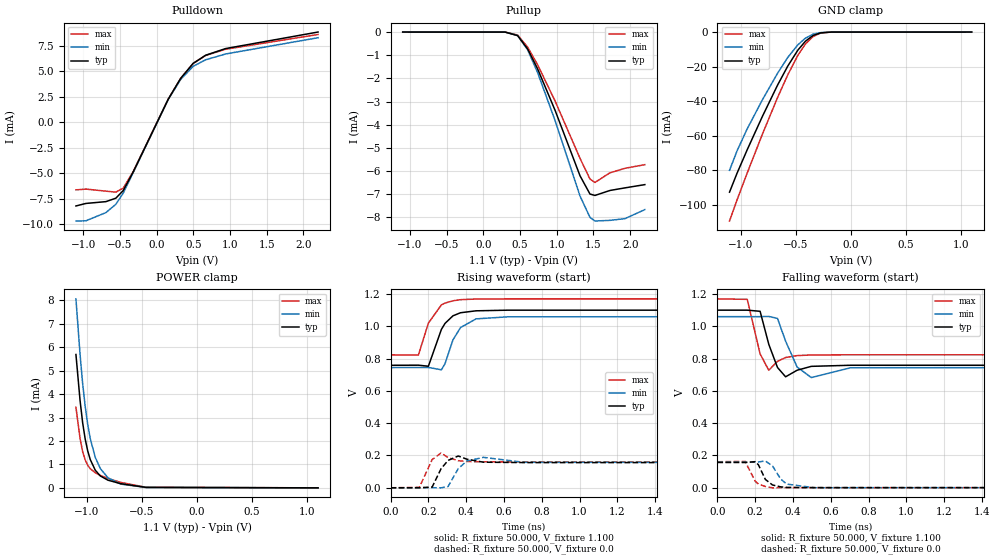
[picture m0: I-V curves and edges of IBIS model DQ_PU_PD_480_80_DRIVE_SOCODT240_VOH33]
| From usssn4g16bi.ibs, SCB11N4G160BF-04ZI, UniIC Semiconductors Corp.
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|   Model DQ_PU_PD_480_80_DRIVE_SOCODT240_VOH33
[Model] DQ_PU_PD_480_80_DRIVE_SOCODT240_VOH33
Model_type I/O
Polarity   Inverting
Vinl =  98.000mV
Vinh =  0.268V
Vmeas =  0.183V
Rref =  50.000
Vref =  0.183V
C_comp   1.020pF   1.010pF   1.030pF
[Model Spec]
Vinh   0.268V   0.262V   0.280V
Vinl   98.000mV   92.000mV   0.110V
Vmeas   0.183V   0.177V   0.195V
Vref   0.183V   0.177V   0.195V
Rref   50.000   NA   NA
[Temperature Range]   25.000   85.000   -40.000
[Voltage Range]   1.100V   1.060V   1.170V
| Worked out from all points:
|   slope of the pulldown table from 0 to 0.165 V, typ, clamps not added: 70.2 ohm
|   GND clamp passes 1 mA (typ) near -0.30 V on its own axis
|   POWER clamp passes 1 mA (typ) near -0.95 V on its own axis
|   rising waveform, R_fixture 50.000, V_fixture 1.100: 20-80 % time 72.7ps typ, 75.2ps min, 70.1ps max; typ from 0.759 V to 1.1 V
|   rising waveform, R_fixture 50.000, V_fixture 0.0: 20-80 % time 36.6ps typ, 44.7ps min, 30.1ps max; typ from 0 V to 0.156 V
|   falling waveform, R_fixture 50.000, V_fixture 1.100: 20-80 % time 44.4ps typ, 55.2ps min, 35.3ps max; typ from 1.1 V to 0.759 V
|   falling waveform, R_fixture 50.000, V_fixture 0.0: 20-80 % time 45.9ps typ, 57.5ps min, 42.8ps max; typ from 0.156 V to 0 V
[Pulldown]
|Voltage   I(typ)   I(min)   I(max)
-1.1V     -8.193mA   -9.666mA   -6.618mA
-964mV    -7.945mA   -9.646mA   -6.54mA
-692mV    -7.769mA   -8.844mA   -6.742mA
-556mV    -7.432mA   -8.032mA   -6.841mA
-454mV    -6.673mA   -6.916mA   -6.44mA
-318mV    -4.841mA   -4.906mA   -4.804mA
158mV     2.257mA    2.237mA    2.267mA
328mV     4.302mA    4.2mA      4.305mA
498mV     5.77mA     5.483mA    5.759mA
668mV     6.567mA    6.118mA    6.54mA
940mV     7.217mA    6.688mA    7.152mA
2.2V      8.836mA    8.278mA    8.595mA
[Pullup]
|Voltage   I(typ)   I(min)   I(max)
-1.1V     500pA      2.606nA    0A
296mV     -2.948uA   -3.529uA   -1.641uA
466mV     -154.8uA   -152.1uA   -129.1uA
602mV     -725.8uA   -765uA     -649.5uA
738mV     -1.585mA   -1.746mA   -1.41mA
976mV     -3.374mA   -3.816mA   -2.972mA
1.316V    -6.198mA   -7.072mA   -5.446mA
1.452V    -6.989mA   -7.995mA   -6.341mA
1.52V     -7.049mA   -8.152mA   -6.489mA
1.724V    -6.835mA   -8.124mA   -6.072mA
1.928V    -6.723mA   -8.051mA   -5.878mA
2.2V      -6.582mA   -7.66mA    -5.721mA
[GND_clamp]
|Voltage   I(typ)   I(min)   I(max)
-1.1V     -92.78mA   -80.14mA   -109.5mA
-1.031V   -81.73mA   -68.77mA   -97.17mA
-939mV    -68.18mA   -56.07mA   -81.64mA
-801mV    -48.85mA   -39.25mA   -59.15mA
-663mV    -30.71mA   -23.84mA   -37.89mA
-571mV    -19.76mA   -14.75mA   -24.85mA
-479mV    -10.5mA    -7.415mA   -13.5mA
-410mV    -5.313mA   -3.546mA   -6.916mA
-341mV    -2.007mA   -1.262mA   -2.59mA
-272mV    -506.9uA   -323.5uA   -609.8uA
-180mV    -45.65uA   -36.06uA   -43.55uA
1.1V      0A         0A         0A
[POWER_clamp]
|Voltage   I(typ)   I(min)   I(max)
-1.1V     5.691mA    8.066mA    3.44mA
-1.062V   3.709mA    5.665mA    2.092mA
-1.039V   2.781mA    4.457mA    1.546mA
-1.016V   2.086mA    3.48mA     1.193mA
-993mV    1.578mA    2.707mA    966.5uA
-970mV    1.21mA     2.107mA    818.5uA
-924mV    750.8uA    1.296mA    641.3uA
-878mV    507uA      821.4uA    530.2uA
-809mV    327.4uA    430uA      403.3uA
-694mV    178.4uA    161uA      233uA
-464mV    19.89uA    15.19uA    23.61uA
1.1V      0A         0A         0A
[Ramp]
| variable   typ   min   max
dV/dt_r   93.600m/36.664p   94.432m/44.767p   96.210m/30.186p
dV/dt_f   0.205/44.503p   0.189/55.256p   0.208/35.422p
R_load = 50.000
[Rising Waveform]
R_fixture= 50.000
V_fixture= 1.100
V_fixture_min= 1.060
V_fixture_max= 1.170
|time   V(typ)   V(min)   V(max)
0s        758.6mV    744.6mV    823.3mV
147ps     759.3mV    745mV      821.7mV
200ps     752.7mV    745.1mV    1.02V
269ps     981.3mV    730.8mV    1.133V
288ps     1.018V     768.7mV    1.144V
330ps     1.065V     915.7mV    1.158V
370ps     1.084V     992.1mV    1.165V
452ps     1.096V     1.046V     1.169V
622ps     1.1V       1.059V     1.17V
3ns       1.1V       1.06V      1.17V
[Rising Waveform]
R_fixture= 50.000
V_fixture= 0.0
V_fixture_min= 0.0
V_fixture_max= 0.0
|time   V(typ)   V(min)   V(max)
0s        3.732uV    7.145uV    882.6nV
152ps     103.7uV    10.76uV    2.587mV
220ps     4.697mV    269.6uV    174.6mV
267ps     117.8mV    -495.1uV   215.5mV
304ps     169.4mV    7.341mV    186.9mV
358ps     196.8mV    118.5mV    167.5mV
403ps     177.2mV    165.3mV    162.8mV
491ps     158.4mV    188.4mV    160.7mV
705ps     156mV      157.7mV    160.3mV
3ns       156mV      157.4mV    160.3mV
[Falling Waveform]
R_fixture= 50.000
V_fixture= 1.100
V_fixture_min= 1.060
V_fixture_max= 1.170
|time   V(typ)   V(min)   V(max)
0s        1.1V       1.06V      1.17V
158ps     1.1V       1.06V      1.167V
226ps     1.093V     1.06V      828.9mV
272ps     888.3mV    1.061V     727.4mV
318ps     744.8mV    1.049V     782.8mV
361ps     686.9mV    907.8mV    806.4mV
422ps     727.7mV    747.4mV    818.3mV
497ps     751.7mV    682.2mV    822.2mV
705ps     758.5mV    743.1mV    823.3mV
3ns       758.6mV    744.6mV    823.3mV
[Falling Waveform]
R_fixture= 50.000
V_fixture= 0.0
V_fixture_min= 0.0
V_fixture_max= 0.0
|time   V(typ)   V(min)   V(max)
0s        156mV      157.4mV    160.3mV
147ps     155.8mV    157.2mV    162.6mV
200ps     161mV      157.4mV    39.31mV
217ps     141.6mV    158.9mV    22.47mV
254ps     50.63mV    165.2mV    6.835mV
292ps     16.24mV    133.7mV    -1.368mV
335ps     4.808mV    53.33mV    -442uV
367ps     1.283mV    21.94mV    -155.6uV
513ps     -62.95uV   -622.8uV   -828.7nV
3ns       2.958uV    7.055uV    500.8nV
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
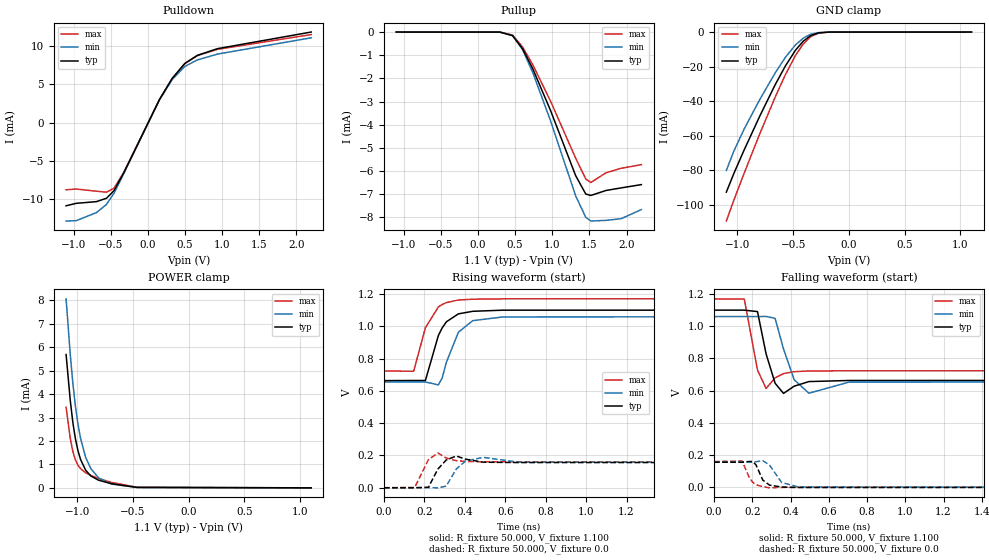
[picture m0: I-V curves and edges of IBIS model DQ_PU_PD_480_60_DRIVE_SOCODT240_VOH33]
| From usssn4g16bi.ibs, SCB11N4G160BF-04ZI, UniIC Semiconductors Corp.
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|   Model DQ_PU_PD_480_60_DRIVE_SOCODT240_VOH33
[Model] DQ_PU_PD_480_60_DRIVE_SOCODT240_VOH33
Model_type I/O
Polarity   Inverting
Vinl =  98.000mV
Vinh =  0.268V
Vmeas =  0.183V
Rref =  50.000
Vref =  0.183V
C_comp   1.020pF   1.010pF   1.030pF
[Model Spec]
Vinh   0.268V   0.262V   0.280V
Vinl   98.000mV   92.000mV   0.110V
Vmeas   0.183V   0.177V   0.195V
Vref   0.183V   0.177V   0.195V
Rref   50.000   NA   NA
[Temperature Range]   25.000   85.000   -40.000
[Voltage Range]   1.100V   1.060V   1.170V
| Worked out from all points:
|   slope of the pulldown table from 0 to 0.165 V, typ, clamps not added: 52.7 ohm
|   GND clamp passes 1 mA (typ) near -0.30 V on its own axis
|   POWER clamp passes 1 mA (typ) near -0.95 V on its own axis
|   rising waveform, R_fixture 50.000, V_fixture 1.100: 20-80 % time 74.3ps typ, 76.9ps min, 71.5ps max; typ from 0.663 V to 1.1 V
|   rising waveform, R_fixture 50.000, V_fixture 0.0: 20-80 % time 36.5ps typ, 44.4ps min, 30ps max; typ from 0 V to 0.156 V
|   falling waveform, R_fixture 50.000, V_fixture 1.100: 20-80 % time 43.7ps typ, 54.4ps min, 35ps max; typ from 1.1 V to 0.663 V
|   falling waveform, R_fixture 50.000, V_fixture 0.0: 20-80 % time 40.7ps typ, 54.3ps min, 37.6ps max; typ from 0.156 V to 0 V
[Pulldown]
|Voltage   I(typ)   I(min)   I(max)
-1.1V     -10.83mA   -12.81mA   -8.746mA
-964mV    -10.51mA   -12.77mA   -8.65mA
-692mV    -10.29mA   -11.72mA   -8.932mA
-556mV    -9.849mA   -10.65mA   -9.063mA
-454mV    -8.849mA   -9.178mA   -8.534mA
-318mV    -6.436mA   -6.525mA   -6.383mA
158mV     3.005mA    2.979mA    3.019mA
328mV     5.729mA    5.594mA    5.734mA
498mV     7.686mA    7.305mA    7.672mA
668mV     8.751mA    8.153mA    8.715mA
940mV     9.618mA    8.913mA    9.532mA
2.2V      11.78mA    11.03mA    11.45mA
[Pullup]
|Voltage   I(typ)   I(min)   I(max)
-1.1V     500pA      2.606nA    0A
296mV     -2.948uA   -3.529uA   -1.641uA
466mV     -154.8uA   -152.1uA   -129.1uA
602mV     -725.8uA   -765uA     -649.5uA
738mV     -1.585mA   -1.746mA   -1.41mA
976mV     -3.374mA   -3.816mA   -2.972mA
1.316V    -6.198mA   -7.072mA   -5.446mA
1.452V    -6.989mA   -7.995mA   -6.341mA
1.52V     -7.049mA   -8.152mA   -6.489mA
1.724V    -6.835mA   -8.124mA   -6.072mA
1.928V    -6.723mA   -8.051mA   -5.878mA
2.2V      -6.582mA   -7.66mA    -5.721mA
[GND_clamp]
|Voltage   I(typ)   I(min)   I(max)
-1.1V     -92.78mA   -80.14mA   -109.5mA
-1.031V   -81.73mA   -68.77mA   -97.17mA
-939mV    -68.18mA   -56.07mA   -81.64mA
-801mV    -48.85mA   -39.25mA   -59.15mA
-663mV    -30.71mA   -23.84mA   -37.89mA
-571mV    -19.76mA   -14.75mA   -24.85mA
-479mV    -10.5mA    -7.415mA   -13.5mA
-410mV    -5.313mA   -3.546mA   -6.916mA
-341mV    -2.007mA   -1.262mA   -2.59mA
-272mV    -506.9uA   -323.5uA   -609.8uA
-180mV    -45.65uA   -36.06uA   -43.55uA
1.1V      0A         0A         0A
[POWER_clamp]
|Voltage   I(typ)   I(min)   I(max)
-1.1V     5.691mA    8.066mA    3.44mA
-1.062V   3.709mA    5.665mA    2.092mA
-1.039V   2.781mA    4.457mA    1.546mA
-1.016V   2.086mA    3.48mA     1.193mA
-993mV    1.578mA    2.707mA    966.5uA
-970mV    1.21mA     2.107mA    818.5uA
-924mV    750.8uA    1.296mA    641.3uA
-878mV    507uA      821.4uA    530.2uA
-809mV    327.4uA    430uA      403.3uA
-694mV    178.4uA    161uA      233uA
-464mV    19.89uA    15.19uA    23.61uA
1.1V      0A         0A         0A
[Ramp]
| variable   typ   min   max
dV/dt_r   93.600m/36.486p   94.432m/44.493p   96.210m/30.147p
dV/dt_f   0.262/43.724p   0.243/54.501p   0.268/35.010p
R_load = 50.000
[Rising Waveform]
R_fixture= 50.000
V_fixture= 1.100
V_fixture_min= 1.060
V_fixture_max= 1.170
|time   V(typ)   V(min)   V(max)
0s        663.5mV    654.8mV    723.5mV
147ps     664.4mV    655.3mV    721.5mV
205ps     664.1mV    654.8mV    990.6mV
269ps     942.1mV    637.4mV    1.12V
288ps     990.3mV    679.8mV    1.135V
309ps     1.028V     777.8mV    1.147V
368ps     1.077V     963mV      1.163V
439ps     1.093V     1.035V     1.168V
589ps     1.1V       1.058V     1.17V
3ns       1.1V       1.06V      1.17V
[Rising Waveform]
R_fixture= 50.000
V_fixture= 0.0
V_fixture_min= 0.0
V_fixture_max= 0.0
|time   V(typ)   V(min)   V(max)
0s        3.262uV    6.246uV    771.1nV
152ps     171.2uV    9.155uV    1.764mV
220ps     3.07mV     378.1uV    173.9mV
267ps     116.1mV    -658.4uV   215.2mV
308ps     172mV      10.32mV    184.3mV
358ps     196.6mV    116.5mV    167.6mV
403ps     177.2mV    164.9mV    162.8mV
491ps     158.4mV    188.3mV    160.6mV
667ps     156mV      158mV      160.4mV
3ns       156mV      157.4mV    160.3mV
[Falling Waveform]
R_fixture= 50.000
V_fixture= 1.100
V_fixture_min= 1.060
V_fixture_max= 1.170
|time   V(typ)   V(min)   V(max)
0s        1.1V       1.06V      1.17V
158ps     1.1V       1.06V      1.169V
227ps     1.091V     1.06V      728.1mV
272ps     828.5mV    1.061V     614mV
319ps     646.5mV    1.049V     679.6mV
363ps     583.2mV    859.3mV    706.4mV
419ps     628.2mV    667.7mV    718.1mV
496ps     656.6mV    584.3mV    722.4mV
705ps     663.4mV    653.2mV    723.5mV
3ns       663.5mV    654.8mV    723.5mV
[Falling Waveform]
R_fixture= 50.000
V_fixture= 0.0
V_fixture_min= 0.0
V_fixture_max= 0.0
|time   V(typ)   V(min)   V(max)
0s        156mV      157.4mV    160.3mV
147ps     155.8mV    157.2mV    163.6mV
182ps     160.4mV    157mV      65.92mV
202ps     160.8mV    157.5mV    30.88mV
219ps     139.8mV    159.1mV    16.32mV
255ps     44.87mV    165.1mV    4.409mV
290ps     13.76mV    138.3mV    -3.026mV
353ps     1.95mV     30.16mV    -431.3uV
440ps     -858.6uV   2.579mV    -20.73uV
3ns       3.16uV     6.128uV    560.6nV
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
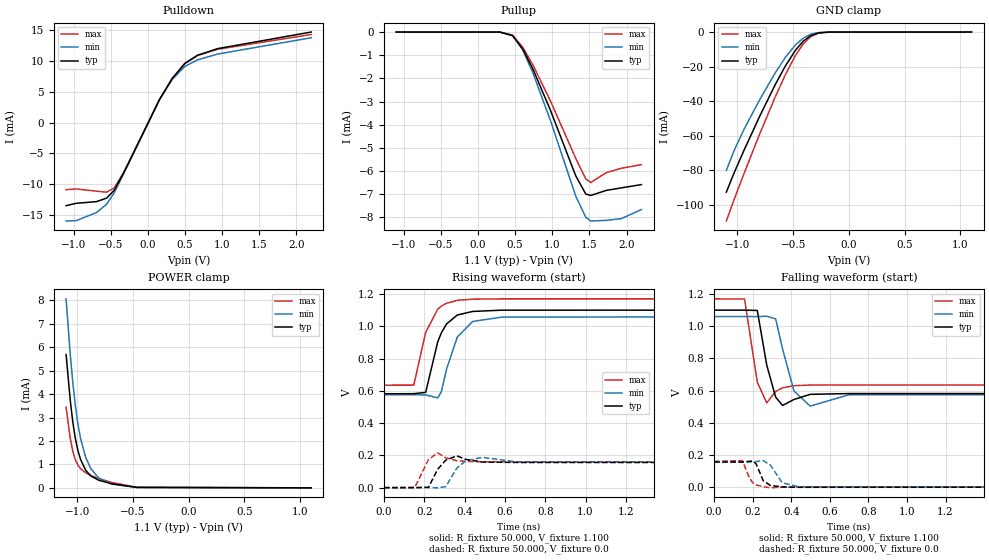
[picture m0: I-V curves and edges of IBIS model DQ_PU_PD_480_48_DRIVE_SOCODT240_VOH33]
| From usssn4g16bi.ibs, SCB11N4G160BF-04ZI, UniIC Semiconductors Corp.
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|   Model DQ_PU_PD_480_48_DRIVE_SOCODT240_VOH33
[Model] DQ_PU_PD_480_48_DRIVE_SOCODT240_VOH33
Model_type I/O
Polarity   Inverting
Vinl =  98.000mV
Vinh =  0.268V
Vmeas =  0.183V
Rref =  50.000
Vref =  0.183V
C_comp   1.020pF   1.010pF   1.030pF
[Model Spec]
Vinh   0.268V   0.262V   0.280V
Vinl   98.000mV   92.000mV   0.110V
Vmeas   0.183V   0.177V   0.195V
Vref   0.183V   0.177V   0.195V
Rref   50.000   NA   NA
[Temperature Range]   25.000   85.000   -40.000
[Voltage Range]   1.100V   1.060V   1.170V
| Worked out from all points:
|   slope of the pulldown table from 0 to 0.165 V, typ, clamps not added: 42.3 ohm
|   GND clamp passes 1 mA (typ) near -0.30 V on its own axis
|   POWER clamp passes 1 mA (typ) near -0.95 V on its own axis
|   rising waveform, R_fixture 50.000, V_fixture 1.100: 20-80 % time 75.5ps typ, 78.3ps min, 72.7ps max; typ from 0.582 V to 1.1 V
|   rising waveform, R_fixture 50.000, V_fixture 0.0: 20-80 % time 36.1ps typ, 44.1ps min, 29.8ps max; typ from 0 V to 0.156 V
|   falling waveform, R_fixture 50.000, V_fixture 1.100: 20-80 % time 42.4ps typ, 53.2ps min, 34.3ps max; typ from 1.1 V to 0.582 V
|   falling waveform, R_fixture 50.000, V_fixture 0.0: 20-80 % time 36.4ps typ, 50.3ps min, 33.4ps max; typ from 0.156 V to 0 V
[Pulldown]
|Voltage   I(typ)   I(min)   I(max)
-1.1V     -13.51mA   -16mA      -10.91mA
-964mV    -13.12mA   -15.94mA   -10.79mA
-692mV    -12.85mA   -14.63mA   -11.15mA
-556mV    -12.29mA   -13.29mA   -11.31mA
-454mV    -11.04mA   -11.45mA   -10.65mA
-318mV    -8.03mA    -8.142mA   -7.964mA
158mV     3.751mA    3.718mA    3.768mA
328mV     7.153mA    6.985mA    7.158mA
498mV     9.598mA    9.123mA    9.581mA
668mV     10.93mA    10.18mA    10.89mA
940mV     12.01mA    11.13mA    11.91mA
2.2V      14.71mA    13.78mA    14.31mA
[Pullup]
|Voltage   I(typ)   I(min)   I(max)
-1.1V     500pA      2.606nA    0A
296mV     -2.948uA   -3.529uA   -1.641uA
466mV     -154.8uA   -152.1uA   -129.1uA
602mV     -725.8uA   -765uA     -649.5uA
738mV     -1.585mA   -1.746mA   -1.41mA
976mV     -3.374mA   -3.816mA   -2.972mA
1.316V    -6.198mA   -7.072mA   -5.446mA
1.452V    -6.989mA   -7.995mA   -6.341mA
1.52V     -7.049mA   -8.152mA   -6.489mA
1.724V    -6.835mA   -8.124mA   -6.072mA
1.928V    -6.723mA   -8.051mA   -5.878mA
2.2V      -6.582mA   -7.66mA    -5.721mA
[GND_clamp]
|Voltage   I(typ)   I(min)   I(max)
-1.1V     -92.78mA   -80.14mA   -109.5mA
-1.031V   -81.73mA   -68.77mA   -97.17mA
-939mV    -68.18mA   -56.07mA   -81.64mA
-801mV    -48.85mA   -39.25mA   -59.15mA
-663mV    -30.71mA   -23.84mA   -37.89mA
-571mV    -19.76mA   -14.75mA   -24.85mA
-479mV    -10.5mA    -7.415mA   -13.5mA
-410mV    -5.313mA   -3.546mA   -6.916mA
-341mV    -2.007mA   -1.262mA   -2.59mA
-272mV    -506.9uA   -323.5uA   -609.8uA
-180mV    -45.65uA   -36.06uA   -43.55uA
1.1V      0A         0A         0A
[POWER_clamp]
|Voltage   I(typ)   I(min)   I(max)
-1.1V     5.691mA    8.066mA    3.44mA
-1.062V   3.709mA    5.665mA    2.092mA
-1.039V   2.781mA    4.457mA    1.546mA
-1.016V   2.086mA    3.48mA     1.193mA
-993mV    1.578mA    2.707mA    966.5uA
-970mV    1.21mA     2.107mA    818.5uA
-924mV    750.8uA    1.296mA    641.3uA
-878mV    507uA      821.4uA    530.2uA
-809mV    327.4uA    430uA      403.3uA
-694mV    178.4uA    161uA      233uA
-464mV    19.89uA    15.19uA    23.61uA
1.1V      0A         0A         0A
[Ramp]
| variable   typ   min   max
dV/dt_r   93.601m/36.320p   94.433m/44.127p   96.210m/30.018p
dV/dt_f   0.311/42.321p   0.291/53.189p   0.321/34.356p
R_load = 50.000
[Rising Waveform]
R_fixture= 50.000
V_fixture= 1.100
V_fixture_min= 1.060
V_fixture_max= 1.170
|time   V(typ)   V(min)   V(max)
0s        581.6mV    575.3mV    635mV
148ps     582.4mV    575.9mV    635.5mV
207ps     590.4mV    574.8mV    961.8mV
267ps     904.1mV    556.2mV    1.107V
285ps     959.8mV    596.1mV    1.125V
311ps     1.015V     736.1mV    1.143V
364ps     1.07V      933.4mV    1.161V
440ps     1.092V     1.03V      1.168V
585ps     1.1V       1.057V     1.17V
3ns       1.1V       1.06V      1.17V
[Rising Waveform]
R_fixture= 50.000
V_fixture= 0.0
V_fixture_min= 0.0
V_fixture_max= 0.0
|time   V(typ)   V(min)   V(max)
0s        2.898uV    5.55uV     685nV
153ps     271.6uV    5.056uV    1.55mV
221ps     2.351mV    510.8uV    174.7mV
267ps     114.7mV    -1.167mV   215.2mV
307ps     170.7mV    6.529mV    184.8mV
362ps     197.3mV    121.8mV    166.9mV
406ps     175.3mV    166.1mV    162.7mV
487ps     158.7mV    188mV      160.7mV
669ps     156mV      158mV      160.4mV
3ns       156mV      157.4mV    160.3mV
[Falling Waveform]
R_fixture= 50.000
V_fixture= 1.100
V_fixture_min= 1.060
V_fixture_max= 1.170
|time   V(typ)   V(min)   V(max)
0s        1.1V       1.06V      1.17V
158ps     1.1V       1.06V      1.169V
224ps     1.098V     1.06V      652.5mV
273ps     758.5mV    1.062V     523.5mV
319ps     559.9mV    1.046V     593.9mV
355ps     507.6mV    859.2mV    617.5mV
414ps     544.8mV    598.3mV    630.4mV
498ps     576.6mV    503.5mV    634.3mV
699ps     581.5mV    573.9mV    635mV
3ns       581.6mV    575.3mV    635mV
[Falling Waveform]
R_fixture= 50.000
V_fixture= 0.0
V_fixture_min= 0.0
V_fixture_max= 0.0
|time   V(typ)   V(min)   V(max)
0s        156mV      157.4mV    160.3mV
147ps     155.7mV    157.2mV    164.8mV
182ps     160.4mV    157mV      60.51mV
201ps     162.4mV    157.3mV    26.91mV
218ps     144.2mV    158.9mV    13.14mV
255ps     40.23mV    165mV      3.043mV
292ps     10.2mV     137mV      -4.399mV
353ps     1.401mV    27.36mV    -471.9uV
439ps     -1.026mV   2.044mV    -15.45uV
3ns       2.826uV    5.074uV    343.6nV
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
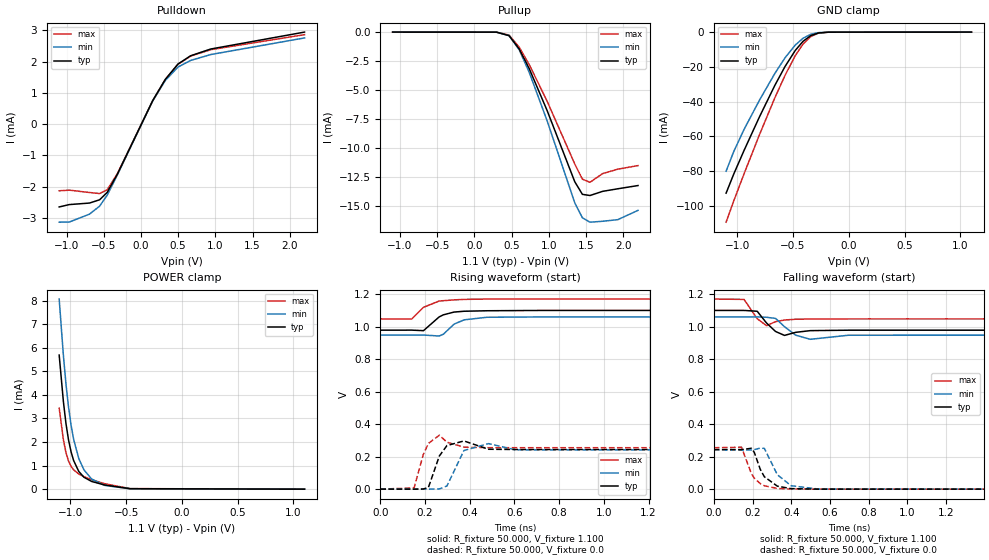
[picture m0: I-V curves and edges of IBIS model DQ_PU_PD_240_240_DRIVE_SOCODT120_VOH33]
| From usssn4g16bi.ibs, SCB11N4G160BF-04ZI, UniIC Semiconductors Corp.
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|   Model DQ_PU_PD_240_240_DRIVE_SOCODT120_VOH33
[Model] DQ_PU_PD_240_240_DRIVE_SOCODT120_VOH33
Model_type I/O
Polarity   Inverting
Vinl =  98.000mV
Vinh =  0.268V
Vmeas =  0.183V
Rref =  50.000
Vref =  0.183V
C_comp   1.020pF   1.010pF   1.030pF
[Model Spec]
Vinh   0.268V   0.262V   0.280V
Vinl   98.000mV   92.000mV   0.110V
Vmeas   0.183V   0.177V   0.195V
Vref   0.183V   0.177V   0.195V
Rref   50.000   NA   NA
[Temperature Range]   25.000   85.000   -40.000
[Voltage Range]   1.100V   1.060V   1.170V
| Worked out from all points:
|   slope of the pulldown table from 0 to 0.165 V, typ, clamps not added: 211 ohm
|   GND clamp passes 1 mA (typ) near -0.30 V on its own axis
|   POWER clamp passes 1 mA (typ) near -0.95 V on its own axis
|   rising waveform, R_fixture 50.000, V_fixture 1.100: 20-80 % time 68.4ps typ, 69.2ps min, 67.2ps max; typ from 0.978 V to 1.1 V
|   rising waveform, R_fixture 50.000, V_fixture 0.0: 20-80 % time 33.2ps typ, 41.1ps min, 27.1ps max; typ from 0 V to 0.244 V
|   falling waveform, R_fixture 50.000, V_fixture 1.100: 20-80 % time 46.2ps typ, 57.9ps min, 36ps max; typ from 1.1 V to 0.978 V
|   falling waveform, R_fixture 50.000, V_fixture 0.0: 20-80 % time 63.2ps typ, 70.2ps min, 60.2ps max; typ from 0.244 V to 0 V
[Pulldown]
|Voltage   I(typ)   I(min)   I(max)
-1.1V     -2.652mA   -3.14mA    -2.134mA
-964mV    -2.576mA   -3.135mA   -2.114mA
-692mV    -2.527mA   -2.882mA   -2.189mA
-556mV    -2.422mA   -2.626mA   -2.223mA
-454mV    -2.185mA   -2.274mA   -2.101mA
-318mV    -1.604mA   -1.629mA   -1.589mA
158mV     752.2uA    745.4uA    755.4uA
328mV     1.434mA    1.4mA      1.435mA
498mV     1.924mA    1.828mA    1.92mA
668mV     2.19mA     2.04mA     2.18mA
940mV     2.407mA    2.23mA     2.385mA
2.2V      2.948mA    2.761mA    2.866mA
[Pullup]
|Voltage   I(typ)   I(min)   I(max)
-1.1V     1nA        5.218nA    0A
296mV     -5.896uA   -7.058uA   -3.281uA
466mV     -309.5uA   -304uA     -258.1uA
602mV     -1.45mA    -1.529mA   -1.298mA
738mV     -3.167mA   -3.489mA   -2.817mA
976mV     -6.74mA    -7.622mA   -5.938mA
1.35V     -12.91mA   -14.73mA   -11.38mA
1.452V    -13.99mA   -16.01mA   -12.68mA
1.554V    -14.09mA   -16.39mA   -12.95mA
1.724V    -13.73mA   -16.31mA   -12.2mA
1.928V    -13.51mA   -16.17mA   -11.82mA
2.2V      -13.23mA   -15.37mA   -11.51mA
[GND_clamp]
|Voltage   I(typ)   I(min)   I(max)
-1.1V     -92.78mA   -80.14mA   -109.5mA
-1.031V   -81.73mA   -68.77mA   -97.17mA
-939mV    -68.18mA   -56.07mA   -81.64mA
-801mV    -48.85mA   -39.25mA   -59.15mA
-663mV    -30.71mA   -23.84mA   -37.89mA
-571mV    -19.76mA   -14.75mA   -24.85mA
-479mV    -10.5mA    -7.415mA   -13.5mA
-410mV    -5.313mA   -3.546mA   -6.916mA
-341mV    -2.007mA   -1.262mA   -2.59mA
-272mV    -506.9uA   -323.5uA   -609.8uA
-180mV    -45.65uA   -36.06uA   -43.55uA
1.1V      0A         0A         0A
[POWER_clamp]
|Voltage   I(typ)   I(min)   I(max)
-1.1V     5.691mA    8.066mA    3.44mA
-1.062V   3.709mA    5.665mA    2.092mA
-1.039V   2.781mA    4.457mA    1.546mA
-1.016V   2.086mA    3.48mA     1.193mA
-993mV    1.578mA    2.707mA    966.5uA
-970mV    1.21mA     2.107mA    818.5uA
-924mV    750.8uA    1.296mA    641.3uA
-878mV    507uA      821.4uA    530.2uA
-809mV    327.4uA    430uA      403.3uA
-694mV    178.4uA    161uA      233uA
-464mV    19.89uA    15.19uA    23.61uA
1.1V      0A         0A         0A
[Ramp]
| variable   typ   min   max
dV/dt_r   0.146/33.433p   0.145/41.080p   0.153/27.195p
dV/dt_f   72.903m/46.226p   67.052m/58.007p   73.268m/36.035p
R_load = 50.000
[Rising Waveform]
R_fixture= 50.000
V_fixture= 1.100
V_fixture_min= 1.060
V_fixture_max= 1.170
|time   V(typ)   V(min)   V(max)
0s        978.5mV    948.3mV    1.048V
140ps     978.8mV    948.4mV    1.047V
193ps     975.5mV    948.6mV    1.119V
263ps     1.06V      942.5mV    1.158V
282ps     1.073V     953.6mV    1.16V
330ps     1.09V      1.016V     1.165V
375ps     1.095V     1.042V     1.168V
476ps     1.098V     1.058V     1.17V
721ps     1.1V       1.06V      1.17V
3ns       1.1V       1.06V      1.17V
[Rising Waveform]
R_fixture= 50.000
V_fixture= 0.0
V_fixture_min= 0.0
V_fixture_max= 0.0
|time   V(typ)   V(min)   V(max)
0s        5.235uV    10.02uV    1.24uV
151ps     -127.8uV   45.32uV    7.711mV
192ps     848.9uV    -47.81uV   212.6mV
215ps     10.21mV    -154.5uV   281.6mV
264ps     204.2mV    1.17mV     331.9mV
298ps     268.3mV    19.55mV    288.9mV
374ps     296.6mV    237.9mV    258.3mV
484ps     245.5mV    280.3mV    255.2mV
604ps     244mV      242.1mV    255mV
3ns       243.9mV    241.2mV    255mV
[Falling Waveform]
R_fixture= 50.000
V_fixture= 1.100
V_fixture_min= 1.060
V_fixture_max= 1.170
|time   V(typ)   V(min)   V(max)
0s        1.1V       1.06V      1.17V
156ps     1.1V       1.06V      1.168V
224ps     1.095V     1.06V      1.049V
272ps     1.023V     1.058V     1.006V
319ps     970.3mV    1.051V     1.031V
365ps     946.4mV    1V         1.041V
423ps     965.3mV    947.7mV    1.046V
498ps     975.7mV    922.4mV    1.047V
697ps     978.4mV    947.6mV    1.048V
3ns       978.5mV    948.3mV    1.048V
[Falling Waveform]
R_fixture= 50.000
V_fixture= 0.0
V_fixture_min= 0.0
V_fixture_max= 0.0
|time   V(typ)   V(min)   V(max)
0s        243.9mV    241.2mV    255mV
143ps     243.7mV    240.9mV    258.3mV
194ps     251.5mV    241.1mV    95.54mV
209ps     226.3mV    243.4mV    68.11mV
240ps     121.8mV    252.8mV    33.86mV
261ps     76.35mV    250.7mV    20.93mV
328ps     18.5mV     88.91mV    4.304mV
399ps     3.312mV    21.3mV     941.3uV
539ps     201.8uV    770.9uV    47.05uV
3ns       5.289uV    10.03uV    1.062uV
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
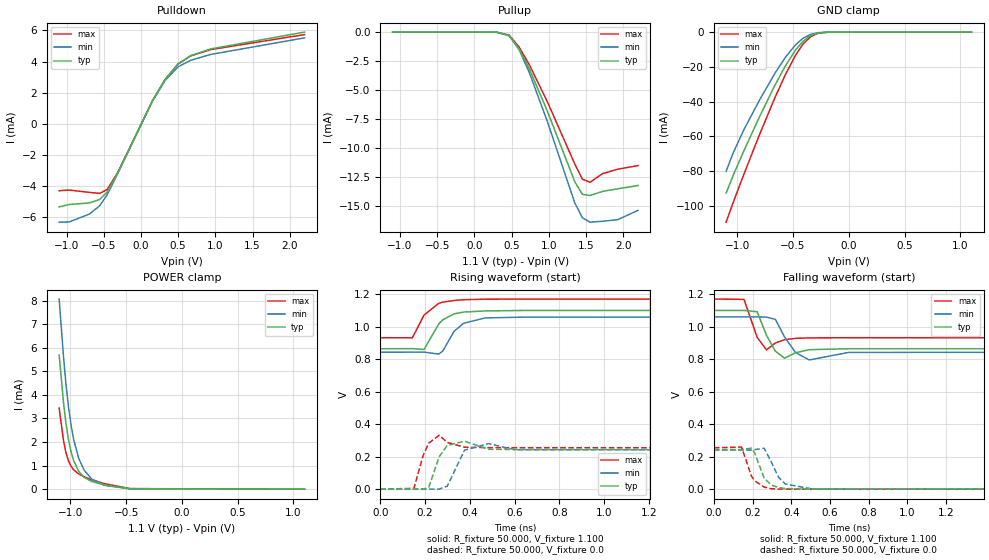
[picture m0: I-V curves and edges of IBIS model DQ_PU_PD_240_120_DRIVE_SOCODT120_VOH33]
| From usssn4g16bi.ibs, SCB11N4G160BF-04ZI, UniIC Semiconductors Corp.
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|   Model DQ_PU_PD_240_120_DRIVE_SOCODT120_VOH33
[Model] DQ_PU_PD_240_120_DRIVE_SOCODT120_VOH33
Model_type I/O
Polarity   Inverting
Vinl =  98.000mV
Vinh =  0.268V
Vmeas =  0.183V
Rref =  50.000
Vref =  0.183V
C_comp   1.020pF   1.010pF   1.030pF
[Model Spec]
Vinh   0.268V   0.262V   0.280V
Vinl   98.000mV   92.000mV   0.110V
Vmeas   0.183V   0.177V   0.195V
Vref   0.183V   0.177V   0.195V
Rref   50.000   NA   NA
[Temperature Range]   25.000   85.000   -40.000
[Voltage Range]   1.100V   1.060V   1.170V
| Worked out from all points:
|   slope of the pulldown table from 0 to 0.165 V, typ, clamps not added: 105 ohm
|   GND clamp passes 1 mA (typ) near -0.30 V on its own axis
|   POWER clamp passes 1 mA (typ) near -0.95 V on its own axis
|   rising waveform, R_fixture 50.000, V_fixture 1.100: 20-80 % time 70.2ps typ, 71.7ps min, 68.3ps max; typ from 0.864 V to 1.1 V
|   rising waveform, R_fixture 50.000, V_fixture 0.0: 20-80 % time 33ps typ, 40.6ps min, 27ps max; typ from 0 V to 0.244 V
|   falling waveform, R_fixture 50.000, V_fixture 1.100: 20-80 % time 45ps typ, 56ps min, 35.4ps max; typ from 1.1 V to 0.864 V
|   falling waveform, R_fixture 50.000, V_fixture 0.0: 20-80 % time 52.8ps typ, 63ps min, 49.4ps max; typ from 0.244 V to 0 V
[Pulldown]
|Voltage   I(typ)   I(min)   I(max)
-1.1V     -5.34mA    -6.324mA   -4.302mA
-964mV    -5.187mA   -6.308mA   -4.26mA
-692mV    -5.084mA   -5.795mA   -4.408mA
-556mV    -4.87mA    -5.274mA   -4.475mA
-454mV    -4.386mA   -4.558mA   -4.222mA
-318mV    -3.209mA   -3.256mA   -3.18mA
158mV     1.503mA    1.489mA    1.509mA
328mV     2.865mA    2.797mA    2.867mA
498mV     3.844mA    3.653mA    3.837mA
668mV     4.377mA    4.078mA    4.359mA
940mV     4.811mA    4.458mA    4.768mA
2.2V      5.891mA    5.519mA    5.73mA
[Pullup]
|Voltage   I(typ)   I(min)   I(max)
-1.1V     1nA        5.218nA    0A
296mV     -5.896uA   -7.058uA   -3.281uA
466mV     -309.5uA   -304uA     -258.1uA
602mV     -1.45mA    -1.529mA   -1.298mA
738mV     -3.167mA   -3.489mA   -2.817mA
976mV     -6.74mA    -7.622mA   -5.938mA
1.35V     -12.91mA   -14.73mA   -11.38mA
1.452V    -13.99mA   -16.01mA   -12.68mA
1.554V    -14.09mA   -16.39mA   -12.95mA
1.724V    -13.73mA   -16.31mA   -12.2mA
1.928V    -13.51mA   -16.17mA   -11.82mA
2.2V      -13.23mA   -15.37mA   -11.51mA
[GND_clamp]
|Voltage   I(typ)   I(min)   I(max)
-1.1V     -92.78mA   -80.14mA   -109.5mA
-1.031V   -81.73mA   -68.77mA   -97.17mA
-939mV    -68.18mA   -56.07mA   -81.64mA
-801mV    -48.85mA   -39.25mA   -59.15mA
-663mV    -30.71mA   -23.84mA   -37.89mA
-571mV    -19.76mA   -14.75mA   -24.85mA
-479mV    -10.5mA    -7.415mA   -13.5mA
-410mV    -5.313mA   -3.546mA   -6.916mA
-341mV    -2.007mA   -1.262mA   -2.59mA
-272mV    -506.9uA   -323.5uA   -609.8uA
-180mV    -45.65uA   -36.06uA   -43.55uA
1.1V      0A         0A         0A
[POWER_clamp]
|Voltage   I(typ)   I(min)   I(max)
-1.1V     5.691mA    8.066mA    3.44mA
-1.062V   3.709mA    5.665mA    2.092mA
-1.039V   2.781mA    4.457mA    1.546mA
-1.016V   2.086mA    3.48mA     1.193mA
-993mV    1.578mA    2.707mA    966.5uA
-970mV    1.21mA     2.107mA    818.5uA
-924mV    750.8uA    1.296mA    641.3uA
-878mV    507uA      821.4uA    530.2uA
-809mV    327.4uA    430uA      403.3uA
-694mV    178.4uA    161uA      233uA
-464mV    19.89uA    15.19uA    23.61uA
1.1V      0A         0A         0A
[Ramp]
| variable   typ   min   max
dV/dt_r   0.146/33.230p   0.145/40.538p   0.153/27.125p
dV/dt_f   0.141/45.073p   0.130/56.060p   0.143/35.492p
R_load = 50.000
[Rising Waveform]
R_fixture= 50.000
V_fixture= 1.100
V_fixture_min= 1.060
V_fixture_max= 1.170
|time   V(typ)   V(min)   V(max)
0s        864.4mV    842.9mV    932.1mV
143ps     864.9mV    843.2mV    931.7mV
195ps     859.6mV    843.4mV    1.071V
261ps     1.017V     831.3mV    1.144V
279ps     1.042V     850.2mV    1.151V
329ps     1.079V     971.2mV    1.161V
372ps     1.09V      1.021V     1.166V
468ps     1.097V     1.054V     1.169V
650ps     1.1V       1.059V     1.17V
3ns       1.1V       1.06V      1.17V
[Rising Waveform]
R_fixture= 50.000
V_fixture= 0.0
V_fixture_min= 0.0
V_fixture_max= 0.0
|time   V(typ)   V(min)   V(max)
0s        4.356uV    8.339uV    1.031uV
150ps     -32.14uV   35.1uV     5.218mV
191ps     430uV      11.06uV    206.9mV
216ps     9.823mV    5.395uV    282.9mV
263ps     200mV      543.8uV    331.7mV
299ps     269.1mV    18.84mV    287.7mV
376ps     295.1mV    240mV      258.1mV
483ps     245.5mV    280.2mV    255.2mV
603ps     244mV      242.2mV    255mV
3ns       243.9mV    241.2mV    255mV
[Falling Waveform]
R_fixture= 50.000
V_fixture= 1.100
V_fixture_min= 1.060
V_fixture_max= 1.170
|time   V(typ)   V(min)   V(max)
0s        1.1V       1.06V      1.17V
156ps     1.1V       1.06V      1.168V
224ps     1.092V     1.06V      933.6mV
272ps     946.8mV    1.059V     857.2mV
318ps     849.4mV    1.045V     900mV
365ps     806.1mV    937.5mV    919.8mV
422ps     839.8mV    840.6mV    928.2mV
493ps     858.5mV    795.4mV    931.2mV
697ps     864.3mV    841.7mV    932.1mV
3ns       864.4mV    842.9mV    932.1mV
[Falling Waveform]
R_fixture= 50.000
V_fixture= 0.0
V_fixture_min= 0.0
V_fixture_max= 0.0
|time   V(typ)   V(min)   V(max)
0s        243.9mV    241.2mV    255mV
143ps     243.6mV    240.9mV    259.1mV
194ps     252.3mV    241.1mV    81.09mV
210ps     225.5mV    243.5mV    51.95mV
260ps     66.6mV     251.9mV    12.77mV
298ps     24.96mV    164.4mV    2.487mV
334ps     10.2mV     73.75mV    1.009mV
369ps     3.657mV    31.46mV    421.1uV
514ps     29.09uV    299.2uV    11.12uV
3ns       2.675uV    8.194uV    -504.3nV
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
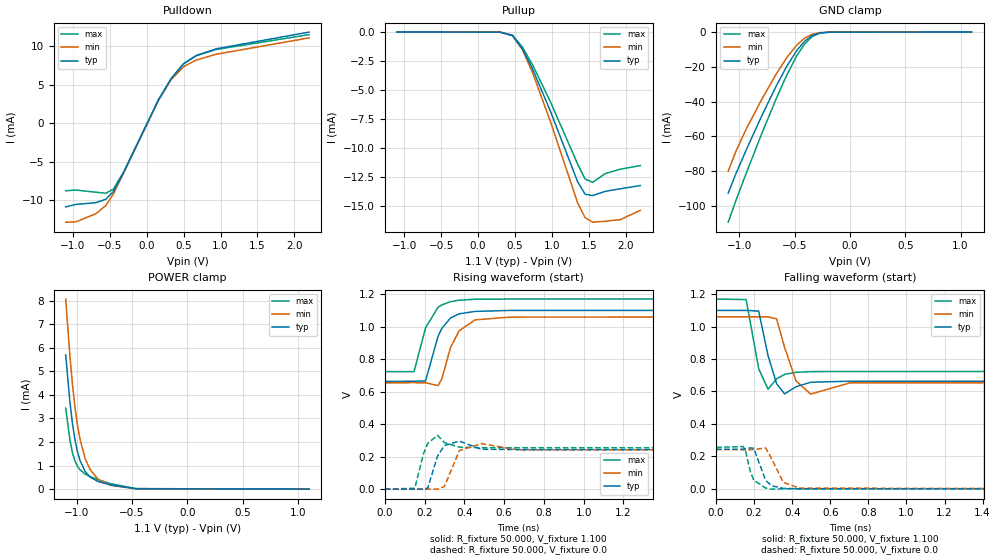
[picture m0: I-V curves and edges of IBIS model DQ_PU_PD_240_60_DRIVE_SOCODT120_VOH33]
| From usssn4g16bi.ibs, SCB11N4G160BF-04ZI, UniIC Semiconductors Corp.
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|   Model DQ_PU_PD_240_60_DRIVE_SOCODT120_VOH33
[Model] DQ_PU_PD_240_60_DRIVE_SOCODT120_VOH33
Model_type I/O
Polarity   Inverting
Vinl =  98.000mV
Vinh =  0.268V
Vmeas =  0.183V
Rref =  50.000
Vref =  0.183V
C_comp   1.020pF   1.010pF   1.030pF
[Model Spec]
Vinh   0.268V   0.262V   0.280V
Vinl   98.000mV   92.000mV   0.110V
Vmeas   0.183V   0.177V   0.195V
Vref   0.183V   0.177V   0.195V
Rref   50.000   NA   NA
[Temperature Range]   25.000   85.000   -40.000
[Voltage Range]   1.100V   1.060V   1.170V
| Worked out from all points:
|   slope of the pulldown table from 0 to 0.165 V, typ, clamps not added: 52.7 ohm
|   GND clamp passes 1 mA (typ) near -0.30 V on its own axis
|   POWER clamp passes 1 mA (typ) near -0.95 V on its own axis
|   rising waveform, R_fixture 50.000, V_fixture 1.100: 20-80 % time 74.1ps typ, 76.4ps min, 71.3ps max; typ from 0.663 V to 1.1 V
|   rising waveform, R_fixture 50.000, V_fixture 0.0: 20-80 % time 33ps typ, 40.3ps min, 27.1ps max; typ from 0 V to 0.244 V
|   falling waveform, R_fixture 50.000, V_fixture 1.100: 20-80 % time 43.8ps typ, 54.6ps min, 35.1ps max; typ from 1.1 V to 0.663 V
|   falling waveform, R_fixture 50.000, V_fixture 0.0: 20-80 % time 41.9ps typ, 57.3ps min, 37.5ps max; typ from 0.244 V to 0 V
[Pulldown]
|Voltage   I(typ)   I(min)   I(max)
-1.1V     -10.83mA   -12.81mA   -8.746mA
-964mV    -10.51mA   -12.77mA   -8.65mA
-692mV    -10.29mA   -11.72mA   -8.932mA
-556mV    -9.849mA   -10.65mA   -9.063mA
-454mV    -8.849mA   -9.178mA   -8.534mA
-318mV    -6.436mA   -6.525mA   -6.383mA
158mV     3.005mA    2.979mA    3.019mA
328mV     5.729mA    5.594mA    5.734mA
498mV     7.686mA    7.305mA    7.672mA
668mV     8.751mA    8.153mA    8.715mA
940mV     9.618mA    8.913mA    9.532mA
2.2V      11.78mA    11.03mA    11.45mA
[Pullup]
|Voltage   I(typ)   I(min)   I(max)
-1.1V     1nA        5.218nA    0A
296mV     -5.896uA   -7.058uA   -3.281uA
466mV     -309.5uA   -304uA     -258.1uA
602mV     -1.45mA    -1.529mA   -1.298mA
738mV     -3.167mA   -3.489mA   -2.817mA
976mV     -6.74mA    -7.622mA   -5.938mA
1.35V     -12.91mA   -14.73mA   -11.38mA
1.452V    -13.99mA   -16.01mA   -12.68mA
1.554V    -14.09mA   -16.39mA   -12.95mA
1.724V    -13.73mA   -16.31mA   -12.2mA
1.928V    -13.51mA   -16.17mA   -11.82mA
2.2V      -13.23mA   -15.37mA   -11.51mA
[GND_clamp]
|Voltage   I(typ)   I(min)   I(max)
-1.1V     -92.78mA   -80.14mA   -109.5mA
-1.031V   -81.73mA   -68.77mA   -97.17mA
-939mV    -68.18mA   -56.07mA   -81.64mA
-801mV    -48.85mA   -39.25mA   -59.15mA
-663mV    -30.71mA   -23.84mA   -37.89mA
-571mV    -19.76mA   -14.75mA   -24.85mA
-479mV    -10.5mA    -7.415mA   -13.5mA
-410mV    -5.313mA   -3.546mA   -6.916mA
-341mV    -2.007mA   -1.262mA   -2.59mA
-272mV    -506.9uA   -323.5uA   -609.8uA
-180mV    -45.65uA   -36.06uA   -43.55uA
1.1V      0A         0A         0A
[POWER_clamp]
|Voltage   I(typ)   I(min)   I(max)
-1.1V     5.691mA    8.066mA    3.44mA
-1.062V   3.709mA    5.665mA    2.092mA
-1.039V   2.781mA    4.457mA    1.546mA
-1.016V   2.086mA    3.48mA     1.193mA
-993mV    1.578mA    2.707mA    966.5uA
-970mV    1.21mA     2.107mA    818.5uA
-924mV    750.8uA    1.296mA    641.3uA
-878mV    507uA      821.4uA    530.2uA
-809mV    327.4uA    430uA      403.3uA
-694mV    178.4uA    161uA      233uA
-464mV    19.89uA    15.19uA    23.61uA
1.1V      0A         0A         0A
[Ramp]
| variable   typ   min   max
dV/dt_r   0.146/33.122p   0.145/40.389p   0.153/27.213p
dV/dt_f   0.262/43.898p   0.243/54.813p   0.268/35.061p
R_load = 50.000
[Rising Waveform]
R_fixture= 50.000
V_fixture= 1.100
V_fixture_min= 1.060
V_fixture_max= 1.170
|time   V(typ)   V(min)   V(max)
0s        663.5mV    654.8mV    723.5mV
147ps     664.3mV    655.3mV    723.2mV
205ps     665.9mV    654.7mV    993mV
268ps     941.5mV    637.7mV    1.12V
287ps     989.9mV    678.8mV    1.134V
330ps     1.053V     869.9mV    1.154V
373ps     1.079V     973.7mV    1.163V
454ps     1.094V     1.042V     1.169V
630ps     1.1V       1.059V     1.17V
3ns       1.1V       1.06V      1.17V
[Rising Waveform]
R_fixture= 50.000
V_fixture= 0.0
V_fixture_min= 0.0
V_fixture_max= 0.0
|time   V(typ)   V(min)   V(max)
0s        3.262uV    6.246uV    771.1nV
151ps     63.3uV     18.38uV    5.378mV
194ps     616uV      47.83uV    216.2mV
216ps     7.193mV    221.9uV    281.4mV
265ps     203.2mV    499.1uV    331.7mV
300ps     269mV      16.73mV    286.4mV
375ps     295.6mV    237.4mV    258.2mV
485ps     245.4mV    280.3mV    255.2mV
673ps     243.9mV    241.4mV    255mV
3ns       243.9mV    241.2mV    255mV
[Falling Waveform]
R_fixture= 50.000
V_fixture= 1.100
V_fixture_min= 1.060
V_fixture_max= 1.170
|time   V(typ)   V(min)   V(max)
0s        1.1V       1.06V      1.17V
158ps     1.1V       1.06V      1.167V
224ps     1.096V     1.06V      740.6mV
273ps     821.6mV    1.06V      613.7mV
318ps     648.2mV    1.048V     678.5mV
360ps     585.3mV    872.4mV    705.2mV
420ps     629.1mV    665.1mV    718.3mV
497ps     656.8mV    584mV      722.5mV
703ps     663.4mV    653.1mV    723.5mV
3ns       663.5mV    654.8mV    723.5mV
[Falling Waveform]
R_fixture= 50.000
V_fixture= 0.0
V_fixture_min= 0.0
V_fixture_max= 0.0
|time   V(typ)   V(min)   V(max)
0s        243.9mV    241.2mV    255mV
143ps     243.5mV    240.9mV    260.4mV
155ps     245mV      240.7mV    234.6mV
179ps     251.8mV    240.5mV    110.3mV
198ps     250mV      241.4mV    52.96mV
260ps     52.71mV    251.8mV    5.02mV
291ps     18.47mV    188mV      -2.583mV
353ps     2.638mV    39.25mV    -366.1uV
440ps     -813uV     3.295mV    -16.13uV
3ns       2.909uV    6.156uV    495.6nV
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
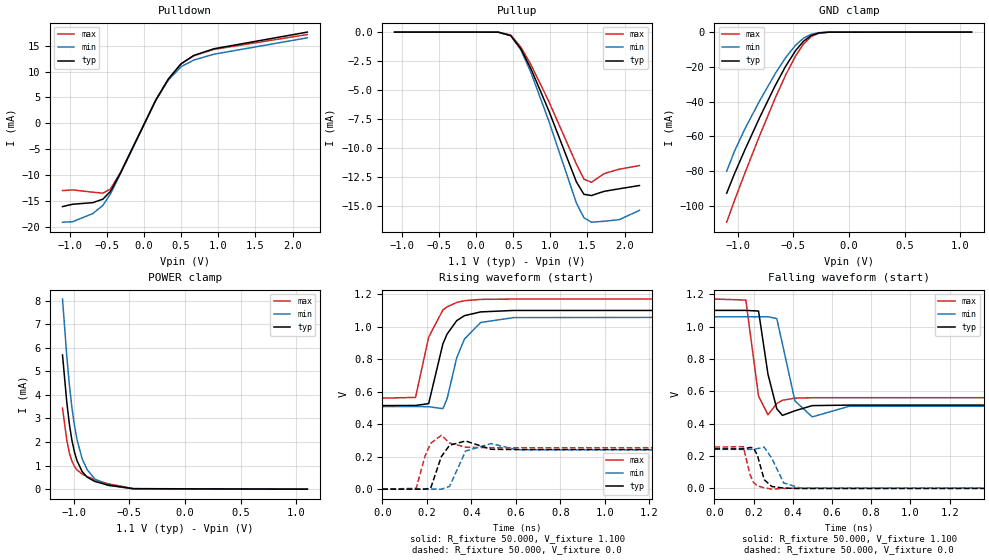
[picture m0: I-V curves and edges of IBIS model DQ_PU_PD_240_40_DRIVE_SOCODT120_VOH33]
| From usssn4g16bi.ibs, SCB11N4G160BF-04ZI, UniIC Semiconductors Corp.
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|   Model DQ_PU_PD_240_40_DRIVE_SOCODT120_VOH33
[Model] DQ_PU_PD_240_40_DRIVE_SOCODT120_VOH33
Model_type I/O
Polarity   Inverting
Vinl =  98.000mV
Vinh =  0.268V
Vmeas =  0.183V
Rref =  50.000
Vref =  0.183V
C_comp   1.020pF   1.010pF   1.030pF
[Model Spec]
Vinh   0.268V   0.262V   0.280V
Vinl   98.000mV   92.000mV   0.110V
Vmeas   0.183V   0.177V   0.195V
Vref   0.183V   0.177V   0.195V
Rref   50.000   NA   NA
[Temperature Range]   25.000   85.000   -40.000
[Voltage Range]   1.100V   1.060V   1.170V
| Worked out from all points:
|   slope of the pulldown table from 0 to 0.165 V, typ, clamps not added: 35.3 ohm
|   GND clamp passes 1 mA (typ) near -0.30 V on its own axis
|   POWER clamp passes 1 mA (typ) near -0.95 V on its own axis
|   rising waveform, R_fixture 50.000, V_fixture 1.100: 20-80 % time 76.3ps typ, 79.1ps min, 73.4ps max; typ from 0.514 V to 1.1 V
|   rising waveform, R_fixture 50.000, V_fixture 0.0: 20-80 % time 32.8ps typ, 40.1ps min, 27ps max; typ from 0 V to 0.244 V
|   falling waveform, R_fixture 50.000, V_fixture 1.100: 20-80 % time 40.6ps typ, 51.6ps min, 33.3ps max; typ from 1.1 V to 0.514 V
|   falling waveform, R_fixture 50.000, V_fixture 0.0: 20-80 % time 34.9ps typ, 53.4ps min, 30.4ps max; typ from 0.244 V to 0 V
[Pulldown]
|Voltage   I(typ)   I(min)   I(max)
-1.1V     -16.13mA   -19.15mA   -13.03mA
-964mV    -15.68mA   -19.06mA   -12.9mA
-692mV    -15.37mA   -17.49mA   -13.34mA
-556mV    -14.7mA    -15.89mA   -13.53mA
-454mV    -13.2mA    -13.69mA   -12.73mA
-318mV    -9.609mA   -9.745mA   -9.529mA
158mV     4.492mA    4.453mA    4.512mA
328mV     8.568mA    8.368mA    8.576mA
498mV     11.5mA     10.93mA    11.48mA
668mV     13.1mA     12.21mA    13.05mA
940mV     14.4mA     13.35mA    14.28mA
2.2V      17.63mA    16.52mA    17.16mA
[Pullup]
|Voltage   I(typ)   I(min)   I(max)
-1.1V     1nA        5.218nA    0A
296mV     -5.896uA   -7.058uA   -3.281uA
466mV     -309.5uA   -304uA     -258.1uA
602mV     -1.45mA    -1.529mA   -1.298mA
738mV     -3.167mA   -3.489mA   -2.817mA
976mV     -6.74mA    -7.622mA   -5.938mA
1.35V     -12.91mA   -14.73mA   -11.38mA
1.452V    -13.99mA   -16.01mA   -12.68mA
1.554V    -14.09mA   -16.39mA   -12.95mA
1.724V    -13.73mA   -16.31mA   -12.2mA
1.928V    -13.51mA   -16.17mA   -11.82mA
2.2V      -13.23mA   -15.37mA   -11.51mA
[GND_clamp]
|Voltage   I(typ)   I(min)   I(max)
-1.1V     -92.78mA   -80.14mA   -109.5mA
-1.031V   -81.73mA   -68.77mA   -97.17mA
-939mV    -68.18mA   -56.07mA   -81.64mA
-801mV    -48.85mA   -39.25mA   -59.15mA
-663mV    -30.71mA   -23.84mA   -37.89mA
-571mV    -19.76mA   -14.75mA   -24.85mA
-479mV    -10.5mA    -7.415mA   -13.5mA
-410mV    -5.313mA   -3.546mA   -6.916mA
-341mV    -2.007mA   -1.262mA   -2.59mA
-272mV    -506.9uA   -323.5uA   -609.8uA
-180mV    -45.65uA   -36.06uA   -43.55uA
1.1V      0A         0A         0A
[POWER_clamp]
|Voltage   I(typ)   I(min)   I(max)
-1.1V     5.691mA    8.066mA    3.44mA
-1.062V   3.709mA    5.665mA    2.092mA
-1.039V   2.781mA    4.457mA    1.546mA
-1.016V   2.086mA    3.48mA     1.193mA
-993mV    1.578mA    2.707mA    966.5uA
-970mV    1.21mA     2.107mA    818.5uA
-924mV    750.8uA    1.296mA    641.3uA
-878mV    507uA      821.4uA    530.2uA
-809mV    327.4uA    430uA      403.3uA
-694mV    178.4uA    161uA      233uA
-464mV    19.89uA    15.19uA    23.61uA
1.1V      0A         0A         0A
[Ramp]
| variable   typ   min   max
dV/dt_r   0.146/32.899p   0.145/40.177p   0.153/27.065p
dV/dt_f   0.351/40.740p   0.331/51.530p   0.366/33.372p
R_load = 50.000
[Rising Waveform]
R_fixture= 50.000
V_fixture= 1.100
V_fixture_min= 1.060
V_fixture_max= 1.170
|time   V(typ)   V(min)   V(max)
0s        514.4mV    508.1mV    560.3mV
149ps     515.1mV    508.7mV    564.6mV
208ps     526.6mV    507.6mV    935.4mV
272ps     894.5mV    495.5mV    1.103V
291ps     955.1mV    557.3mV    1.122V
334ps     1.037V     808.6mV    1.149V
369ps     1.068V     924.3mV    1.16V
442ps     1.091V     1.026V     1.168V
591ps     1.1V       1.056V     1.17V
3ns       1.1V       1.06V      1.17V
[Rising Waveform]
R_fixture= 50.000
V_fixture= 0.0
V_fixture_min= 0.0
V_fixture_max= 0.0
|time   V(typ)   V(min)   V(max)
0s        2.608uV    4.994uV    616.3nV
152ps     220.9uV    14.7uV     5.14mV
192ps     375.9uV    104uV      204.8mV
217ps     5.989mV    445.2uV    282.2mV
265ps     200.4mV    58.98uV    331.6mV
302ps     270.3mV    16.85mV    284.2mV
374ps     296.5mV    234.5mV    258.3mV
488ps     245.3mV    280.6mV    255.1mV
605ps     244mV      242.1mV    255mV
3ns       243.9mV    241.2mV    255mV
[Falling Waveform]
R_fixture= 50.000
V_fixture= 1.100
V_fixture_min= 1.060
V_fixture_max= 1.170
|time   V(typ)   V(min)   V(max)
0s        1.1V       1.06V      1.17V
160ps     1.1V       1.06V      1.164V
225ps     1.096V     1.06V      570.3mV
273ps     706mV      1.061V     454.4mV
318ps     491.8mV    1.049V     524.5mV
347ps     450.9mV    891.1mV    544.3mV
411ps     479.5mV    539.9mV    557.3mV
499ps     511.3mV    441.5mV    560mV
687ps     514.4mV    507mV      560.3mV
3ns       514.4mV    508.1mV    560.3mV
[Falling Waveform]
R_fixture= 50.000
V_fixture= 0.0
V_fixture_min= 0.0
V_fixture_max= 0.0
|time   V(typ)   V(min)   V(max)
0s        243.9mV    241.2mV    255mV
147ps     243.8mV    240.8mV    257.5mV
182ps     252.6mV    240.5mV    83.29mV
199ps     250.4mV    241.5mV    36.52mV
219ps     204.4mV    245.4mV    14.37mV
254ps     53.6mV     254.1mV    3.217mV
293ps     11.01mV    185.5mV    -5.224mV
353ps     1.419mV    33.27mV    -454.4uV
436ps     -1.279mV   2.293mV    -11.73uV
3ns       898.7nV    3.62uV     178.5nV
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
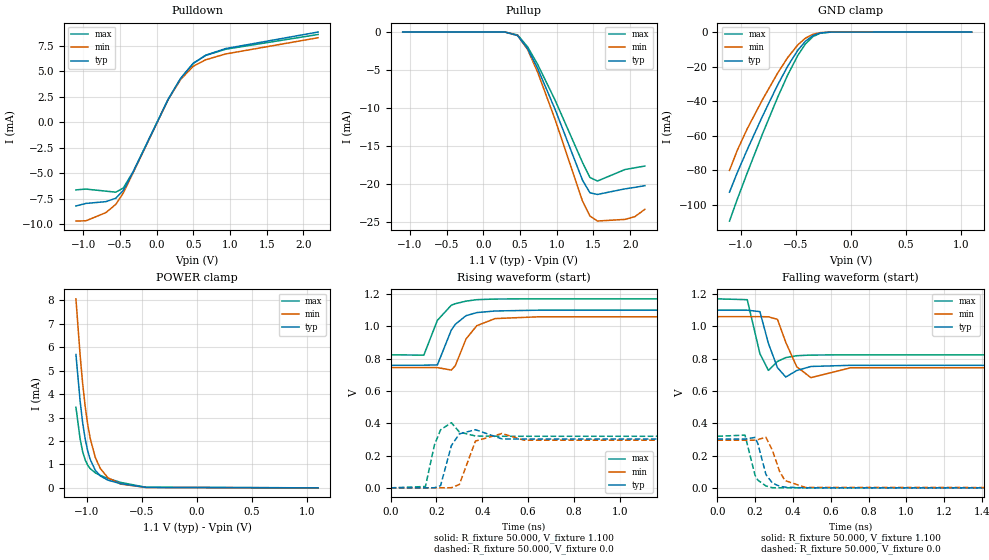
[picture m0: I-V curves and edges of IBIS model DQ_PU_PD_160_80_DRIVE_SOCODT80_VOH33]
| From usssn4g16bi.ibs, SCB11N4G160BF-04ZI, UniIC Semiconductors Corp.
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|   Model DQ_PU_PD_160_80_DRIVE_SOCODT80_VOH33
[Model] DQ_PU_PD_160_80_DRIVE_SOCODT80_VOH33
Model_type I/O
Polarity   Inverting
Vinl =  98.000mV
Vinh =  0.268V
Vmeas =  0.183V
Rref =  50.000
Vref =  0.183V
C_comp   1.020pF   1.010pF   1.030pF
[Model Spec]
Vinh   0.268V   0.262V   0.280V
Vinl   98.000mV   92.000mV   0.110V
Vmeas   0.183V   0.177V   0.195V
Vref   0.183V   0.177V   0.195V
Rref   50.000   NA   NA
[Temperature Range]   25.000   85.000   -40.000
[Voltage Range]   1.100V   1.060V   1.170V
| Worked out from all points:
|   slope of the pulldown table from 0 to 0.165 V, typ, clamps not added: 70.2 ohm
|   GND clamp passes 1 mA (typ) near -0.30 V on its own axis
|   POWER clamp passes 1 mA (typ) near -0.95 V on its own axis
|   rising waveform, R_fixture 50.000, V_fixture 1.100: 20-80 % time 71.7ps typ, 73ps min, 69.7ps max; typ from 0.759 V to 1.1 V
|   rising waveform, R_fixture 50.000, V_fixture 0.0: 20-80 % time 30.6ps typ, 37.4ps min, 25.1ps max; typ from 0 V to 0.302 V
|   falling waveform, R_fixture 50.000, V_fixture 1.100: 20-80 % time 44.9ps typ, 56.1ps min, 35.6ps max; typ from 1.1 V to 0.759 V
|   falling waveform, R_fixture 50.000, V_fixture 0.0: 20-80 % time 45.6ps typ, 58.2ps min, 42ps max; typ from 0.302 V to 0 V
[Pulldown]
|Voltage   I(typ)   I(min)   I(max)
-1.1V     -8.193mA   -9.666mA   -6.618mA
-964mV    -7.945mA   -9.646mA   -6.54mA
-692mV    -7.769mA   -8.844mA   -6.742mA
-556mV    -7.432mA   -8.032mA   -6.841mA
-454mV    -6.673mA   -6.916mA   -6.44mA
-318mV    -4.841mA   -4.906mA   -4.804mA
158mV     2.257mA    2.237mA    2.267mA
328mV     4.302mA    4.2mA      4.305mA
498mV     5.77mA     5.483mA    5.759mA
668mV     6.567mA    6.118mA    6.54mA
940mV     7.217mA    6.688mA    7.152mA
2.2V      8.836mA    8.278mA    8.595mA
[Pullup]
|Voltage   I(typ)   I(min)   I(max)
-1.1V     1.606nA    7.718nA    0A
296mV     -8.845uA   -10.59uA   -4.922uA
466mV     -464.7uA   -456.5uA   -387.5uA
602mV     -2.18mA    -2.299mA   -1.951mA
738mV     -4.764mA   -5.249mA   -4.236mA
976mV     -10.14mA   -11.47mA   -8.932mA
1.35V     -19.45mA   -22.19mA   -17.13mA
1.452V    -21.12mA   -24.17mA   -19.11mA
1.554V    -21.33mA   -24.82mA   -19.57mA
1.928V    -20.6mA    -24.61mA   -18.06mA
2.064V    -20.4mA    -24.25mA   -17.83mA
2.2V      -20.18mA   -23.28mA   -17.6mA
[GND_clamp]
|Voltage   I(typ)   I(min)   I(max)
-1.1V     -92.78mA   -80.14mA   -109.5mA
-1.031V   -81.73mA   -68.77mA   -97.17mA
-939mV    -68.18mA   -56.07mA   -81.64mA
-801mV    -48.85mA   -39.25mA   -59.15mA
-663mV    -30.71mA   -23.84mA   -37.89mA
-571mV    -19.76mA   -14.75mA   -24.85mA
-479mV    -10.5mA    -7.415mA   -13.5mA
-410mV    -5.313mA   -3.546mA   -6.916mA
-341mV    -2.007mA   -1.262mA   -2.59mA
-272mV    -506.9uA   -323.5uA   -609.8uA
-180mV    -45.65uA   -36.06uA   -43.55uA
1.1V      0A         0A         0A
[POWER_clamp]
|Voltage   I(typ)   I(min)   I(max)
-1.1V     5.691mA    8.066mA    3.44mA
-1.062V   3.709mA    5.665mA    2.092mA
-1.039V   2.781mA    4.457mA    1.546mA
-1.016V   2.086mA    3.48mA     1.193mA
-993mV    1.578mA    2.707mA    966.5uA
-970mV    1.21mA     2.107mA    818.5uA
-924mV    750.8uA    1.296mA    641.3uA
-878mV    507uA      821.4uA    530.2uA
-809mV    327.4uA    430uA      403.3uA
-694mV    178.4uA    161uA      233uA
-464mV    19.89uA    15.19uA    23.61uA
1.1V      0A         0A         0A
[Ramp]
| variable   typ   min   max
dV/dt_r   0.181/30.714p   0.177/37.537p   0.192/25.170p
dV/dt_f   0.205/44.979p   0.189/56.073p   0.208/35.640p
R_load = 50.000
[Rising Waveform]
R_fixture= 50.000
V_fixture= 1.100
V_fixture_min= 1.060
V_fixture_max= 1.170
|time   V(typ)   V(min)   V(max)
0s        758.6mV    744.6mV    823.3mV
145ps     759.3mV    745mV      821.8mV
204ps     760.8mV    744.4mV    1.037V
265ps     977.4mV    729.3mV    1.131V
282ps     1.012V     755.8mV    1.14V
329ps     1.066V     921.5mV    1.156V
376ps     1.085V     1.004V     1.165V
456ps     1.095V     1.048V     1.169V
646ps     1.1V       1.059V     1.17V
3ns       1.1V       1.06V      1.17V
[Rising Waveform]
R_fixture= 50.000
V_fixture= 0.0
V_fixture_min= 0.0
V_fixture_max= 0.0
|time   V(typ)   V(min)   V(max)
0s        3.732uV    7.145uV    882.6nV
152ps     -66.16uV   29.06uV    8.423mV
191ps     580.7uV    -180.5nV   264.6mV
218ps     13.56mV    17.95uV    359.6mV
265ps     261.3mV    722.7uV    403.3mV
300ps     334.1mV    20.92mV    345.6mV
370ps     360mV      289.4mV    321.1mV
486ps     302.7mV    336.5mV    319.2mV
581ps     302.1mV    295.3mV    319.2mV
3ns       302.1mV    295.1mV    319.2mV
[Falling Waveform]
R_fixture= 50.000
V_fixture= 1.100
V_fixture_min= 1.060
V_fixture_max= 1.170
|time   V(typ)   V(min)   V(max)
0s        1.1V       1.06V      1.17V
158ps     1.1V       1.06V      1.165V
225ps     1.091V     1.06V      830.6mV
270ps     894.2mV    1.059V     727.1mV
318ps     743.8mV    1.043V     782.5mV
362ps     685.9mV    900.5mV    806.6mV
420ps     726.3mV    749.5mV    818mV
495ps     751.4mV    682.3mV    822.1mV
705ps     758.5mV    743mV      823.3mV
3ns       758.6mV    744.6mV    823.3mV
[Falling Waveform]
R_fixture= 50.000
V_fixture= 0.0
V_fixture_min= 0.0
V_fixture_max= 0.0
|time   V(typ)   V(min)   V(max)
0s        302.1mV    295.1mV    319.2mV
146ps     301.6mV    294.7mV    326.2mV
199ps     312.1mV    295.3mV    78.48mV
214ps     274.2mV    298.8mV    47.69mV
257ps     82.42mV    313mV      11.63mV
291ps     29.41mV    232.4mV    592uV
330ps     9.557mV    99.49mV    80.23uV
358ps     4.155mV    44.67mV    54.21uV
465ps     -167.5uV   2.956mV    3.716uV
3ns       849.1nV    7.032uV    641.7nV
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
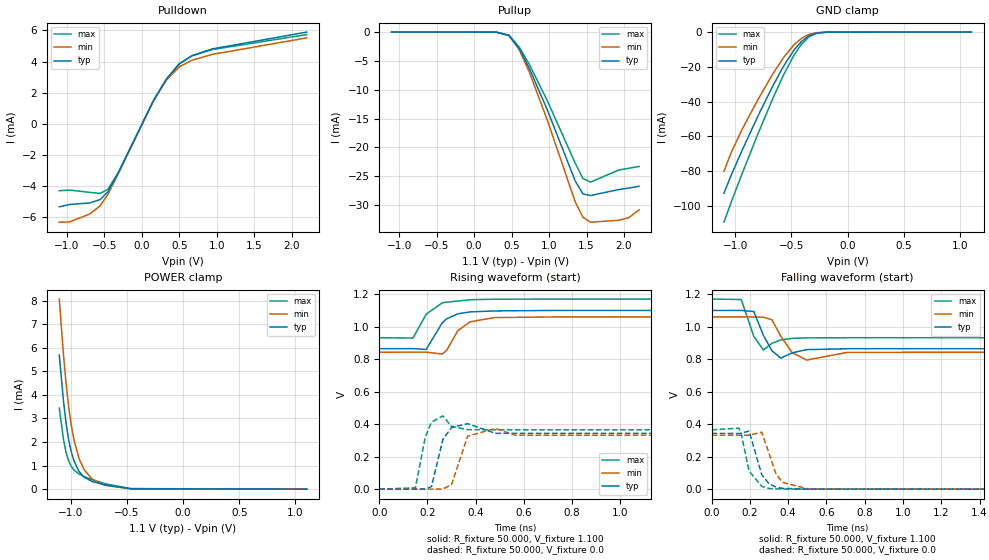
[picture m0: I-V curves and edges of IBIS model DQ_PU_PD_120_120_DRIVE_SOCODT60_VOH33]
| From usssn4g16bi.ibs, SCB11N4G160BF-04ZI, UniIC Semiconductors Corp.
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|   Model DQ_PU_PD_120_120_DRIVE_SOCODT60_VOH33
[Model] DQ_PU_PD_120_120_DRIVE_SOCODT60_VOH33
Model_type I/O
Polarity   Inverting
Vinl =  98.000mV
Vinh =  0.268V
Vmeas =  0.183V
Rref =  50.000
Vref =  0.183V
C_comp   1.020pF   1.010pF   1.030pF
[Model Spec]
Vinh   0.268V   0.262V   0.280V
Vinl   98.000mV   92.000mV   0.110V
Vmeas   0.183V   0.177V   0.195V
Vref   0.183V   0.177V   0.195V
Rref   50.000   NA   NA
[Temperature Range]   25.000   85.000   -40.000
[Voltage Range]   1.100V   1.060V   1.170V
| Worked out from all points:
|   slope of the pulldown table from 0 to 0.165 V, typ, clamps not added: 105 ohm
|   GND clamp passes 1 mA (typ) near -0.30 V on its own axis
|   POWER clamp passes 1 mA (typ) near -0.95 V on its own axis
|   rising waveform, R_fixture 50.000, V_fixture 1.100: 20-80 % time 67.2ps typ, 66.6ps min, 66.7ps max; typ from 0.864 V to 1.1 V
|   rising waveform, R_fixture 50.000, V_fixture 0.0: 20-80 % time 29ps typ, 35.8ps min, 23.6ps max; typ from 0 V to 0.343 V
|   falling waveform, R_fixture 50.000, V_fixture 1.100: 20-80 % time 45.5ps typ, 57.6ps min, 35.6ps max; typ from 1.1 V to 0.864 V
|   falling waveform, R_fixture 50.000, V_fixture 0.0: 20-80 % time 51.8ps typ, 60.7ps min, 48.8ps max; typ from 0.343 V to 0 V
[Pulldown]
|Voltage   I(typ)   I(min)   I(max)
-1.1V     -5.34mA    -6.324mA   -4.302mA
-964mV    -5.187mA   -6.308mA   -4.26mA
-692mV    -5.084mA   -5.795mA   -4.408mA
-556mV    -4.87mA    -5.274mA   -4.475mA
-454mV    -4.386mA   -4.558mA   -4.222mA
-318mV    -3.209mA   -3.256mA   -3.18mA
158mV     1.503mA    1.489mA    1.509mA
328mV     2.865mA    2.797mA    2.867mA
498mV     3.844mA    3.653mA    3.837mA
668mV     4.377mA    4.078mA    4.359mA
940mV     4.811mA    4.458mA    4.768mA
2.2V      5.891mA    5.519mA    5.73mA
[Pullup]
|Voltage   I(typ)   I(min)   I(max)
-1.1V     2.1nA      10.33nA    0A
296mV     -11.79uA   -14.12uA   -6.562uA
466mV     -619.2uA   -608.2uA   -516.4uA
602mV     -2.903mA   -3.06mA    -2.598mA
738mV     -6.341mA   -6.984mA   -5.639mA
976mV     -13.49mA   -15.26mA   -11.89mA
1.35V     -25.87mA   -29.51mA   -22.79mA
1.452V    -28.09mA   -32.14mA   -25.42mA
1.554V    -28.36mA   -32.99mA   -26.03mA
1.928V    -27.33mA   -32.66mA   -23.94mA
2.064V    -27.06mA   -32.19mA   -23.63mA
2.2V      -26.76mA   -30.87mA   -23.32mA
[GND_clamp]
|Voltage   I(typ)   I(min)   I(max)
-1.1V     -92.78mA   -80.14mA   -109.5mA
-1.031V   -81.73mA   -68.77mA   -97.17mA
-939mV    -68.18mA   -56.07mA   -81.64mA
-801mV    -48.85mA   -39.25mA   -59.15mA
-663mV    -30.71mA   -23.84mA   -37.89mA
-571mV    -19.76mA   -14.75mA   -24.85mA
-479mV    -10.5mA    -7.415mA   -13.5mA
-410mV    -5.313mA   -3.546mA   -6.916mA
-341mV    -2.007mA   -1.262mA   -2.59mA
-272mV    -506.9uA   -323.5uA   -609.8uA
-180mV    -45.65uA   -36.06uA   -43.55uA
1.1V      0A         0A         0A
[POWER_clamp]
|Voltage   I(typ)   I(min)   I(max)
-1.1V     5.691mA    8.066mA    3.44mA
-1.062V   3.709mA    5.665mA    2.092mA
-1.039V   2.781mA    4.457mA    1.546mA
-1.016V   2.086mA    3.48mA     1.193mA
-993mV    1.578mA    2.707mA    966.5uA
-970mV    1.21mA     2.107mA    818.5uA
-924mV    750.8uA    1.296mA    641.3uA
-878mV    507uA      821.4uA    530.2uA
-809mV    327.4uA    430uA      403.3uA
-694mV    178.4uA    161uA      233uA
-464mV    19.89uA    15.19uA    23.61uA
1.1V      0A         0A         0A
[Ramp]
| variable   typ   min   max
dV/dt_r   0.206/29.194p   0.200/35.854p   0.219/23.889p
dV/dt_f   0.141/45.638p   0.130/57.596p   0.143/35.657p
R_load = 50.000
[Rising Waveform]
R_fixture= 50.000
V_fixture= 1.100
V_fixture_min= 1.060
V_fixture_max= 1.170
|time   V(typ)   V(min)   V(max)
0s        864.4mV    842.9mV    932.1mV
140ps     865mV      843.2mV    930mV
195ps     859.9mV    843.3mV    1.077V
262ps     1.025V     831.6mV    1.147V
281ps     1.049V     856.5mV    1.151V
326ps     1.079V     974.8mV    1.158V
377ps     1.091V     1.03V      1.166V
478ps     1.097V     1.056V     1.169V
728ps     1.1V       1.06V      1.17V
3ns       1.1V       1.06V      1.17V
[Rising Waveform]
R_fixture= 50.000
V_fixture= 0.0
V_fixture_min= 0.0
V_fixture_max= 0.0
|time   V(typ)   V(min)   V(max)
0s        4.356uV    8.339uV    1.031uV
150ps     -151.9uV   52.57uV    7.857mV
191ps     456.3uV    -15.43uV   319.7mV
217ps     15.74mV    -205.7uV   412.2mV
264ps     305.6mV    779.7uV    451mV
300ps     379.5mV    27.04mV    386.5mV
367ps     403mV      325.6mV    366.3mV
482ps     343.5mV    373.3mV    365.2mV
565ps     343.2mV    331.7mV    365.2mV
3ns       343.2mV    332.5mV    365.2mV
[Falling Waveform]
R_fixture= 50.000
V_fixture= 1.100
V_fixture_min= 1.060
V_fixture_max= 1.170
|time   V(typ)   V(min)   V(max)
0s        1.1V       1.06V      1.17V
155ps     1.1V       1.06V      1.167V
221ps     1.093V     1.06V      939.5mV
271ps     946mV      1.058V     856.6mV
315ps     852.3mV    1.043V     897.6mV
362ps     806.5mV    940.8mV    918.8mV
421ps     839mV      840.5mV    928.1mV
497ps     858.9mV    794.8mV    931.2mV
711ps     864.3mV    842mV      932.1mV
3ns       864.4mV    842.9mV    932.1mV
[Falling Waveform]
R_fixture= 50.000
V_fixture= 0.0
V_fixture_min= 0.0
V_fixture_max= 0.0
|time   V(typ)   V(min)   V(max)
0s        343.2mV    332.5mV    365.2mV
143ps     342.5mV    332.1mV    375.5mV
155ps     344.6mV    331.7mV    340.3mV
196ps     357.9mV    332.3mV    111.8mV
262ps     89.06mV    350.6mV    17.47mV
300ps     33.38mV    221.7mV    4.368mV
334ps     14.3mV     100.4mV    1.867mV
369ps     5.356mV    42.29mV    767.3uV
507ps     97.42uV    1.198mV    22.75uV
3ns       4.356uV    8.297uV    1.056uV
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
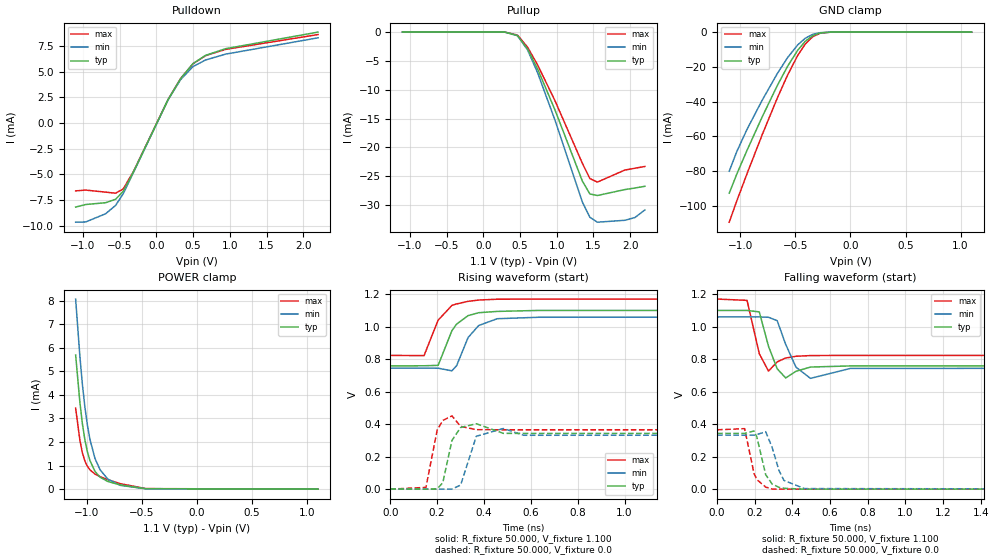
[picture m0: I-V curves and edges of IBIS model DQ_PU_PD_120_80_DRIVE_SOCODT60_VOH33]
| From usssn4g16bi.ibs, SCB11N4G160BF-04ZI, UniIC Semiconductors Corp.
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|   Model DQ_PU_PD_120_80_DRIVE_SOCODT60_VOH33
[Model] DQ_PU_PD_120_80_DRIVE_SOCODT60_VOH33
Model_type I/O
Polarity   Inverting
Vinl =  98.000mV
Vinh =  0.268V
Vmeas =  0.183V
Rref =  50.000
Vref =  0.183V
C_comp   1.020pF   1.010pF   1.030pF
[Model Spec]
Vinh   0.268V   0.262V   0.280V
Vinl   98.000mV   92.000mV   0.110V
Vmeas   0.183V   0.177V   0.195V
Vref   0.183V   0.177V   0.195V
Rref   50.000   NA   NA
[Temperature Range]   25.000   85.000   -40.000
[Voltage Range]   1.100V   1.060V   1.170V
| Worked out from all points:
|   slope of the pulldown table from 0 to 0.165 V, typ, clamps not added: 70.2 ohm
|   GND clamp passes 1 mA (typ) near -0.30 V on its own axis
|   POWER clamp passes 1 mA (typ) near -0.95 V on its own axis
|   rising waveform, R_fixture 50.000, V_fixture 1.100: 20-80 % time 70.9ps typ, 71.5ps min, 69.3ps max; typ from 0.759 V to 1.1 V
|   rising waveform, R_fixture 50.000, V_fixture 0.0: 20-80 % time 29ps typ, 35.6ps min, 23.7ps max; typ from 0 V to 0.343 V
|   falling waveform, R_fixture 50.000, V_fixture 1.100: 20-80 % time 45ps typ, 56.7ps min, 35.7ps max; typ from 1.1 V to 0.759 V
|   falling waveform, R_fixture 50.000, V_fixture 0.0: 20-80 % time 45.7ps typ, 57.6ps min, 42.2ps max; typ from 0.343 V to 0 V
[Pulldown]
|Voltage   I(typ)   I(min)   I(max)
-1.1V     -8.193mA   -9.666mA   -6.618mA
-964mV    -7.945mA   -9.646mA   -6.54mA
-692mV    -7.769mA   -8.844mA   -6.742mA
-556mV    -7.432mA   -8.032mA   -6.841mA
-454mV    -6.673mA   -6.916mA   -6.44mA
-318mV    -4.841mA   -4.906mA   -4.804mA
158mV     2.257mA    2.237mA    2.267mA
328mV     4.302mA    4.2mA      4.305mA
498mV     5.77mA     5.483mA    5.759mA
668mV     6.567mA    6.118mA    6.54mA
940mV     7.217mA    6.688mA    7.152mA
2.2V      8.836mA    8.278mA    8.595mA
[Pullup]
|Voltage   I(typ)   I(min)   I(max)
-1.1V     2.1nA      10.33nA    0A
296mV     -11.79uA   -14.12uA   -6.562uA
466mV     -619.2uA   -608.2uA   -516.4uA
602mV     -2.903mA   -3.06mA    -2.598mA
738mV     -6.341mA   -6.984mA   -5.639mA
976mV     -13.49mA   -15.26mA   -11.89mA
1.35V     -25.87mA   -29.51mA   -22.79mA
1.452V    -28.09mA   -32.14mA   -25.42mA
1.554V    -28.36mA   -32.99mA   -26.03mA
1.928V    -27.33mA   -32.66mA   -23.94mA
2.064V    -27.06mA   -32.19mA   -23.63mA
2.2V      -26.76mA   -30.87mA   -23.32mA
[GND_clamp]
|Voltage   I(typ)   I(min)   I(max)
-1.1V     -92.78mA   -80.14mA   -109.5mA
-1.031V   -81.73mA   -68.77mA   -97.17mA
-939mV    -68.18mA   -56.07mA   -81.64mA
-801mV    -48.85mA   -39.25mA   -59.15mA
-663mV    -30.71mA   -23.84mA   -37.89mA
-571mV    -19.76mA   -14.75mA   -24.85mA
-479mV    -10.5mA    -7.415mA   -13.5mA
-410mV    -5.313mA   -3.546mA   -6.916mA
-341mV    -2.007mA   -1.262mA   -2.59mA
-272mV    -506.9uA   -323.5uA   -609.8uA
-180mV    -45.65uA   -36.06uA   -43.55uA
1.1V      0A         0A         0A
[POWER_clamp]
|Voltage   I(typ)   I(min)   I(max)
-1.1V     5.691mA    8.066mA    3.44mA
-1.062V   3.709mA    5.665mA    2.092mA
-1.039V   2.781mA    4.457mA    1.546mA
-1.016V   2.086mA    3.48mA     1.193mA
-993mV    1.578mA    2.707mA    966.5uA
-970mV    1.21mA     2.107mA    818.5uA
-924mV    750.8uA    1.296mA    641.3uA
-878mV    507uA      821.4uA    530.2uA
-809mV    327.4uA    430uA      403.3uA
-694mV    178.4uA    161uA      233uA
-464mV    19.89uA    15.19uA    23.61uA
1.1V      0A         0A         0A
[Ramp]
| variable   typ   min   max
dV/dt_r   0.206/29.169p   0.200/35.625p   0.219/23.888p
dV/dt_f   0.205/45.182p   0.189/56.571p   0.208/35.744p
R_load = 50.000
[Rising Waveform]
R_fixture= 50.000
V_fixture= 1.100
V_fixture_min= 1.060
V_fixture_max= 1.170
|time   V(typ)   V(min)   V(max)
0s        758.6mV    744.6mV    823.3mV
144ps     759.4mV    744.9mV    821.8mV
204ps     762mV      744.4mV    1.04V
263ps     975.8mV    728.3mV    1.131V
283ps     1.016V     760.3mV    1.14V
332ps     1.068V     933.4mV    1.156V
377ps     1.086V     1.007V     1.164V
456ps     1.094V     1.049V     1.169V
633ps     1.1V       1.058V     1.17V
3ns       1.1V       1.06V      1.17V
[Rising Waveform]
R_fixture= 50.000
V_fixture= 0.0
V_fixture_min= 0.0
V_fixture_max= 0.0
|time   V(typ)   V(min)   V(max)
0s        3.732uV    7.145uV    882.6nV
152ps     -136.6uV   37.22uV    10.85mV
200ps     2.117mV    -68.66uV   364.1mV
224ps     39.68mV    -90.79uV   422.5mV
263ps     299.5mV    666.3uV    451.1mV
300ps     379.5mV    24.71mV    386.5mV
367ps     402.7mV    325.5mV    366.3mV
482ps     343.5mV    373.3mV    365.2mV
569ps     343.2mV    331.6mV    365.2mV
3ns       343.2mV    332.5mV    365.2mV
[Falling Waveform]
R_fixture= 50.000
V_fixture= 1.100
V_fixture_min= 1.060
V_fixture_max= 1.170
|time   V(typ)   V(min)   V(max)
0s        1.1V       1.06V      1.17V
159ps     1.1V       1.06V      1.162V
224ps     1.091V     1.06V      833.6mV
273ps     879mV      1.058V     726.6mV
319ps     741.2mV    1.037V     783.3mV
364ps     684.5mV    891.6mV    807.2mV
419ps     725.4mV    750.6mV    817.9mV
496ps     751.5mV    681.9mV    822.2mV
708ps     758.5mV    743.1mV    823.3mV
3ns       758.6mV    744.6mV    823.3mV
[Falling Waveform]
R_fixture= 50.000
V_fixture= 0.0
V_fixture_min= 0.0
V_fixture_max= 0.0
|time   V(typ)   V(min)   V(max)
0s        343.2mV    332.5mV    365.2mV
146ps     342.8mV    332mV      372.4mV
196ps     358.1mV    332.3mV    97.18mV
211ps     321.5mV    335.8mV    58.93mV
258ps     88.98mV    353.7mV    12.53mV
292ps     31.65mV    257.3mV    937uV
329ps     10.95mV    113.4mV    233.2uV
355ps     5.157mV    53.65mV    128.3uV
464ps     -146.8uV   3.317mV    6.532uV
3ns       3.393uV    6.943uV    769.7nV
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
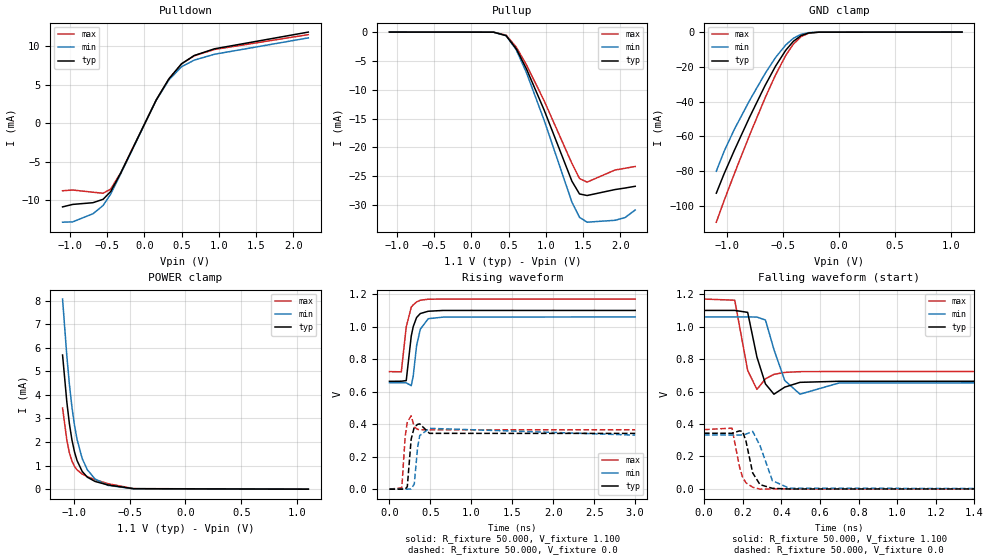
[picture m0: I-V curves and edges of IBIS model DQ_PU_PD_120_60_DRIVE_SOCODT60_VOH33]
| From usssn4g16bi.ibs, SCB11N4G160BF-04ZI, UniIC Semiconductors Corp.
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|   Model DQ_PU_PD_120_60_DRIVE_SOCODT60_VOH33
[Model] DQ_PU_PD_120_60_DRIVE_SOCODT60_VOH33
Model_type I/O
Polarity   Inverting
Vinl =  98.000mV
Vinh =  0.268V
Vmeas =  0.183V
Rref =  50.000
Vref =  0.183V
C_comp   1.020pF   1.010pF   1.030pF
[Model Spec]
Vinh   0.268V   0.262V   0.280V
Vinl   98.000mV   92.000mV   0.110V
Vmeas   0.183V   0.177V   0.195V
Vref   0.183V   0.177V   0.195V
Rref   50.000   NA   NA
[Temperature Range]   25.000   85.000   -40.000
[Voltage Range]   1.100V   1.060V   1.170V
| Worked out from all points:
|   slope of the pulldown table from 0 to 0.165 V, typ, clamps not added: 52.7 ohm
|   GND clamp passes 1 mA (typ) near -0.30 V on its own axis
|   POWER clamp passes 1 mA (typ) near -0.95 V on its own axis
|   rising waveform, R_fixture 50.000, V_fixture 1.100: 20-80 % time 73.2ps typ, 74.6ps min, 71ps max; typ from 0.663 V to 1.1 V
|   rising waveform, R_fixture 50.000, V_fixture 0.0: 20-80 % time 28.8ps typ, 35.5ps min, 23.6ps max; typ from 0 V to 0.343 V
|   falling waveform, R_fixture 50.000, V_fixture 1.100: 20-80 % time 44.2ps typ, 55.4ps min, 35.2ps max; typ from 1.1 V to 0.663 V
|   falling waveform, R_fixture 50.000, V_fixture 0.0: 20-80 % time 41ps typ, 55.4ps min, 36.9ps max; typ from 0.343 V to 0 V
[Pulldown]
|Voltage   I(typ)   I(min)   I(max)
-1.1V     -10.83mA   -12.81mA   -8.746mA
-964mV    -10.51mA   -12.77mA   -8.65mA
-692mV    -10.29mA   -11.72mA   -8.932mA
-556mV    -9.849mA   -10.65mA   -9.063mA
-454mV    -8.849mA   -9.178mA   -8.534mA
-318mV    -6.436mA   -6.525mA   -6.383mA
158mV     3.005mA    2.979mA    3.019mA
328mV     5.729mA    5.594mA    5.734mA
498mV     7.686mA    7.305mA    7.672mA
668mV     8.751mA    8.153mA    8.715mA
940mV     9.618mA    8.913mA    9.532mA
2.2V      11.78mA    11.03mA    11.45mA
[Pullup]
|Voltage   I(typ)   I(min)   I(max)
-1.1V     2.1nA      10.33nA    0A
296mV     -11.79uA   -14.12uA   -6.562uA
466mV     -619.2uA   -608.2uA   -516.4uA
602mV     -2.903mA   -3.06mA    -2.598mA
738mV     -6.341mA   -6.984mA   -5.639mA
976mV     -13.49mA   -15.26mA   -11.89mA
1.35V     -25.87mA   -29.51mA   -22.79mA
1.452V    -28.09mA   -32.14mA   -25.42mA
1.554V    -28.36mA   -32.99mA   -26.03mA
1.928V    -27.33mA   -32.66mA   -23.94mA
2.064V    -27.06mA   -32.19mA   -23.63mA
2.2V      -26.76mA   -30.87mA   -23.32mA
[GND_clamp]
|Voltage   I(typ)   I(min)   I(max)
-1.1V     -92.78mA   -80.14mA   -109.5mA
-1.031V   -81.73mA   -68.77mA   -97.17mA
-939mV    -68.18mA   -56.07mA   -81.64mA
-801mV    -48.85mA   -39.25mA   -59.15mA
-663mV    -30.71mA   -23.84mA   -37.89mA
-571mV    -19.76mA   -14.75mA   -24.85mA
-479mV    -10.5mA    -7.415mA   -13.5mA
-410mV    -5.313mA   -3.546mA   -6.916mA
-341mV    -2.007mA   -1.262mA   -2.59mA
-272mV    -506.9uA   -323.5uA   -609.8uA
-180mV    -45.65uA   -36.06uA   -43.55uA
1.1V      0A         0A         0A
[POWER_clamp]
|Voltage   I(typ)   I(min)   I(max)
-1.1V     5.691mA    8.066mA    3.44mA
-1.062V   3.709mA    5.665mA    2.092mA
-1.039V   2.781mA    4.457mA    1.546mA
-1.016V   2.086mA    3.48mA     1.193mA
-993mV    1.578mA    2.707mA    966.5uA
-970mV    1.21mA     2.107mA    818.5uA
-924mV    750.8uA    1.296mA    641.3uA
-878mV    507uA      821.4uA    530.2uA
-809mV    327.4uA    430uA      403.3uA
-694mV    178.4uA    161uA      233uA
-464mV    19.89uA    15.19uA    23.61uA
1.1V      0A         0A         0A
[Ramp]
| variable   typ   min   max
dV/dt_r   0.206/28.903p   0.200/35.525p   0.219/23.818p
dV/dt_f   0.262/44.222p   0.243/55.565p   0.268/35.232p
R_load = 50.000
[Rising Waveform]
R_fixture= 50.000
V_fixture= 1.100
V_fixture_min= 1.060
V_fixture_max= 1.170
|time   V(typ)   V(min)   V(max)
0s        663.5mV    654.8mV    723.5mV
145ps     664.4mV    655.2mV    722.2mV
205ps     668mV      654.6mV    998.2mV
266ps     941.4mV    637.1mV    1.12V
290ps     1V         694.7mV    1.134V
331ps     1.056V     881.9mV    1.152V
377ps     1.081V     984.6mV    1.163V
473ps     1.095V     1.049V     1.169V
657ps     1.1V       1.059V     1.17V
3ns       1.1V       1.06V      1.17V
[Rising Waveform]
R_fixture= 50.000
V_fixture= 0.0
V_fixture_min= 0.0
V_fixture_max= 0.0
|time   V(typ)   V(min)   V(max)
0s        3.262uV    6.246uV    771.1nV
151ps     -64.66uV   34.45uV    8.309mV
192ps     781.6uV    2.353uV    323.2mV
218ps     15.18mV    38.04uV    413.5mV
265ps     307.4mV    831.8uV    451.1mV
303ps     381.6mV    31.98mV    383.3mV
344ps     398.8mV    257.2mV    368mV
370ps     401.7mV    330mV      366.1mV
489ps     343.4mV    374.3mV    365.2mV
3ns       343.2mV    332.5mV    365.2mV
[Falling Waveform]
R_fixture= 50.000
V_fixture= 1.100
V_fixture_min= 1.060
V_fixture_max= 1.170
|time   V(typ)   V(min)   V(max)
0s        1.1V       1.06V      1.17V
159ps     1.1V       1.06V      1.163V
226ps     1.088V     1.06V      730mV
274ps     812.4mV    1.059V     613.3mV
318ps     647.2mV    1.041V     678.4mV
362ps     583.6mV    858.8mV    705.9mV
418ps     627.2mV    668mV      718mV
497ps     656.7mV    583.7mV    722.5mV
700ps     663.4mV    653mV      723.5mV
3ns       663.5mV    654.8mV    723.5mV
[Falling Waveform]
R_fixture= 50.000
V_fixture= 0.0
V_fixture_min= 0.0
V_fixture_max= 0.0
|time   V(typ)   V(min)   V(max)
0s        343.2mV    332.5mV    365.2mV
145ps     342.6mV    332mV      374.4mV
183ps     357.3mV    331.4mV    138.5mV
199ps     355.3mV    332.7mV    74.12mV
217ps     295.5mV    337.8mV    37.22mV
252ps     98.4mV     354.3mV    10.16mV
290ps     26.21mV    266.8mV    -1.745mV
354ps     3.444mV    50.32mV    -262.3uV
442ps     -680.7uV   4.06mV     -10.54uV
3ns       3.144uV    4.881uV    517.3nV
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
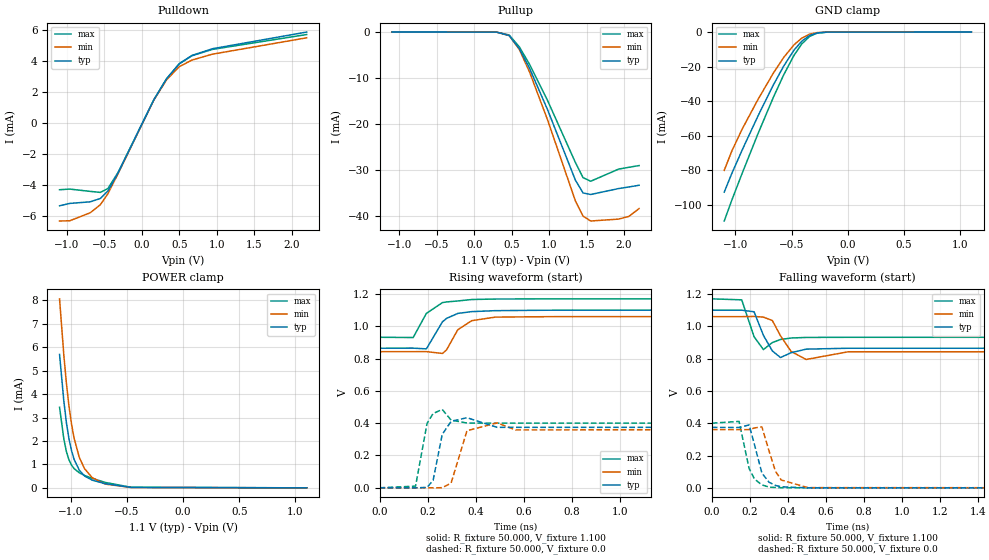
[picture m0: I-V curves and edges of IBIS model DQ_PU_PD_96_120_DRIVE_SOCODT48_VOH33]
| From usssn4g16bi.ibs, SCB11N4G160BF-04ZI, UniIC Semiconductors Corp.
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|   Model DQ_PU_PD_96_120_DRIVE_SOCODT48_VOH33
[Model] DQ_PU_PD_96_120_DRIVE_SOCODT48_VOH33
Model_type I/O
Polarity   Inverting
Vinl =  98.000mV
Vinh =  0.268V
Vmeas =  0.183V
Rref =  50.000
Vref =  0.183V
C_comp   1.020pF   1.010pF   1.030pF
[Model Spec]
Vinh   0.268V   0.262V   0.280V
Vinl   98.000mV   92.000mV   0.110V
Vmeas   0.183V   0.177V   0.195V
Vref   0.183V   0.177V   0.195V
Rref   50.000   NA   NA
[Temperature Range]   25.000   85.000   -40.000
[Voltage Range]   1.100V   1.060V   1.170V
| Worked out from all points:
|   slope of the pulldown table from 0 to 0.165 V, typ, clamps not added: 105 ohm
|   GND clamp passes 1 mA (typ) near -0.30 V on its own axis
|   POWER clamp passes 1 mA (typ) near -0.95 V on its own axis
|   rising waveform, R_fixture 50.000, V_fixture 1.100: 20-80 % time 65.8ps typ, 64.2ps min, 65.9ps max; typ from 0.864 V to 1.1 V
|   rising waveform, R_fixture 50.000, V_fixture 0.0: 20-80 % time 27.9ps typ, 34.9ps min, 22.7ps max; typ from 0 V to 0.374 V
|   falling waveform, R_fixture 50.000, V_fixture 1.100: 20-80 % time 45.9ps typ, 58.6ps min, 35.7ps max; typ from 1.1 V to 0.864 V
|   falling waveform, R_fixture 50.000, V_fixture 0.0: 20-80 % time 51.8ps typ, 60.7ps min, 48.7ps max; typ from 0.374 V to 0 V
[Pulldown]
|Voltage   I(typ)   I(min)   I(max)
-1.1V     -5.34mA    -6.324mA   -4.302mA
-964mV    -5.187mA   -6.308mA   -4.26mA
-692mV    -5.084mA   -5.795mA   -4.408mA
-556mV    -4.87mA    -5.274mA   -4.475mA
-454mV    -4.386mA   -4.558mA   -4.222mA
-318mV    -3.209mA   -3.256mA   -3.18mA
158mV     1.503mA    1.489mA    1.509mA
328mV     2.865mA    2.797mA    2.867mA
498mV     3.844mA    3.653mA    3.837mA
668mV     4.377mA    4.078mA    4.359mA
940mV     4.811mA    4.458mA    4.768mA
2.2V      5.891mA    5.519mA    5.73mA
[Pullup]
|Voltage   I(typ)   I(min)   I(max)
-1.1V     2.6nA      12.94nA    0A
296mV     -14.74uA   -17.65uA   -8.203uA
466mV     -773.5uA   -759.8uA   -645.2uA
602mV     -3.625mA   -3.82mA    -3.244mA
738mV     -7.914mA   -8.716mA   -7.039mA
976mV     -16.84mA   -19.04mA   -14.84mA
1.35V     -32.28mA   -36.82mA   -28.44mA
1.452V    -35.08mA   -40.12mA   -31.74mA
1.554V    -35.42mA   -41.2mA    -32.53mA
1.928V    -34.12mA   -40.78mA   -29.88mA
2.064V    -33.78mA   -40.2mA    -29.49mA
2.2V      -33.41mA   -38.49mA   -29.11mA
[GND_clamp]
|Voltage   I(typ)   I(min)   I(max)
-1.1V     -92.78mA   -80.14mA   -109.5mA
-1.031V   -81.73mA   -68.77mA   -97.17mA
-939mV    -68.18mA   -56.07mA   -81.64mA
-801mV    -48.85mA   -39.25mA   -59.15mA
-663mV    -30.71mA   -23.84mA   -37.89mA
-571mV    -19.76mA   -14.75mA   -24.85mA
-479mV    -10.5mA    -7.415mA   -13.5mA
-410mV    -5.313mA   -3.546mA   -6.916mA
-341mV    -2.007mA   -1.262mA   -2.59mA
-272mV    -506.9uA   -323.5uA   -609.8uA
-180mV    -45.65uA   -36.06uA   -43.55uA
1.1V      0A         0A         0A
[POWER_clamp]
|Voltage   I(typ)   I(min)   I(max)
-1.1V     5.691mA    8.066mA    3.44mA
-1.062V   3.709mA    5.665mA    2.092mA
-1.039V   2.781mA    4.457mA    1.546mA
-1.016V   2.086mA    3.48mA     1.193mA
-993mV    1.578mA    2.707mA    966.5uA
-970mV    1.21mA     2.107mA    818.5uA
-924mV    750.8uA    1.296mA    641.3uA
-878mV    507uA      821.4uA    530.2uA
-809mV    327.4uA    430uA      403.3uA
-694mV    178.4uA    161uA      233uA
-464mV    19.89uA    15.19uA    23.61uA
1.1V      0A         0A         0A
[Ramp]
| variable   typ   min   max
dV/dt_r   0.225/28.071p   0.216/35.004p   0.240/22.829p
dV/dt_f   0.141/46.030p   0.130/58.595p   0.143/35.833p
R_load = 50.000
[Rising Waveform]
R_fixture= 50.000
V_fixture= 1.100
V_fixture_min= 1.060
V_fixture_max= 1.170
|time   V(typ)   V(min)   V(max)
0s        864.4mV    842.9mV    932.1mV
140ps     864.9mV    843.2mV    930.6mV
195ps     860.3mV    843.3mV    1.08V
262ps     1.028V     832mV      1.147V
279ps     1.049V     853.9mV    1.151V
326ps     1.08V      979mV      1.157V
384ps     1.091V     1.035V     1.166V
482ps     1.097V     1.057V     1.169V
729ps     1.1V       1.06V      1.17V
3ns       1.1V       1.06V      1.17V
[Rising Waveform]
R_fixture= 50.000
V_fixture= 0.0
V_fixture_min= 0.0
V_fixture_max= 0.0
|time   V(typ)   V(min)   V(max)
0s        4.356uV    8.339uV    1.031uV
150ps     -230.3uV   62.17uV    10.2mV
198ps     2.53mV     -151.5uV   399.7mV
223ps     45.96mV    -374.5uV   459.9mV
261ps     330.7mV    619.5uV    485.2mV
298ps     411.2mV    29.2mV     419.3mV
364ps     434mV      353.5mV    400.9mV
490ps     374.4mV    401.8mV    400.4mV
566ps     374.4mV    358.5mV    400.4mV
3ns       374.4mV    360.6mV    400.4mV
[Falling Waveform]
R_fixture= 50.000
V_fixture= 1.100
V_fixture_min= 1.060
V_fixture_max= 1.170
|time   V(typ)   V(min)   V(max)
0s        1.1V       1.06V      1.17V
157ps     1.1V       1.06V      1.164V
222ps     1.09V      1.061V     935.8mV
271ps     944.5mV    1.057V     856mV
318ps     847.6mV    1.036V     899.5mV
361ps     806.8mV    941.4mV    918.5mV
417ps     836.7mV    844.2mV    927.7mV
496ps     858.7mV    794.7mV    931.2mV
715ps     864.3mV    842mV      932.1mV
3ns       864.4mV    842.9mV    932.1mV
[Falling Waveform]
R_fixture= 50.000
V_fixture= 0.0
V_fixture_min= 0.0
V_fixture_max= 0.0
|time   V(typ)   V(min)   V(max)
0s        374.4mV    360.6mV    400.4mV
143ps     373.6mV    360.1mV    411.3mV
196ps     389.5mV    360.6mV    119.8mV
224ps     267.9mV    370.7mV    54.84mV
263ps     91.73mV    377.9mV    18.19mV
301ps     34.48mV    227.4mV    4.701mV
335ps     14.76mV    101.5mV    2.013mV
365ps     6.56mV     48.46mV    940.7uV
505ps     115.6uV    1.428mV    26.41uV
3ns       4.347uV    8.323uV    1.092uV
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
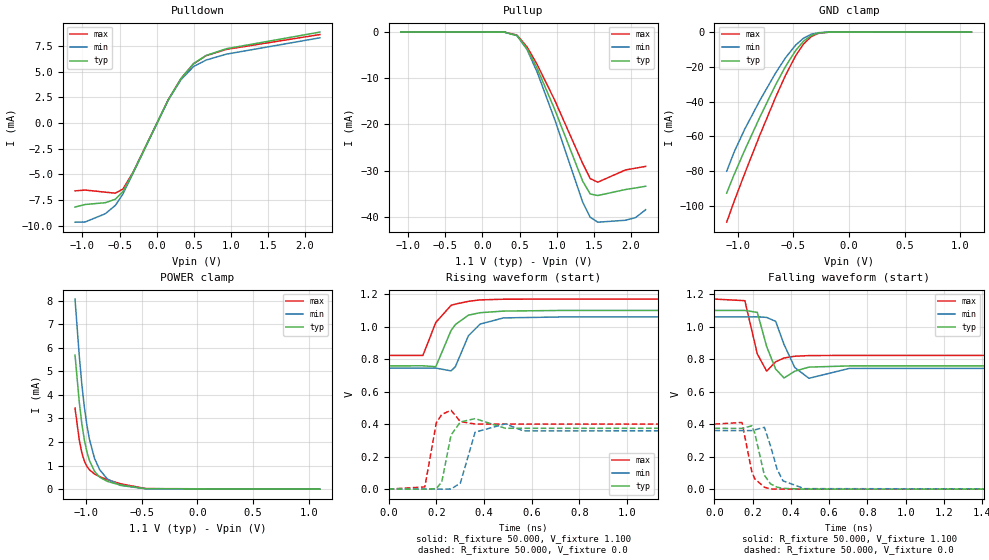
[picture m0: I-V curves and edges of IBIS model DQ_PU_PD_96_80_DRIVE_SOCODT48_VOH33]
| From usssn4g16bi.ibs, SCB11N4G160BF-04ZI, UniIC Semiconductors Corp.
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|   Model DQ_PU_PD_96_80_DRIVE_SOCODT48_VOH33
[Model] DQ_PU_PD_96_80_DRIVE_SOCODT48_VOH33
Model_type I/O
Polarity   Inverting
Vinl =  98.000mV
Vinh =  0.268V
Vmeas =  0.183V
Rref =  50.000
Vref =  0.183V
C_comp   1.020pF   1.010pF   1.030pF
[Model Spec]
Vinh   0.268V   0.262V   0.280V
Vinl   98.000mV   92.000mV   0.110V
Vmeas   0.183V   0.177V   0.195V
Vref   0.183V   0.177V   0.195V
Rref   50.000   NA   NA
[Temperature Range]   25.000   85.000   -40.000
[Voltage Range]   1.100V   1.060V   1.170V
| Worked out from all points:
|   slope of the pulldown table from 0 to 0.165 V, typ, clamps not added: 70.2 ohm
|   GND clamp passes 1 mA (typ) near -0.30 V on its own axis
|   POWER clamp passes 1 mA (typ) near -0.95 V on its own axis
|   rising waveform, R_fixture 50.000, V_fixture 1.100: 20-80 % time 70.3ps typ, 70.3ps min, 69ps max; typ from 0.759 V to 1.1 V
|   rising waveform, R_fixture 50.000, V_fixture 0.0: 20-80 % time 27.8ps typ, 34.7ps min, 22.7ps max; typ from 0 V to 0.374 V
|   falling waveform, R_fixture 50.000, V_fixture 1.100: 20-80 % time 45.3ps typ, 57.1ps min, 35.8ps max; typ from 1.1 V to 0.759 V
|   falling waveform, R_fixture 50.000, V_fixture 0.0: 20-80 % time 46.1ps typ, 57.9ps min, 42.2ps max; typ from 0.374 V to 0 V
[Pulldown]
|Voltage   I(typ)   I(min)   I(max)
-1.1V     -8.193mA   -9.666mA   -6.618mA
-964mV    -7.945mA   -9.646mA   -6.54mA
-692mV    -7.769mA   -8.844mA   -6.742mA
-556mV    -7.432mA   -8.032mA   -6.841mA
-454mV    -6.673mA   -6.916mA   -6.44mA
-318mV    -4.841mA   -4.906mA   -4.804mA
158mV     2.257mA    2.237mA    2.267mA
328mV     4.302mA    4.2mA      4.305mA
498mV     5.77mA     5.483mA    5.759mA
668mV     6.567mA    6.118mA    6.54mA
940mV     7.217mA    6.688mA    7.152mA
2.2V      8.836mA    8.278mA    8.595mA
[Pullup]
|Voltage   I(typ)   I(min)   I(max)
-1.1V     2.6nA      12.94nA    0A
296mV     -14.74uA   -17.65uA   -8.203uA
466mV     -773.5uA   -759.8uA   -645.2uA
602mV     -3.625mA   -3.82mA    -3.244mA
738mV     -7.914mA   -8.716mA   -7.039mA
976mV     -16.84mA   -19.04mA   -14.84mA
1.35V     -32.28mA   -36.82mA   -28.44mA
1.452V    -35.08mA   -40.12mA   -31.74mA
1.554V    -35.42mA   -41.2mA    -32.53mA
1.928V    -34.12mA   -40.78mA   -29.88mA
2.064V    -33.78mA   -40.2mA    -29.49mA
2.2V      -33.41mA   -38.49mA   -29.11mA
[GND_clamp]
|Voltage   I(typ)   I(min)   I(max)
-1.1V     -92.78mA   -80.14mA   -109.5mA
-1.031V   -81.73mA   -68.77mA   -97.17mA
-939mV    -68.18mA   -56.07mA   -81.64mA
-801mV    -48.85mA   -39.25mA   -59.15mA
-663mV    -30.71mA   -23.84mA   -37.89mA
-571mV    -19.76mA   -14.75mA   -24.85mA
-479mV    -10.5mA    -7.415mA   -13.5mA
-410mV    -5.313mA   -3.546mA   -6.916mA
-341mV    -2.007mA   -1.262mA   -2.59mA
-272mV    -506.9uA   -323.5uA   -609.8uA
-180mV    -45.65uA   -36.06uA   -43.55uA
1.1V      0A         0A         0A
[POWER_clamp]
|Voltage   I(typ)   I(min)   I(max)
-1.1V     5.691mA    8.066mA    3.44mA
-1.062V   3.709mA    5.665mA    2.092mA
-1.039V   2.781mA    4.457mA    1.546mA
-1.016V   2.086mA    3.48mA     1.193mA
-993mV    1.578mA    2.707mA    966.5uA
-970mV    1.21mA     2.107mA    818.5uA
-924mV    750.8uA    1.296mA    641.3uA
-878mV    507uA      821.4uA    530.2uA
-809mV    327.4uA    430uA      403.3uA
-694mV    178.4uA    161uA      233uA
-464mV    19.89uA    15.19uA    23.61uA
1.1V      0A         0A         0A
[Ramp]
| variable   typ   min   max
dV/dt_r   0.225/27.970p   0.216/34.754p   0.240/22.852p
dV/dt_f   0.205/45.397p   0.189/57.189p   0.208/35.929p
R_load = 50.000
[Rising Waveform]
R_fixture= 50.000
V_fixture= 1.100
V_fixture_min= 1.060
V_fixture_max= 1.170
|time   V(typ)   V(min)   V(max)
0s        758.6mV    744.6mV    823.3mV
144ps     759.3mV    745mV      822.9mV
198ps     753.6mV    745.1mV    1.026V
262ps     976.3mV    728.1mV    1.131V
280ps     1.013V     753.5mV    1.139V
335ps     1.071V     944.5mV    1.156V
384ps     1.086V     1.016V     1.165V
482ps     1.096V     1.054V     1.169V
729ps     1.1V       1.06V      1.17V
3ns       1.1V       1.06V      1.17V
[Rising Waveform]
R_fixture= 50.000
V_fixture= 0.0
V_fixture_min= 0.0
V_fixture_max= 0.0
|time   V(typ)   V(min)   V(max)
0s        3.732uV    7.145uV    882.6nV
152ps     -223.6uV   46.6uV     13.64mV
200ps     3.054mV    -140uV     407.3mV
223ps     43.99mV    -221.4uV   459.8mV
262ps     333.1mV    924.3uV    485.4mV
301ps     413.2mV    36.82mV    415.6mV
363ps     434.1mV    350.6mV    400.9mV
490ps     374.4mV    401.9mV    400.4mV
565ps     374.4mV    358.6mV    400.4mV
3ns       374.4mV    360.6mV    400.4mV
[Falling Waveform]
R_fixture= 50.000
V_fixture= 1.100
V_fixture_min= 1.060
V_fixture_max= 1.170
|time   V(typ)   V(min)   V(max)
0s        1.1V       1.06V      1.17V
159ps     1.1V       1.06V      1.16V
224ps     1.088V     1.061V     832.5mV
273ps     877.6mV    1.057V     726.3mV
320ps     739mV      1.033V     784mV
364ps     684.4mV    890mV      807.2mV
420ps     726mV      748.6mV    818mV
494ps     751.2mV    682.2mV    822.1mV
704ps     758.5mV    743mV      823.3mV
3ns       758.6mV    744.6mV    823.3mV
[Falling Waveform]
R_fixture= 50.000
V_fixture= 0.0
V_fixture_min= 0.0
V_fixture_max= 0.0
|time   V(typ)   V(min)   V(max)
0s        374.4mV    360.6mV    400.4mV
144ps     373.7mV    360mV      410.4mV
196ps     389.8mV    360.6mV    104.3mV
211ps     344.2mV    364.8mV    63.22mV
261ps     85.59mV    380.6mV    11.97mV
293ps     32.51mV    266.2mV    1.134mV
327ps     12.23mV    124.8mV    351.2uV
358ps     4.905mV    51.29mV    162uV
470ps     -104.1uV   3.002mV    7.146uV
3ns       3.469uV    6.929uV    -2.1uV
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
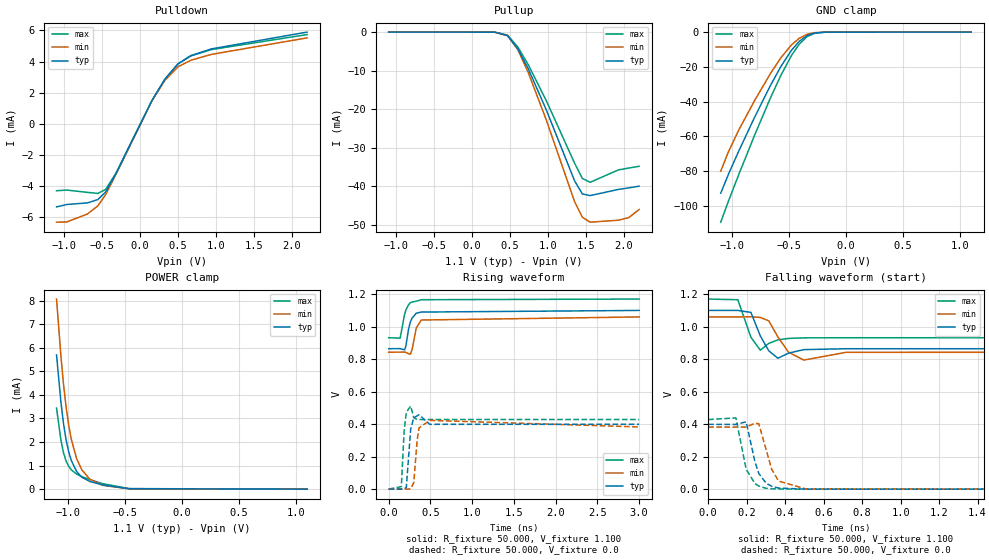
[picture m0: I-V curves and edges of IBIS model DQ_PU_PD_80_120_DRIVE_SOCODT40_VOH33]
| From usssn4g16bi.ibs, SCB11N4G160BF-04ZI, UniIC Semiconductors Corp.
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|   Model DQ_PU_PD_80_120_DRIVE_SOCODT40_VOH33
[Model] DQ_PU_PD_80_120_DRIVE_SOCODT40_VOH33
Model_type I/O
Polarity   Inverting
Vinl =  98.000mV
Vinh =  0.268V
Vmeas =  0.183V
Rref =  50.000
Vref =  0.183V
C_comp   1.020pF   1.010pF   1.030pF
[Model Spec]
Vinh   0.268V   0.262V   0.280V
Vinl   98.000mV   92.000mV   0.110V
Vmeas   0.183V   0.177V   0.195V
Vref   0.183V   0.177V   0.195V
Rref   50.000   NA   NA
[Temperature Range]   25.000   85.000   -40.000
[Voltage Range]   1.100V   1.060V   1.170V
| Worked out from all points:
|   slope of the pulldown table from 0 to 0.165 V, typ, clamps not added: 105 ohm
|   GND clamp passes 1 mA (typ) near -0.30 V on its own axis
|   POWER clamp passes 1 mA (typ) near -0.95 V on its own axis
|   rising waveform, R_fixture 50.000, V_fixture 1.100: 20-80 % time 63.9ps typ, 60.7ps min, 64.7ps max; typ from 0.864 V to 1.1 V
|   rising waveform, R_fixture 50.000, V_fixture 0.0: 20-80 % time 26.9ps typ, 34.1ps min, 21.9ps max; typ from 0 V to 0.399 V
|   falling waveform, R_fixture 50.000, V_fixture 1.100: 20-80 % time 46.1ps typ, 59.6ps min, 35.9ps max; typ from 1.1 V to 0.864 V
|   falling waveform, R_fixture 50.000, V_fixture 0.0: 20-80 % time 51.5ps typ, 59.8ps min, 48.7ps max; typ from 0.399 V to 0 V
[Pulldown]
|Voltage   I(typ)   I(min)   I(max)
-1.1V     -5.34mA    -6.324mA   -4.302mA
-964mV    -5.187mA   -6.308mA   -4.26mA
-692mV    -5.084mA   -5.795mA   -4.408mA
-556mV    -4.87mA    -5.274mA   -4.475mA
-454mV    -4.386mA   -4.558mA   -4.222mA
-318mV    -3.209mA   -3.256mA   -3.18mA
158mV     1.503mA    1.489mA    1.509mA
328mV     2.865mA    2.797mA    2.867mA
498mV     3.844mA    3.653mA    3.837mA
668mV     4.377mA    4.078mA    4.359mA
940mV     4.811mA    4.458mA    4.768mA
2.2V      5.891mA    5.519mA    5.73mA
[Pullup]
|Voltage   I(typ)   I(min)   I(max)
-1.1V     3.1nA      15.54nA    0A
296mV     -17.69uA   -21.17uA   -9.843uA
466mV     -927.4uA   -911uA     -773.6uA
602mV     -4.341mA   -4.574mA   -3.886mA
738mV     -9.474mA   -10.43mA   -8.429mA
976mV     -20.15mA   -22.77mA   -17.76mA
1.35V     -38.63mA   -44.04mA   -34.05mA
1.452V    -42.01mA   -48.04mA   -38mA
1.554V    -42.45mA   -49.35mA   -39mA
1.928V    -40.84mA   -48.83mA   -35.77mA
2.064V    -40.44mA   -48.15mA   -35.29mA
2.2V      -40mA      -46.05mA   -34.84mA
[GND_clamp]
|Voltage   I(typ)   I(min)   I(max)
-1.1V     -92.78mA   -80.14mA   -109.5mA
-1.031V   -81.73mA   -68.77mA   -97.17mA
-939mV    -68.18mA   -56.07mA   -81.64mA
-801mV    -48.85mA   -39.25mA   -59.15mA
-663mV    -30.71mA   -23.84mA   -37.89mA
-571mV    -19.76mA   -14.75mA   -24.85mA
-479mV    -10.5mA    -7.415mA   -13.5mA
-410mV    -5.313mA   -3.546mA   -6.916mA
-341mV    -2.007mA   -1.262mA   -2.59mA
-272mV    -506.9uA   -323.5uA   -609.8uA
-180mV    -45.65uA   -36.06uA   -43.55uA
1.1V      0A         0A         0A
[POWER_clamp]
|Voltage   I(typ)   I(min)   I(max)
-1.1V     5.691mA    8.066mA    3.44mA
-1.062V   3.709mA    5.665mA    2.092mA
-1.039V   2.781mA    4.457mA    1.546mA
-1.016V   2.086mA    3.48mA     1.193mA
-993mV    1.578mA    2.707mA    966.5uA
-970mV    1.21mA     2.107mA    818.5uA
-924mV    750.8uA    1.296mA    641.3uA
-878mV    507uA      821.4uA    530.2uA
-809mV    327.4uA    430uA      403.3uA
-694mV    178.4uA    161uA      233uA
-464mV    19.89uA    15.19uA    23.61uA
1.1V      0A         0A         0A
[Ramp]
| variable   typ   min   max
dV/dt_r   0.239/27.172p   0.230/34.208p   0.257/22.063p
dV/dt_f   0.141/46.256p   0.130/59.627p   0.143/35.919p
R_load = 50.000
[Rising Waveform]
R_fixture= 50.000
V_fixture= 1.100
V_fixture_min= 1.060
V_fixture_max= 1.170
|time   V(typ)   V(min)   V(max)
0s        864.4mV    842.9mV    932.1mV
138ps     865mV      843.2mV    929.4mV
190ps     857.1mV    843.6mV    1.074V
205ps     876.6mV    842.1mV    1.1V
239ps     986.4mV    833.3mV    1.135V
261ps     1.03V      831.1mV    1.148V
280ps     1.052V     857.1mV    1.151V
331ps     1.083V     991.9mV    1.157V
391ps     1.09V      1.041V     1.166V
3ns       1.1V       1.06V      1.17V
[Rising Waveform]
R_fixture= 50.000
V_fixture= 0.0
V_fixture_min= 0.0
V_fixture_max= 0.0
|time   V(typ)   V(min)   V(max)
0s        4.356uV    8.339uV    1.031uV
152ps     -322.8uV   71.13uV    15.33mV
186ps     -231.3uV   23.96uV    359.4mV
212ps     11.4mV     -382.1uV   473.8mV
264ps     370.1mV    1.154mV    511.5mV
301ps     437.8mV    40.39mV    439.7mV
342ps     451.4mV    305.4mV    428.6mV
365ps     457.4mV    377.3mV    428.3mV
492ps     398.9mV    423.1mV    428.3mV
3ns       398.9mV    382.6mV    428.3mV
[Falling Waveform]
R_fixture= 50.000
V_fixture= 1.100
V_fixture_min= 1.060
V_fixture_max= 1.170
|time   V(typ)   V(min)   V(max)
0s        1.1V       1.06V      1.17V
154ps     1.1V       1.06V      1.166V
222ps     1.088V     1.061V     934.7mV
271ps     942.7mV    1.057V     855.6mV
315ps     851mV      1.036V     897.3mV
362ps     806.1mV    937.1mV    918.7mV
418ps     837.2mV    842.5mV    927.8mV
497ps     858.8mV    794.5mV    931.2mV
716ps     864.3mV    842.1mV    932.1mV
3ns       864.4mV    842.9mV    932.1mV
[Falling Waveform]
R_fixture= 50.000
V_fixture= 0.0
V_fixture_min= 0.0
V_fixture_max= 0.0
|time   V(typ)   V(min)   V(max)
0s        398.9mV    382.6mV    428.3mV
144ps     398.2mV    381.9mV    438.7mV
197ps     414.8mV    382.6mV    123.6mV
243ps     168.1mV    405.5mV    34.26mV
263ps     96.85mV    402.6mV    19.26mV
301ps     36.41mV    243.2mV    5.11mV
330ps     17.58mV    122.2mV    2.469mV
366ps     6.719mV    49.78mV    986.6uV
507ps     123.6uV    1.38mV     26.97uV
3ns       4.331uV    8.273uV    1.118uV
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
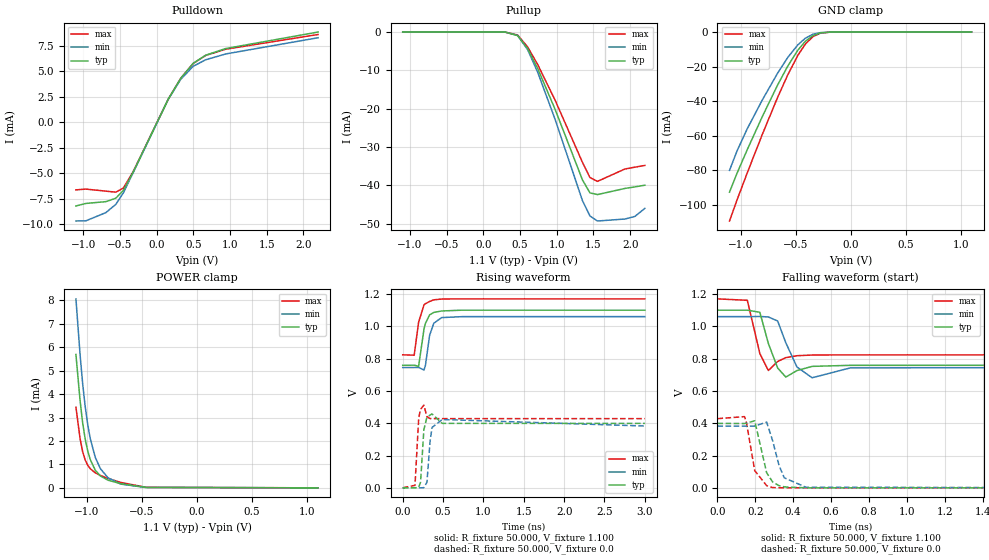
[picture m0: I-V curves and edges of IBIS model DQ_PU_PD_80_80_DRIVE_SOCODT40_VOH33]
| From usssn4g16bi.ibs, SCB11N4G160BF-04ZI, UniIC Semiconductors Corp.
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|   Model DQ_PU_PD_80_80_DRIVE_SOCODT40_VOH33
[Model] DQ_PU_PD_80_80_DRIVE_SOCODT40_VOH33
Model_type I/O
Polarity   Inverting
Vinl =  98.000mV
Vinh =  0.268V
Vmeas =  0.183V
Rref =  50.000
Vref =  0.183V
C_comp   1.020pF   1.010pF   1.030pF
[Model Spec]
Vinh   0.268V   0.262V   0.280V
Vinl   98.000mV   92.000mV   0.110V
Vmeas   0.183V   0.177V   0.195V
Vref   0.183V   0.177V   0.195V
Rref   50.000   NA   NA
[Temperature Range]   25.000   85.000   -40.000
[Voltage Range]   1.100V   1.060V   1.170V
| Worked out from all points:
|   slope of the pulldown table from 0 to 0.165 V, typ, clamps not added: 70.2 ohm
|   GND clamp passes 1 mA (typ) near -0.30 V on its own axis
|   POWER clamp passes 1 mA (typ) near -0.95 V on its own axis
|   rising waveform, R_fixture 50.000, V_fixture 1.100: 20-80 % time 69.3ps typ, 68.4ps min, 68.6ps max; typ from 0.759 V to 1.1 V
|   rising waveform, R_fixture 50.000, V_fixture 0.0: 20-80 % time 26.9ps typ, 33.8ps min, 21.8ps max; typ from 0 V to 0.399 V
|   falling waveform, R_fixture 50.000, V_fixture 1.100: 20-80 % time 45.5ps typ, 57.8ps min, 36ps max; typ from 1.1 V to 0.759 V
|   falling waveform, R_fixture 50.000, V_fixture 0.0: 20-80 % time 45.9ps typ, 57ps min, 42.3ps max; typ from 0.399 V to 0 V
[Pulldown]
|Voltage   I(typ)   I(min)   I(max)
-1.1V     -8.193mA   -9.666mA   -6.618mA
-964mV    -7.945mA   -9.646mA   -6.54mA
-692mV    -7.769mA   -8.844mA   -6.742mA
-556mV    -7.432mA   -8.032mA   -6.841mA
-454mV    -6.673mA   -6.916mA   -6.44mA
-318mV    -4.841mA   -4.906mA   -4.804mA
158mV     2.257mA    2.237mA    2.267mA
328mV     4.302mA    4.2mA      4.305mA
498mV     5.77mA     5.483mA    5.759mA
668mV     6.567mA    6.118mA    6.54mA
940mV     7.217mA    6.688mA    7.152mA
2.2V      8.836mA    8.278mA    8.595mA
[Pullup]
|Voltage   I(typ)   I(min)   I(max)
-1.1V     3.1nA      15.54nA    0A
296mV     -17.69uA   -21.17uA   -9.843uA
466mV     -927.4uA   -911uA     -773.6uA
602mV     -4.341mA   -4.574mA   -3.886mA
738mV     -9.474mA   -10.43mA   -8.429mA
976mV     -20.15mA   -22.77mA   -17.76mA
1.35V     -38.63mA   -44.04mA   -34.05mA
1.452V    -42.01mA   -48.04mA   -38mA
1.554V    -42.45mA   -49.35mA   -39mA
1.928V    -40.84mA   -48.83mA   -35.77mA
2.064V    -40.44mA   -48.15mA   -35.29mA
2.2V      -40mA      -46.05mA   -34.84mA
[GND_clamp]
|Voltage   I(typ)   I(min)   I(max)
-1.1V     -92.78mA   -80.14mA   -109.5mA
-1.031V   -81.73mA   -68.77mA   -97.17mA
-939mV    -68.18mA   -56.07mA   -81.64mA
-801mV    -48.85mA   -39.25mA   -59.15mA
-663mV    -30.71mA   -23.84mA   -37.89mA
-571mV    -19.76mA   -14.75mA   -24.85mA
-479mV    -10.5mA    -7.415mA   -13.5mA
-410mV    -5.313mA   -3.546mA   -6.916mA
-341mV    -2.007mA   -1.262mA   -2.59mA
-272mV    -506.9uA   -323.5uA   -609.8uA
-180mV    -45.65uA   -36.06uA   -43.55uA
1.1V      0A         0A         0A
[POWER_clamp]
|Voltage   I(typ)   I(min)   I(max)
-1.1V     5.691mA    8.066mA    3.44mA
-1.062V   3.709mA    5.665mA    2.092mA
-1.039V   2.781mA    4.457mA    1.546mA
-1.016V   2.086mA    3.48mA     1.193mA
-993mV    1.578mA    2.707mA    966.5uA
-970mV    1.21mA     2.107mA    818.5uA
-924mV    750.8uA    1.296mA    641.3uA
-878mV    507uA      821.4uA    530.2uA
-809mV    327.4uA    430uA      403.3uA
-694mV    178.4uA    161uA      233uA
-464mV    19.89uA    15.19uA    23.61uA
1.1V      0A         0A         0A
[Ramp]
| variable   typ   min   max
dV/dt_r   0.239/27.012p   0.230/33.873p   0.257/22.087p
dV/dt_f   0.205/45.575p   0.189/57.804p   0.208/36.053p
R_load = 50.000
[Rising Waveform]
R_fixture= 50.000
V_fixture= 1.100
V_fixture_min= 1.060
V_fixture_max= 1.170
|time   V(typ)   V(min)   V(max)
0s        758.6mV    744.6mV    823.3mV
142ps     759.4mV    744.9mV    821.3mV
197ps     752.6mV    745.2mV    1.026V
264ps     984.3mV    729.4mV    1.133V
282ps     1.019V     760.3mV    1.14V
333ps     1.071V     944.2mV    1.154V
385ps     1.086V     1.019V     1.164V
482ps     1.095V     1.054V     1.169V
737ps     1.1V       1.06V      1.17V
3ns       1.1V       1.06V      1.17V
[Rising Waveform]
R_fixture= 50.000
V_fixture= 0.0
V_fixture_min= 0.0
V_fixture_max= 0.0
|time   V(typ)   V(min)   V(max)
0s        3.732uV    7.145uV    882.6nV
152ps     -283.2uV   54.38uV    15.01mV
198ps     2.792mV    -145.5uV   431.5mV
221ps     34.78mV    -312.4uV   486.6mV
262ps     359.6mV    779uV      511.3mV
300ps     437.3mV    34.18mV    440.7mV
339ps     450.4mV    288.7mV    428.7mV
363ps     457.4mV    373.3mV    428.4mV
489ps     398.9mV    422.8mV    428.3mV
3ns       398.9mV    382.6mV    428.3mV
[Falling Waveform]
R_fixture= 50.000
V_fixture= 1.100
V_fixture_min= 1.060
V_fixture_max= 1.170
|time   V(typ)   V(min)   V(max)
0s        1.1V       1.06V      1.17V
158ps     1.1V       1.06V      1.161V
224ps     1.087V     1.061V     831.8mV
269ps     893.6mV    1.058V     726.5mV
318ps     742.1mV    1.033V     782.2mV
361ps     685.9mV    898.5mV    806.1mV
420ps     726.1mV    748mV      818mV
500ps     752mV      681.5mV    822.2mV
703ps     758.5mV    743mV      823.3mV
3ns       758.6mV    744.6mV    823.3mV
[Falling Waveform]
R_fixture= 50.000
V_fixture= 0.0
V_fixture_min= 0.0
V_fixture_max= 0.0
|time   V(typ)   V(min)   V(max)
0s        398.9mV    382.6mV    428.3mV
143ps     398.1mV    381.9mV    440.9mV
153ps     400.3mV    381.6mV    405.2mV
197ps     415.2mV    382.6mV    106.9mV
260ps     93.36mV    406.9mV    13.19mV
292ps     35.41mV    289.9mV    1.519mV
326ps     13.25mV    135.8mV    459.4uV
353ps     6.14mV     62.03mV    231.9uV
468ps     -99.22uV   3.3mV      9.015uV
3ns       3.47uV     6.181uV    502.5nV
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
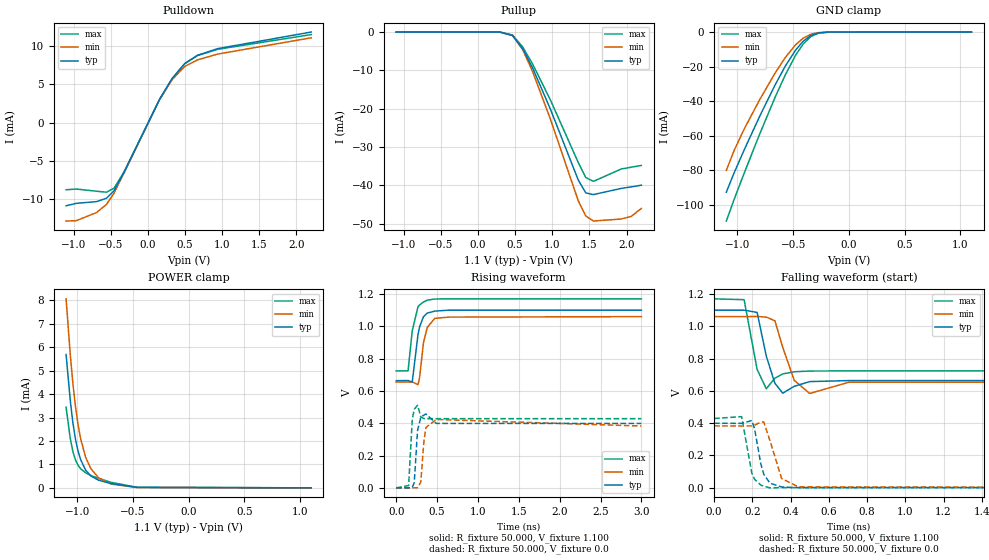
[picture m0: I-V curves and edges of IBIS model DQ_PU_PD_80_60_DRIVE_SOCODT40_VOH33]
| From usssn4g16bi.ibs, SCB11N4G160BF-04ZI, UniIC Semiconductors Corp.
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|   Model DQ_PU_PD_80_60_DRIVE_SOCODT40_VOH33
[Model] DQ_PU_PD_80_60_DRIVE_SOCODT40_VOH33
Model_type I/O
Polarity   Inverting
Vinl =  98.000mV
Vinh =  0.268V
Vmeas =  0.183V
Rref =  50.000
Vref =  0.183V
C_comp   1.020pF   1.010pF   1.030pF
[Model Spec]
Vinh   0.268V   0.262V   0.280V
Vinl   98.000mV   92.000mV   0.110V
Vmeas   0.183V   0.177V   0.195V
Vref   0.183V   0.177V   0.195V
Rref   50.000   NA   NA
[Temperature Range]   25.000   85.000   -40.000
[Voltage Range]   1.100V   1.060V   1.170V
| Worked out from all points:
|   slope of the pulldown table from 0 to 0.165 V, typ, clamps not added: 52.7 ohm
|   GND clamp passes 1 mA (typ) near -0.30 V on its own axis
|   POWER clamp passes 1 mA (typ) near -0.95 V on its own axis
|   rising waveform, R_fixture 50.000, V_fixture 1.100: 20-80 % time 72ps typ, 72.4ps min, 70.5ps max; typ from 0.663 V to 1.1 V
|   rising waveform, R_fixture 50.000, V_fixture 0.0: 20-80 % time 26.7ps typ, 33.6ps min, 21.8ps max; typ from 0 V to 0.399 V
|   falling waveform, R_fixture 50.000, V_fixture 1.100: 20-80 % time 44.5ps typ, 56.2ps min, 35.4ps max; typ from 1.1 V to 0.663 V
|   falling waveform, R_fixture 50.000, V_fixture 0.0: 20-80 % time 41.4ps typ, 54.9ps min, 37.2ps max; typ from 0.399 V to 0 V
[Pulldown]
|Voltage   I(typ)   I(min)   I(max)
-1.1V     -10.83mA   -12.81mA   -8.746mA
-964mV    -10.51mA   -12.77mA   -8.65mA
-692mV    -10.29mA   -11.72mA   -8.932mA
-556mV    -9.849mA   -10.65mA   -9.063mA
-454mV    -8.849mA   -9.178mA   -8.534mA
-318mV    -6.436mA   -6.525mA   -6.383mA
158mV     3.005mA    2.979mA    3.019mA
328mV     5.729mA    5.594mA    5.734mA
498mV     7.686mA    7.305mA    7.672mA
668mV     8.751mA    8.153mA    8.715mA
940mV     9.618mA    8.913mA    9.532mA
2.2V      11.78mA    11.03mA    11.45mA
[Pullup]
|Voltage   I(typ)   I(min)   I(max)
-1.1V     3.1nA      15.54nA    0A
296mV     -17.69uA   -21.17uA   -9.843uA
466mV     -927.4uA   -911uA     -773.6uA
602mV     -4.341mA   -4.574mA   -3.886mA
738mV     -9.474mA   -10.43mA   -8.429mA
976mV     -20.15mA   -22.77mA   -17.76mA
1.35V     -38.63mA   -44.04mA   -34.05mA
1.452V    -42.01mA   -48.04mA   -38mA
1.554V    -42.45mA   -49.35mA   -39mA
1.928V    -40.84mA   -48.83mA   -35.77mA
2.064V    -40.44mA   -48.15mA   -35.29mA
2.2V      -40mA      -46.05mA   -34.84mA
[GND_clamp]
|Voltage   I(typ)   I(min)   I(max)
-1.1V     -92.78mA   -80.14mA   -109.5mA
-1.031V   -81.73mA   -68.77mA   -97.17mA
-939mV    -68.18mA   -56.07mA   -81.64mA
-801mV    -48.85mA   -39.25mA   -59.15mA
-663mV    -30.71mA   -23.84mA   -37.89mA
-571mV    -19.76mA   -14.75mA   -24.85mA
-479mV    -10.5mA    -7.415mA   -13.5mA
-410mV    -5.313mA   -3.546mA   -6.916mA
-341mV    -2.007mA   -1.262mA   -2.59mA
-272mV    -506.9uA   -323.5uA   -609.8uA
-180mV    -45.65uA   -36.06uA   -43.55uA
1.1V      0A         0A         0A
[POWER_clamp]
|Voltage   I(typ)   I(min)   I(max)
-1.1V     5.691mA    8.066mA    3.44mA
-1.062V   3.709mA    5.665mA    2.092mA
-1.039V   2.781mA    4.457mA    1.546mA
-1.016V   2.086mA    3.48mA     1.193mA
-993mV    1.578mA    2.707mA    966.5uA
-970mV    1.21mA     2.107mA    818.5uA
-924mV    750.8uA    1.296mA    641.3uA
-878mV    507uA      821.4uA    530.2uA
-809mV    327.4uA    430uA      403.3uA
-694mV    178.4uA    161uA      233uA
-464mV    19.89uA    15.19uA    23.61uA
1.1V      0A         0A         0A
[Ramp]
| variable   typ   min   max
dV/dt_r   0.239/26.913p   0.230/33.706p   0.257/22.016p
dV/dt_f   0.262/44.569p   0.243/56.365p   0.268/35.481p
R_load = 50.000
[Rising Waveform]
R_fixture= 50.000
V_fixture= 1.100
V_fixture_min= 1.060
V_fixture_max= 1.170
|time   V(typ)   V(min)   V(max)
0s        663.5mV    654.8mV    723.5mV
145ps     664.3mV    655.3mV    724mV
196ps     654.7mV    655.8mV    971.6mV
267ps     950.1mV    638.6mV    1.122V
286ps     996.3mV    682.8mV    1.132V
333ps     1.059V     896.8mV    1.15V
380ps     1.082V     993.1mV    1.162V
471ps     1.094V     1.049V     1.169V
641ps     1.1V       1.057V     1.17V
3ns       1.1V       1.06V      1.17V
[Rising Waveform]
R_fixture= 50.000
V_fixture= 0.0
V_fixture_min= 0.0
V_fixture_max= 0.0
|time   V(typ)   V(min)   V(max)
0s        3.262uV    6.246uV    771.1nV
152ps     -206.7uV   51.42uV    13.97mV
197ps     2.221mV    -89.76uV   426.6mV
221ps     32.86mV    -166.3uV   486.4mV
261ps     354.4mV    717.9uV    511mV
301ps     437.8mV    36.28mV    439.5mV
338ps     450.1mV    282mV      428.8mV
363ps     457.3mV    373.3mV    428.4mV
490ps     398.9mV    423mV      428.3mV
3ns       398.9mV    382.6mV    428.3mV
[Falling Waveform]
R_fixture= 50.000
V_fixture= 1.100
V_fixture_min= 1.060
V_fixture_max= 1.170
|time   V(typ)   V(min)   V(max)
0s        1.1V       1.06V      1.17V
157ps     1.1V       1.06V      1.165V
225ps     1.086V     1.061V     732.9mV
273ps     815mV      1.057V     612.6mV
318ps     646.3mV    1.034V     678.2mV
359ps     585.4mV    869.6mV    704.7mV
419ps     627.9mV    665.3mV    718.1mV
500ps     657.1mV    583.3mV    722.5mV
705ps     663.4mV    653.2mV    723.5mV
3ns       663.5mV    654.8mV    723.5mV
[Falling Waveform]
R_fixture= 50.000
V_fixture= 0.0
V_fixture_min= 0.0
V_fixture_max= 0.0
|time   V(typ)   V(min)   V(max)
0s        398.9mV    382.6mV    428.3mV
144ps     398.1mV    381.9mV    439.8mV
197ps     415.6mV    382.6mV    91.14mV
212ps     363.3mV    387.2mV    51.18mV
244ps     149.4mV    406mV      15.52mV
260ps     82.39mV    406.9mV    8.258mV
292ps     27.47mV    291.4mV    -1.611mV
353ps     3.987mV    56.76mV    -227.5uV
441ps     -685.8uV   4.564mV    -9.03uV
3ns       2.269uV    6.107uV    -1.466uV
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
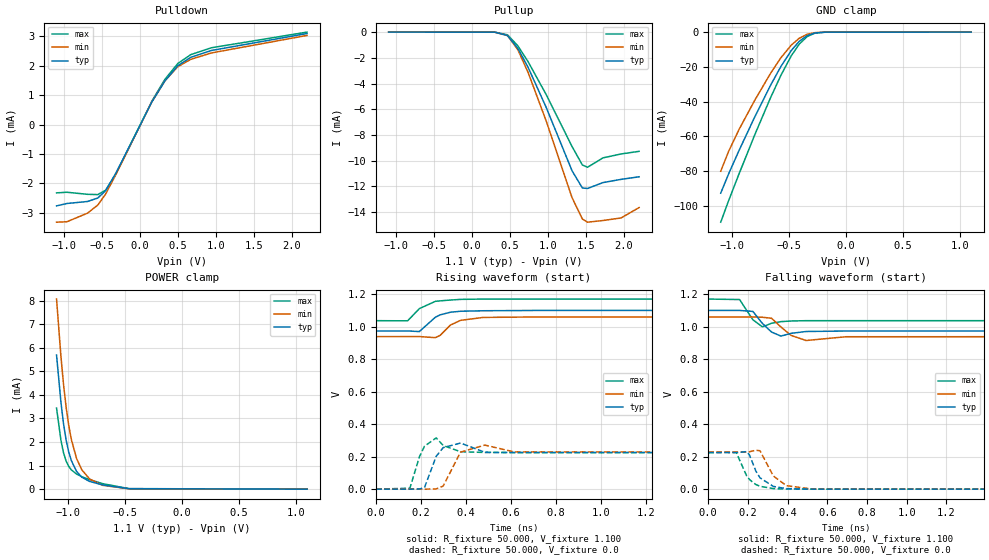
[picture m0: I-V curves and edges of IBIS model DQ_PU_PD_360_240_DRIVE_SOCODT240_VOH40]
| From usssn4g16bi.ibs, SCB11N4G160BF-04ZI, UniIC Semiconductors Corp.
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|   Model DQ_PU_PD_360_240_DRIVE_SOCODT240_VOH40
[Model] DQ_PU_PD_360_240_DRIVE_SOCODT240_VOH40
Model_type I/O
Polarity   Inverting
Vinl =  0.135V
Vinh =  0.305V
Vmeas =  0.220V
Rref =  50.000
Vref =  0.220V
C_comp   1.020pF   1.010pF   1.030pF
[Model Spec]
Vinh   0.305V   0.297V   0.319V
Vinl   0.135V   0.127V   0.149V
Vmeas   0.220V   0.212V   0.234V
Vref   0.220V   0.212V   0.234V
Rref   50.000   NA   NA
[Temperature Range]   25.000   85.000   -40.000
[Voltage Range]   1.100V   1.060V   1.170V
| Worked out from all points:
|   slope of the pulldown table from 0 to 0.165 V, typ, clamps not added: 205 ohm
|   GND clamp passes 1 mA (typ) near -0.30 V on its own axis
|   POWER clamp passes 1 mA (typ) near -0.95 V on its own axis
|   rising waveform, R_fixture 50.000, V_fixture 1.100: 20-80 % time 68.4ps typ, 70.5ps min, 68.1ps max; typ from 0.973 V to 1.1 V
|   rising waveform, R_fixture 50.000, V_fixture 0.0: 20-80 % time 32.3ps typ, 41.4ps min, 25.5ps max; typ from 0 V to 0.225 V
|   falling waveform, R_fixture 50.000, V_fixture 1.100: 20-80 % time 47.2ps typ, 60.3ps min, 37.6ps max; typ from 1.1 V to 0.973 V
|   falling waveform, R_fixture 50.000, V_fixture 0.0: 20-80 % time 63ps typ, 70.6ps min, 60.5ps max; typ from 0.225 V to 0 V
[Pulldown]
|Voltage   I(typ)   I(min)   I(max)
-1.1V     -2.76mA    -3.313mA   -2.318mA
-964mV    -2.679mA   -3.298mA   -2.298mA
-692mV    -2.611mA   -3.007mA   -2.368mA
-556mV    -2.492mA   -2.73mA    -2.377mA
-454mV    -2.244mA   -2.361mA   -2.229mA
-318mV    -1.646mA   -1.692mA   -1.68mA
158mV     774.5uA    782.1uA    802.1uA
328mV     1.481mA    1.483mA    1.534mA
498mV     1.994mA    1.962mA    2.07mA
668mV     2.279mA    2.209mA    2.37mA
940mV     2.511mA    2.427mA    2.602mA
2.2V      3.086mA    3.021mA    3.134mA
[Pullup]
|Voltage   I(typ)   I(min)   I(max)
-1.1V     900pA      4.512nA    0A
296mV     -5.16uA    -6.193uA   -2.645uA
466mV     -269.4uA   -269uA     -210.8uA
602mV     -1.26mA    -1.371mA   -1.066mA
738mV     -2.752mA   -3.15mA    -2.312mA
976mV     -5.863mA   -6.919mA   -4.864mA
1.316V    -10.78mA   -12.87mA   -8.894mA
1.452V    -12.12mA   -14.53mA   -10.33mA
1.52V     -12.16mA   -14.78mA   -10.51mA
1.724V    -11.7mA    -14.65mA   -9.778mA
1.962V    -11.45mA   -14.45mA   -9.476mA
2.2V      -11.25mA   -13.64mA   -9.27mA
[GND_clamp]
|Voltage   I(typ)   I(min)   I(max)
-1.1V     -92.78mA   -80.14mA   -109.5mA
-1.031V   -81.73mA   -68.77mA   -97.17mA
-939mV    -68.18mA   -56.07mA   -81.64mA
-801mV    -48.85mA   -39.25mA   -59.15mA
-663mV    -30.71mA   -23.84mA   -37.89mA
-571mV    -19.76mA   -14.75mA   -24.85mA
-479mV    -10.5mA    -7.415mA   -13.5mA
-410mV    -5.313mA   -3.546mA   -6.916mA
-341mV    -2.007mA   -1.262mA   -2.59mA
-272mV    -506.9uA   -323.5uA   -609.8uA
-180mV    -45.65uA   -36.06uA   -43.55uA
1.1V      0A         0A         0A
[POWER_clamp]
|Voltage   I(typ)   I(min)   I(max)
-1.1V     5.691mA    8.066mA    3.44mA
-1.062V   3.709mA    5.665mA    2.092mA
-1.039V   2.781mA    4.457mA    1.546mA
-1.016V   2.086mA    3.48mA     1.193mA
-993mV    1.578mA    2.707mA    966.5uA
-970mV    1.21mA     2.107mA    818.5uA
-924mV    750.8uA    1.296mA    641.3uA
-878mV    507uA      821.4uA    530.2uA
-809mV    327.4uA    430uA      403.3uA
-694mV    178.4uA    161uA      233uA
-464mV    19.89uA    15.19uA    23.61uA
1.1V      0A         0A         0A
[Ramp]
| variable   typ   min   max
dV/dt_r   0.135/32.421p   0.137/41.490p   0.135/25.787p
dV/dt_f   75.974m/47.303p   72.781m/60.238p   79.780m/37.576p
R_load = 50.000
[Rising Waveform]
R_fixture= 50.000
V_fixture= 1.100
V_fixture_min= 1.060
V_fixture_max= 1.170
|time   V(typ)   V(min)   V(max)
0s        973.4mV    938.7mV    1.037V
140ps     973.7mV    938.9mV    1.036V
192ps     969.9mV    939.1mV    1.111V
263ps     1.058V     932.4mV    1.156V
285ps     1.073V     947.1mV    1.159V
330ps     1.089V     1.01V      1.164V
375ps     1.095V     1.039V     1.168V
476ps     1.098V     1.057V     1.17V
721ps     1.1V       1.06V      1.17V
3ns       1.1V       1.06V      1.17V
[Rising Waveform]
R_fixture= 50.000
V_fixture= 0.0
V_fixture_min= 0.0
V_fixture_max= 0.0
|time   V(typ)   V(min)   V(max)
0s        5.206uV    9.934uV    1.226uV
150ps     -117.6uV   45.87uV    5.972mV
193ps     979.9uV    -48.82uV   201.6mV
215ps     10.25mV    -143.4uV   264.2mV
267ps     202mV      1.508mV    315.6mV
298ps     255.5mV    19.06mV    268.6mV
375ps     283.8mV    227.9mV    230.3mV
483ps     227mV      271.1mV    225.7mV
612ps     224.8mV    229.4mV    225.5mV
3ns       224.7mV    228.3mV    225.5mV
[Falling Waveform]
R_fixture= 50.000
V_fixture= 1.100
V_fixture_min= 1.060
V_fixture_max= 1.170
|time   V(typ)   V(min)   V(max)
0s        1.1V       1.06V      1.17V
158ps     1.1V       1.06V      1.167V
225ps     1.094V     1.06V      1.043V
273ps     1.02V      1.058V     998.9mV
319ps     967.2mV    1.052V     1.021V
366ps     942.2mV    998.5mV    1.031V
418ps     959.1mV    946mV      1.035V
493ps     970.4mV    914.9mV    1.037V
694ps     973.3mV    938.1mV    1.037V
3ns       973.4mV    938.7mV    1.037V
[Falling Waveform]
R_fixture= 50.000
V_fixture= 0.0
V_fixture_min= 0.0
V_fixture_max= 0.0
|time   V(typ)   V(min)   V(max)
0s        224.7mV    228.3mV    225.5mV
140ps     224.3mV    228.1mV    229.2mV
194ps     231.1mV    228.3mV    81.2mV
208ps     210.1mV    230.3mV    59.13mV
240ps     111.5mV    239.7mV    28.65mV
261ps     69.82mV    236.5mV    17.64mV
328ps     16.82mV    81.3mV     3.507mV
394ps     3.341mV    21.54mV    844uV
521ps     251.1uV    1.277mV    53.87uV
3ns       5.228uV    9.943uV    1.258uV
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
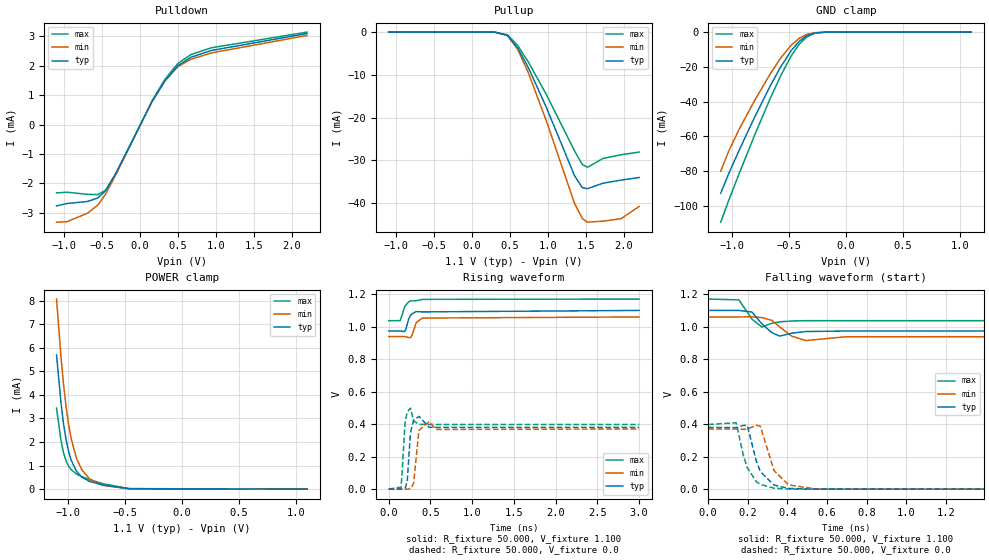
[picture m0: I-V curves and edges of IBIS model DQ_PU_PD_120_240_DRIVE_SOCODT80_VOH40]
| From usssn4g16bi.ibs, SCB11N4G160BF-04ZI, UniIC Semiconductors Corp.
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|   Model DQ_PU_PD_120_240_DRIVE_SOCODT80_VOH40
[Model] DQ_PU_PD_120_240_DRIVE_SOCODT80_VOH40
Model_type I/O
Polarity   Inverting
Vinl =  0.135V
Vinh =  0.305V
Vmeas =  0.220V
Rref =  50.000
Vref =  0.220V
C_comp   1.020pF   1.010pF   1.030pF
[Model Spec]
Vinh   0.305V   0.297V   0.319V
Vinl   0.135V   0.127V   0.149V
Vmeas   0.220V   0.212V   0.234V
Vref   0.220V   0.212V   0.234V
Rref   50.000   NA   NA
[Temperature Range]   25.000   85.000   -40.000
[Voltage Range]   1.100V   1.060V   1.170V
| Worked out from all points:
|   slope of the pulldown table from 0 to 0.165 V, typ, clamps not added: 205 ohm
|   GND clamp passes 1 mA (typ) near -0.30 V on its own axis
|   POWER clamp passes 1 mA (typ) near -0.95 V on its own axis
|   rising waveform, R_fixture 50.000, V_fixture 1.100: 20-80 % time 55.7ps typ, 53.1ps min, 62.9ps max; typ from 0.973 V to 1.1 V
|   rising waveform, R_fixture 50.000, V_fixture 0.0: 20-80 % time 26.8ps typ, 34.8ps min, 21.3ps max; typ from 0 V to 0.38 V
|   falling waveform, R_fixture 50.000, V_fixture 1.100: 20-80 % time 49.7ps typ, 68.5ps min, 38.9ps max; typ from 1.1 V to 0.973 V
|   falling waveform, R_fixture 50.000, V_fixture 0.0: 20-80 % time 61.2ps typ, 67ps min, 59.8ps max; typ from 0.38 V to 0 V
[Pulldown]
|Voltage   I(typ)   I(min)   I(max)
-1.1V     -2.76mA    -3.313mA   -2.318mA
-964mV    -2.679mA   -3.298mA   -2.298mA
-692mV    -2.611mA   -3.007mA   -2.368mA
-556mV    -2.492mA   -2.73mA    -2.377mA
-454mV    -2.244mA   -2.361mA   -2.229mA
-318mV    -1.646mA   -1.692mA   -1.68mA
158mV     774.5uA    782.1uA    802.1uA
328mV     1.481mA    1.483mA    1.534mA
498mV     1.994mA    1.962mA    2.07mA
668mV     2.279mA    2.209mA    2.37mA
940mV     2.511mA    2.427mA    2.602mA
2.2V      3.086mA    3.021mA    3.134mA
[Pullup]
|Voltage   I(typ)   I(min)   I(max)
-1.1V     2.7nA      13.54nA    0A
296mV     -15.48uA   -18.58uA   -7.934uA
466mV     -807.4uA   -806.2uA   -632uA
602mV     -3.772mA   -4.103mA   -3.194mA
738mV     -8.234mA   -9.422mA   -6.922mA
976mV     -17.54mA   -20.68mA   -14.55mA
1.35V     -33.63mA   -40.11mA   -27.84mA
1.452V    -36.39mA   -43.62mA   -30.97mA
1.52V     -36.62mA   -44.46mA   -31.62mA
1.724V    -35.34mA   -44.21mA   -29.55mA
1.962V    -34.61mA   -43.64mA   -28.68mA
2.2V      -34.01mA   -40.78mA   -28.06mA
[GND_clamp]
|Voltage   I(typ)   I(min)   I(max)
-1.1V     -92.78mA   -80.14mA   -109.5mA
-1.031V   -81.73mA   -68.77mA   -97.17mA
-939mV    -68.18mA   -56.07mA   -81.64mA
-801mV    -48.85mA   -39.25mA   -59.15mA
-663mV    -30.71mA   -23.84mA   -37.89mA
-571mV    -19.76mA   -14.75mA   -24.85mA
-479mV    -10.5mA    -7.415mA   -13.5mA
-410mV    -5.313mA   -3.546mA   -6.916mA
-341mV    -2.007mA   -1.262mA   -2.59mA
-272mV    -506.9uA   -323.5uA   -609.8uA
-180mV    -45.65uA   -36.06uA   -43.55uA
1.1V      0A         0A         0A
[POWER_clamp]
|Voltage   I(typ)   I(min)   I(max)
-1.1V     5.691mA    8.066mA    3.44mA
-1.062V   3.709mA    5.665mA    2.092mA
-1.039V   2.781mA    4.457mA    1.546mA
-1.016V   2.086mA    3.48mA     1.193mA
-993mV    1.578mA    2.707mA    966.5uA
-970mV    1.21mA     2.107mA    818.5uA
-924mV    750.8uA    1.296mA    641.3uA
-878mV    507uA      821.4uA    530.2uA
-809mV    327.4uA    430uA      403.3uA
-694mV    178.4uA    161uA      233uA
-464mV    19.89uA    15.19uA    23.61uA
1.1V      0A         0A         0A
[Ramp]
| variable   typ   min   max
dV/dt_r   0.228/26.964p   0.222/35.075p   0.239/21.444p
dV/dt_f   75.974m/49.659p   72.781m/68.333p   79.780m/38.946p
R_load = 50.000
[Rising Waveform]
R_fixture= 50.000
V_fixture= 1.100
V_fixture_min= 1.060
V_fixture_max= 1.170
|time   V(typ)   V(min)   V(max)
0s        973.4mV    938.7mV    1.037V
139ps     973.7mV    938.9mV    1.037V
190ps     969.5mV    939.1mV    1.119V
205ps     981.5mV    938.2mV    1.133V
239ps     1.046V     933.3mV    1.152V
262ps     1.069V     932.3mV    1.159V
280ps     1.079V     946.3mV    1.159V
331ps     1.093V     1.026V     1.16V
404ps     1.091V     1.053V     1.168V
3ns       1.1V       1.06V      1.17V
[Rising Waveform]
R_fixture= 50.000
V_fixture= 0.0
V_fixture_min= 0.0
V_fixture_max= 0.0
|time   V(typ)   V(min)   V(max)
0s        5.206uV    9.934uV    1.226uV
150ps     -355.2uV   82.65uV    11.77mV
198ps     3.563mV    -242.5uV   416.7mV
223ps     49.94mV    -660.8uV   474.1mV
262ps     349.9mV    1.107mV    498.7mV
299ps     425.3mV    35.28mV    420mV
363ps     447.6mV    361.9mV    398.3mV
485ps     379.9mV    414.3mV    397.7mV
569ps     379.9mV    367.2mV    397.7mV
3ns       379.9mV    370mV      397.7mV
[Falling Waveform]
R_fixture= 50.000
V_fixture= 1.100
V_fixture_min= 1.060
V_fixture_max= 1.170
|time   V(typ)   V(min)   V(max)
0s        1.1V       1.06V      1.17V
155ps     1.1V       1.06V      1.165V
221ps     1.09V      1.061V     1.046V
271ps     1.017V     1.056V     997.9mV
321ps     963.3mV    1.039V     1.021V
361ps     942.2mV    998.3mV    1.03V
421ps     959.6mV    941.9mV    1.035V
492ps     970.2mV    914.5mV    1.037V
695ps     973.3mV    938.1mV    1.037V
3ns       973.4mV    938.7mV    1.037V
[Falling Waveform]
R_fixture= 50.000
V_fixture= 0.0
V_fixture_min= 0.0
V_fixture_max= 0.0
|time   V(typ)   V(min)   V(max)
0s        379.9mV    370mV      397.7mV
141ps     378.9mV    369.5mV    408.6mV
176ps     392.1mV    368.6mV    214.7mV
197ps     392.8mV    370.1mV    131.8mV
243ps     171.8mV    393.1mV    46.35mV
263ps     108.9mV    387.4mV    29.19mV
332ps     25.25mV    114.5mV    5.98mV
405ps     4.655mV    26.3mV     1.226mV
546ps     274.6uV    1.114mV    57.68uV
3ns       5.25uV     9.932uV    1.279uV
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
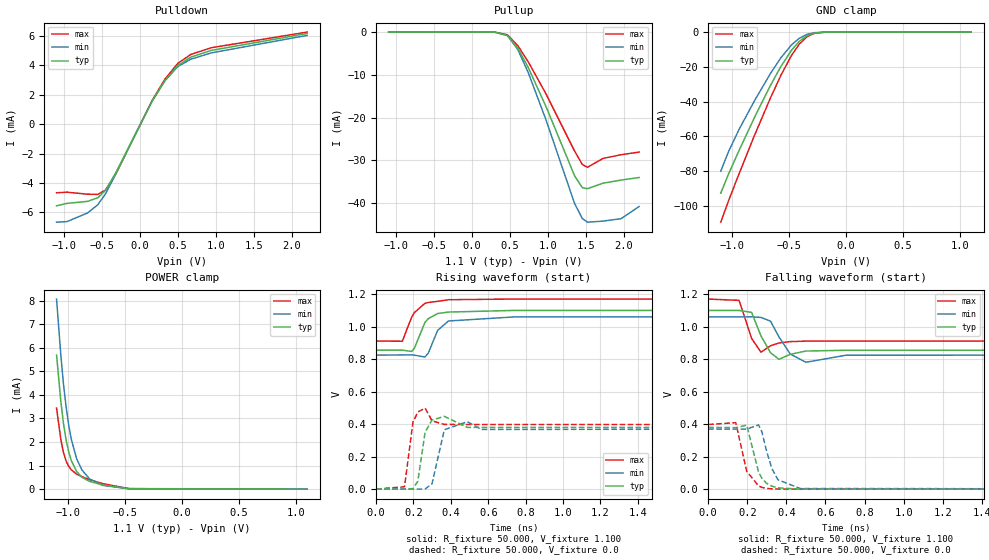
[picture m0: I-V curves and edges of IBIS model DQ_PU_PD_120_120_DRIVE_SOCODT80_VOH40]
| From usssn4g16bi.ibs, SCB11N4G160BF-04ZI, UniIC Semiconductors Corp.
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|   Model DQ_PU_PD_120_120_DRIVE_SOCODT80_VOH40
[Model] DQ_PU_PD_120_120_DRIVE_SOCODT80_VOH40
Model_type I/O
Polarity   Inverting
Vinl =  0.135V
Vinh =  0.305V
Vmeas =  0.220V
Rref =  50.000
Vref =  0.220V
C_comp   1.020pF   1.010pF   1.030pF
[Model Spec]
Vinh   0.305V   0.297V   0.319V
Vinl   0.135V   0.127V   0.149V
Vmeas   0.220V   0.212V   0.234V
Vref   0.220V   0.212V   0.234V
Rref   50.000   NA   NA
[Temperature Range]   25.000   85.000   -40.000
[Voltage Range]   1.100V   1.060V   1.170V
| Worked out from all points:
|   slope of the pulldown table from 0 to 0.165 V, typ, clamps not added: 102 ohm
|   GND clamp passes 1 mA (typ) near -0.30 V on its own axis
|   POWER clamp passes 1 mA (typ) near -0.95 V on its own axis
|   rising waveform, R_fixture 50.000, V_fixture 1.100: 20-80 % time 64.5ps typ, 64.4ps min, 67ps max; typ from 0.855 V to 1.1 V
|   rising waveform, R_fixture 50.000, V_fixture 0.0: 20-80 % time 26.6ps typ, 34.6ps min, 21.1ps max; typ from 0 V to 0.38 V
|   falling waveform, R_fixture 50.000, V_fixture 1.100: 20-80 % time 47.2ps typ, 61.4ps min, 37.7ps max; typ from 1.1 V to 0.855 V
|   falling waveform, R_fixture 50.000, V_fixture 0.0: 20-80 % time 51.2ps typ, 60.8ps min, 49.3ps max; typ from 0.38 V to 0 V
[Pulldown]
|Voltage   I(typ)   I(min)   I(max)
-1.1V     -5.559mA   -6.673mA   -4.673mA
-964mV    -5.394mA   -6.634mA   -4.631mA
-692mV    -5.255mA   -6.046mA   -4.769mA
-556mV    -5.011mA   -5.482mA   -4.784mA
-454mV    -4.503mA   -4.733mA   -4.479mA
-318mV    -3.293mA   -3.384mA   -3.363mA
158mV     1.547mA    1.562mA    1.602mA
328mV     2.959mA    2.962mA    3.064mA
498mV     3.986mA    3.92mA     4.137mA
668mV     4.555mA    4.415mA    4.737mA
940mV     5.019mA    4.85mA     5.2mA
2.2V      6.168mA    6.037mA    6.263mA
[Pullup]
|Voltage   I(typ)   I(min)   I(max)
-1.1V     2.7nA      13.54nA    0A
296mV     -15.48uA   -18.58uA   -7.934uA
466mV     -807.4uA   -806.2uA   -632uA
602mV     -3.772mA   -4.103mA   -3.194mA
738mV     -8.234mA   -9.422mA   -6.922mA
976mV     -17.54mA   -20.68mA   -14.55mA
1.35V     -33.63mA   -40.11mA   -27.84mA
1.452V    -36.39mA   -43.62mA   -30.97mA
1.52V     -36.62mA   -44.46mA   -31.62mA
1.724V    -35.34mA   -44.21mA   -29.55mA
1.962V    -34.61mA   -43.64mA   -28.68mA
2.2V      -34.01mA   -40.78mA   -28.06mA
[GND_clamp]
|Voltage   I(typ)   I(min)   I(max)
-1.1V     -92.78mA   -80.14mA   -109.5mA
-1.031V   -81.73mA   -68.77mA   -97.17mA
-939mV    -68.18mA   -56.07mA   -81.64mA
-801mV    -48.85mA   -39.25mA   -59.15mA
-663mV    -30.71mA   -23.84mA   -37.89mA
-571mV    -19.76mA   -14.75mA   -24.85mA
-479mV    -10.5mA    -7.415mA   -13.5mA
-410mV    -5.313mA   -3.546mA   -6.916mA
-341mV    -2.007mA   -1.262mA   -2.59mA
-272mV    -506.9uA   -323.5uA   -609.8uA
-180mV    -45.65uA   -36.06uA   -43.55uA
1.1V      0A         0A         0A
[POWER_clamp]
|Voltage   I(typ)   I(min)   I(max)
-1.1V     5.691mA    8.066mA    3.44mA
-1.062V   3.709mA    5.665mA    2.092mA
-1.039V   2.781mA    4.457mA    1.546mA
-1.016V   2.086mA    3.48mA     1.193mA
-993mV    1.578mA    2.707mA    966.5uA
-970mV    1.21mA     2.107mA    818.5uA
-924mV    750.8uA    1.296mA    641.3uA
-878mV    507uA      821.4uA    530.2uA
-809mV    327.4uA    430uA      403.3uA
-694mV    178.4uA    161uA      233uA
-464mV    19.89uA    15.19uA    23.61uA
1.1V      0A         0A         0A
[Ramp]
| variable   typ   min   max
dV/dt_r   0.228/26.885p   0.222/34.779p   0.239/21.334p
dV/dt_f   0.147/47.188p   0.141/61.456p   0.155/37.771p
R_load = 50.000
[Rising Waveform]
R_fixture= 50.000
V_fixture= 1.100
V_fixture_min= 1.060
V_fixture_max= 1.170
|time   V(typ)   V(min)   V(max)
0s        855mV      825.4mV    911.8mV
140ps     855.6mV    825.7mV    910.1mV
190ps     847.4mV    826.2mV    1.058V
205ps     867.6mV    824.6mV    1.087V
261ps     1.026V     812.9mV    1.144V
279ps     1.049V     836.8mV    1.149V
329ps     1.081V     976.9mV    1.156V
387ps     1.09V      1.035V     1.166V
737ps     1.1V       1.06V      1.17V
3ns       1.1V       1.06V      1.17V
[Rising Waveform]
R_fixture= 50.000
V_fixture= 0.0
V_fixture_min= 0.0
V_fixture_max= 0.0
|time   V(typ)   V(min)   V(max)
0s        4.316uV    8.22uV     1.011uV
152ps     -314.2uV   72.43uV    14.43mV
197ps     2.529mV    -141.4uV   411.5mV
223ps     47.95mV    -447.4uV   474mV
262ps     349.5mV    772.1uV    498.7mV
299ps     425.3mV    32.47mV    420.1mV
365ps     447.6mV    365.6mV    398.3mV
488ps     379.9mV    414.9mV    397.7mV
563ps     379.9mV    367.4mV    397.7mV
3ns       379.9mV    370mV      397.7mV
[Falling Waveform]
R_fixture= 50.000
V_fixture= 1.100
V_fixture_min= 1.060
V_fixture_max= 1.170
|time   V(typ)   V(min)   V(max)
0s        1.1V       1.06V      1.17V
158ps     1.1V       1.06V      1.162V
222ps     1.088V     1.061V     928.5mV
270ps     943.5mV    1.057V     842.9mV
319ps     840mV      1.034V     882.8mV
362ps     799.1mV    937.1mV    899.7mV
420ps     830mV      831.5mV    908mV
500ps     850mV      781mV      911.1mV
705ps     854.9mV    824.4mV    911.8mV
3ns       855mV      825.4mV    911.8mV
[Falling Waveform]
R_fixture= 50.000
V_fixture= 0.0
V_fixture_min= 0.0
V_fixture_max= 0.0
|time   V(typ)   V(min)   V(max)
0s        379.9mV    370mV      397.7mV
141ps     378.9mV    369.5mV    409.4mV
197ps     393.7mV    370mV      110.3mV
258ps     104.5mV    395.2mV    19.75mV
275ps     66.6mV     351.5mV    11.04mV
298ps     36.8mV     237.4mV    4.619mV
326ps     18.15mV    126.2mV    2.237mV
357ps     8.215mV    57.96mV    1.016mV
470ps     236.7uV    4.394mV    53.36uV
3ns       4.28uV     8.081uV    1.062uV
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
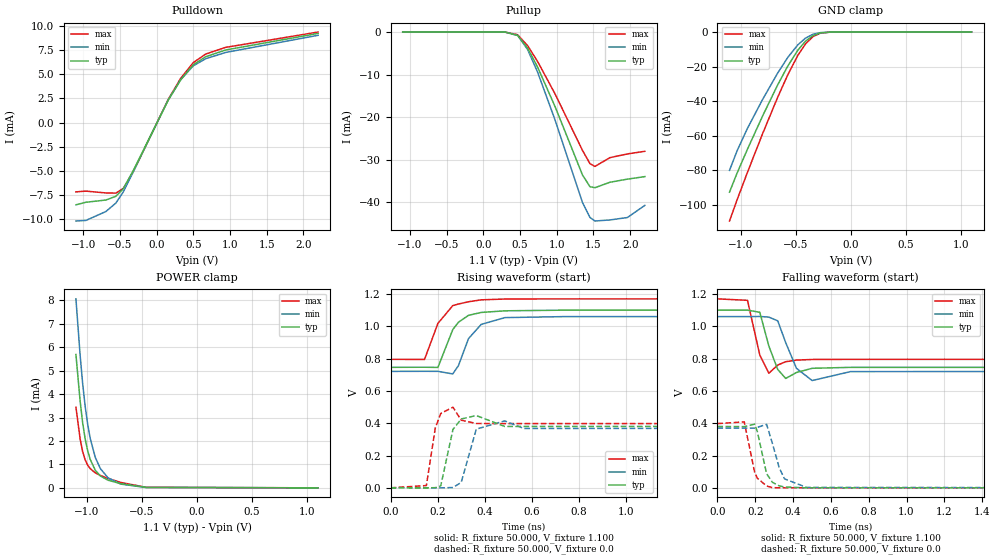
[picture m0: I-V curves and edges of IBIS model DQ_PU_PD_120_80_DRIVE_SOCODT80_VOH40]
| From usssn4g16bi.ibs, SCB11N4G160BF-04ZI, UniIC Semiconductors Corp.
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|   Model DQ_PU_PD_120_80_DRIVE_SOCODT80_VOH40
[Model] DQ_PU_PD_120_80_DRIVE_SOCODT80_VOH40
Model_type I/O
Polarity   Inverting
Vinl =  0.135V
Vinh =  0.305V
Vmeas =  0.220V
Rref =  50.000
Vref =  0.220V
C_comp   1.020pF   1.010pF   1.030pF
[Model Spec]
Vinh   0.305V   0.297V   0.319V
Vinl   0.135V   0.127V   0.149V
Vmeas   0.220V   0.212V   0.234V
Vref   0.220V   0.212V   0.234V
Rref   50.000   NA   NA
[Temperature Range]   25.000   85.000   -40.000
[Voltage Range]   1.100V   1.060V   1.170V
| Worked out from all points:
|   slope of the pulldown table from 0 to 0.165 V, typ, clamps not added: 68.2 ohm
|   GND clamp passes 1 mA (typ) near -0.30 V on its own axis
|   POWER clamp passes 1 mA (typ) near -0.95 V on its own axis
|   rising waveform, R_fixture 50.000, V_fixture 1.100: 20-80 % time 69.6ps typ, 70.7ps min, 70ps max; typ from 0.746 V to 1.1 V
|   rising waveform, R_fixture 50.000, V_fixture 0.0: 20-80 % time 26.5ps typ, 34.3ps min, 21.2ps max; typ from 0 V to 0.38 V
|   falling waveform, R_fixture 50.000, V_fixture 1.100: 20-80 % time 46.5ps typ, 59.8ps min, 37.7ps max; typ from 1.1 V to 0.746 V
|   falling waveform, R_fixture 50.000, V_fixture 0.0: 20-80 % time 45.6ps typ, 58.1ps min, 43.1ps max; typ from 0.38 V to 0 V
[Pulldown]
|Voltage   I(typ)   I(min)   I(max)
-1.1V     -8.531mA   -10.21mA   -7.187mA
-964mV    -8.264mA   -10.15mA   -7.109mA
-692mV    -8.033mA   -9.227mA   -7.298mA
-556mV    -7.649mA   -8.349mA   -7.316mA
-454mV    -6.852mA   -7.181mA   -6.833mA
-318mV    -4.969mA   -5.097mA   -5.081mA
158mV     2.325mA    2.347mA    2.407mA
328mV     4.444mA    4.448mA    4.602mA
498mV     5.984mA    5.884mA    6.211mA
668mV     6.835mA    6.624mA    7.108mA
940mV     7.53mA     7.275mA    7.801mA
2.2V      9.253mA    9.055mA    9.394mA
[Pullup]
|Voltage   I(typ)   I(min)   I(max)
-1.1V     2.7nA      13.54nA    0A
296mV     -15.48uA   -18.58uA   -7.934uA
466mV     -807.4uA   -806.2uA   -632uA
602mV     -3.772mA   -4.103mA   -3.194mA
738mV     -8.234mA   -9.422mA   -6.922mA
976mV     -17.54mA   -20.68mA   -14.55mA
1.35V     -33.63mA   -40.11mA   -27.84mA
1.452V    -36.39mA   -43.62mA   -30.97mA
1.52V     -36.62mA   -44.46mA   -31.62mA
1.724V    -35.34mA   -44.21mA   -29.55mA
1.962V    -34.61mA   -43.64mA   -28.68mA
2.2V      -34.01mA   -40.78mA   -28.06mA
[GND_clamp]
|Voltage   I(typ)   I(min)   I(max)
-1.1V     -92.78mA   -80.14mA   -109.5mA
-1.031V   -81.73mA   -68.77mA   -97.17mA
-939mV    -68.18mA   -56.07mA   -81.64mA
-801mV    -48.85mA   -39.25mA   -59.15mA
-663mV    -30.71mA   -23.84mA   -37.89mA
-571mV    -19.76mA   -14.75mA   -24.85mA
-479mV    -10.5mA    -7.415mA   -13.5mA
-410mV    -5.313mA   -3.546mA   -6.916mA
-341mV    -2.007mA   -1.262mA   -2.59mA
-272mV    -506.9uA   -323.5uA   -609.8uA
-180mV    -45.65uA   -36.06uA   -43.55uA
1.1V      0A         0A         0A
[POWER_clamp]
|Voltage   I(typ)   I(min)   I(max)
-1.1V     5.691mA    8.066mA    3.44mA
-1.062V   3.709mA    5.665mA    2.092mA
-1.039V   2.781mA    4.457mA    1.546mA
-1.016V   2.086mA    3.48mA     1.193mA
-993mV    1.578mA    2.707mA    966.5uA
-970mV    1.21mA     2.107mA    818.5uA
-924mV    750.8uA    1.296mA    641.3uA
-878mV    507uA      821.4uA    530.2uA
-809mV    327.4uA    430uA      403.3uA
-694mV    178.4uA    161uA      233uA
-464mV    19.89uA    15.19uA    23.61uA
1.1V      0A         0A         0A
[Ramp]
| variable   typ   min   max
dV/dt_r   0.228/26.702p   0.222/34.503p   0.239/21.401p
dV/dt_f   0.212/46.552p   0.203/59.736p   0.225/37.677p
R_load = 50.000
[Rising Waveform]
R_fixture= 50.000
V_fixture= 1.100
V_fixture_min= 1.060
V_fixture_max= 1.170
|time   V(typ)   V(min)   V(max)
0s        746mV      721mV      795.6mV
144ps     746.7mV    721.4mV    794.8mV
201ps     745.5mV    721.2mV    1.018V
264ps     979mV      705.2mV    1.128V
288ps     1.025V     755.8mV    1.138V
331ps     1.068V     923.8mV    1.152V
385ps     1.086V     1.012V     1.164V
486ps     1.096V     1.054V     1.169V
732ps     1.1V       1.06V      1.17V
3ns       1.1V       1.06V      1.17V
[Rising Waveform]
R_fixture= 50.000
V_fixture= 0.0
V_fixture_min= 0.0
V_fixture_max= 0.0
|time   V(typ)   V(min)   V(max)
0s        3.688uV    7.016uV    861.5nV
152ps     -275.7uV   56.57uV    13.88mV
190ps     705.5uV    -25.3uV    371.1mV
213ps     11.83mV    -255.2uV   460.1mV
265ps     361.5mV    1.514mV    499.1mV
300ps     426mV      33.32mV    418.6mV
364ps     447.6mV    363.2mV    398.3mV
485ps     379.9mV    414.3mV    397.7mV
566ps     379.9mV    367.3mV    397.7mV
3ns       379.9mV    370mV      397.7mV
[Falling Waveform]
R_fixture= 50.000
V_fixture= 1.100
V_fixture_min= 1.060
V_fixture_max= 1.170
|time   V(typ)   V(min)   V(max)
0s        1.1V       1.06V      1.17V
159ps     1.1V       1.06V      1.161V
224ps     1.087V     1.061V     822.7mV
272ps     877.4mV    1.057V     709.5mV
319ps     732.8mV    1.034V     760.4mV
361ps     677.3mV    899.1mV    780.7mV
418ps     714.1mV    739.8mV    790.9mV
501ps     740.1mV    664.3mV    794.7mV
704ps     745.9mV    719.7mV    795.5mV
3ns       746mV      721mV      795.6mV
[Falling Waveform]
R_fixture= 50.000
V_fixture= 0.0
V_fixture_min= 0.0
V_fixture_max= 0.0
|time   V(typ)   V(min)   V(max)
0s        379.9mV    370mV      397.7mV
142ps     379mV      369.5mV    408.3mV
197ps     394.2mV    370mV      95.75mV
211ps     348.7mV    374.2mV    59.99mV
260ps     87.86mV    393.3mV    11.56mV
291ps     34.09mV    273.8mV    1.108mV
327ps     11.91mV    123.3mV    260.1uV
355ps     5.289mV    55.25mV    134.8uV
471ps     -96.48uV   2.843mV    5.434uV
3ns       3.355uV    6.857uV    -2.617uV
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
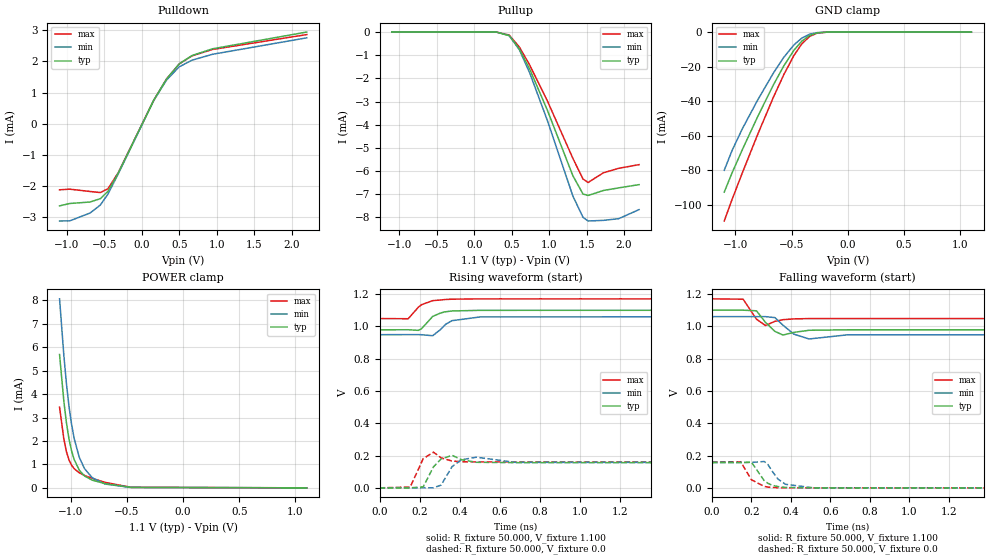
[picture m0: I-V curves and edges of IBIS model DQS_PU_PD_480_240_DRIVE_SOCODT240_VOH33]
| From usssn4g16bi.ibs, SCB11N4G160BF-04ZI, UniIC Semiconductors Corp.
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|   Model DQS_PU_PD_480_240_DRIVE_SOCODT240_VOH33
[Model] DQS_PU_PD_480_240_DRIVE_SOCODT240_VOH33
Model_type I/O
Polarity   Inverting
Vinl =  98.000mV
Vinh =  0.268V
Vmeas =  0.183V
Rref =  50.000
Vref =  0.183V
C_comp   1.020pF   1.010pF   1.030pF
[Model Spec]
Vinh   0.268V   0.262V   0.280V
Vinl   98.000mV   92.000mV   0.110V
Vmeas   0.183V   0.177V   0.195V
Vref   0.183V   0.177V   0.195V
Rref   50.000   NA   NA
[Temperature Range]   25.000   85.000   -40.000
[Voltage Range]   1.100V   1.060V   1.170V
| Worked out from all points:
|   slope of the pulldown table from 0 to 0.165 V, typ, clamps not added: 211 ohm
|   GND clamp passes 1 mA (typ) near -0.30 V on its own axis
|   POWER clamp passes 1 mA (typ) near -0.95 V on its own axis
|   rising waveform, R_fixture 50.000, V_fixture 1.100: 20-80 % time 66.6ps typ, 68.2ps min, 65ps max; typ from 0.978 V to 1.1 V
|   rising waveform, R_fixture 50.000, V_fixture 0.0: 20-80 % time 35.1ps typ, 43.5ps min, 28.3ps max; typ from 0 V to 0.156 V
|   falling waveform, R_fixture 50.000, V_fixture 1.100: 20-80 % time 44.2ps typ, 55ps min, 34.5ps max; typ from 1.1 V to 0.978 V
|   falling waveform, R_fixture 50.000, V_fixture 0.0: 20-80 % time 56.7ps typ, 64ps min, 53.6ps max; typ from 0.156 V to 0 V
[Pulldown]
|Voltage   I(typ)   I(min)   I(max)
-1.1V     -2.652mA   -3.14mA    -2.134mA
-964mV    -2.576mA   -3.135mA   -2.114mA
-692mV    -2.527mA   -2.882mA   -2.189mA
-556mV    -2.422mA   -2.626mA   -2.223mA
-454mV    -2.185mA   -2.274mA   -2.101mA
-318mV    -1.604mA   -1.629mA   -1.589mA
158mV     752.2uA    745.4uA    755.4uA
328mV     1.434mA    1.4mA      1.435mA
498mV     1.924mA    1.828mA    1.92mA
668mV     2.19mA     2.04mA     2.18mA
940mV     2.407mA    2.23mA     2.385mA
2.2V      2.948mA    2.761mA    2.866mA
[Pullup]
|Voltage   I(typ)   I(min)   I(max)
-1.1V     500pA      2.606nA    0A
296mV     -2.948uA   -3.529uA   -1.641uA
466mV     -154.8uA   -152.1uA   -129.1uA
602mV     -725.8uA   -765uA     -649.5uA
738mV     -1.585mA   -1.746mA   -1.41mA
976mV     -3.374mA   -3.816mA   -2.972mA
1.316V    -6.198mA   -7.072mA   -5.446mA
1.452V    -6.989mA   -7.995mA   -6.341mA
1.52V     -7.049mA   -8.152mA   -6.489mA
1.724V    -6.835mA   -8.124mA   -6.072mA
1.928V    -6.723mA   -8.051mA   -5.878mA
2.2V      -6.582mA   -7.66mA    -5.721mA
[GND_clamp]
|Voltage   I(typ)   I(min)   I(max)
-1.1V     -92.78mA   -80.14mA   -109.5mA
-1.031V   -81.73mA   -68.77mA   -97.17mA
-939mV    -68.18mA   -56.07mA   -81.64mA
-801mV    -48.85mA   -39.25mA   -59.15mA
-663mV    -30.71mA   -23.84mA   -37.89mA
-571mV    -19.76mA   -14.75mA   -24.85mA
-479mV    -10.5mA    -7.415mA   -13.5mA
-410mV    -5.313mA   -3.546mA   -6.916mA
-341mV    -2.007mA   -1.262mA   -2.59mA
-272mV    -506.9uA   -323.5uA   -609.8uA
-180mV    -45.65uA   -36.06uA   -43.55uA
1.1V      0A         0A         0A
[POWER_clamp]
|Voltage   I(typ)   I(min)   I(max)
-1.1V     5.691mA    8.066mA    3.44mA
-1.062V   3.709mA    5.665mA    2.092mA
-1.039V   2.781mA    4.457mA    1.546mA
-1.016V   2.086mA    3.48mA     1.193mA
-993mV    1.578mA    2.707mA    966.5uA
-970mV    1.21mA     2.107mA    818.5uA
-924mV    750.8uA    1.296mA    641.3uA
-878mV    507uA      821.4uA    530.2uA
-809mV    327.4uA    430uA      403.3uA
-694mV    178.4uA    161uA      233uA
-464mV    19.89uA    15.19uA    23.61uA
1.1V      0A         0A         0A
[Ramp]
| variable   typ   min   max
dV/dt_r   93.599m/35.273p   94.430m/43.473p   96.210m/28.273p
dV/dt_f   72.904m/44.164p   67.052m/55.104p   73.268m/34.529p
R_load = 50.000
[Rising Waveform]
R_fixture= 50.000
V_fixture= 1.100
V_fixture_min= 1.060
V_fixture_max= 1.170
|time   V(typ)   V(min)   V(max)
0s        978.5mV    948.3mV    1.048V
143ps     978.8mV    948.4mV    1.047V
194ps     975mV      948.6mV    1.119V
210ps     985.7mV    947.8mV    1.134V
265ps     1.061V     942mV      1.159V
303ps     1.082V     978.6mV    1.163V
328ps     1.09V      1.011V     1.166V
361ps     1.095V     1.035V     1.168V
501ps     1.099V     1.058V     1.17V
3ns       1.1V       1.06V      1.17V
[Rising Waveform]
R_fixture= 50.000
V_fixture= 0.0
V_fixture_min= 0.0
V_fixture_max= 0.0
|time   V(typ)   V(min)   V(max)
0s        5.234uV    10.02uV    1.239uV
153ps     -29.96uV   34.45uV    5.035mV
218ps     6.214mV    -11.03uV   180.9mV
269ps     129.9mV    440.1uV    220.7mV
307ps     178.7mV    16.8mV     185.7mV
362ps     201mV      131.8mV    165.8mV
409ps     174.4mV    173.9mV    161.8mV
483ps     158.1mV    189.7mV    160.5mV
678ps     156mV      157.5mV    160.3mV
3ns       156mV      157.4mV    160.3mV
[Falling Waveform]
R_fixture= 50.000
V_fixture= 1.100
V_fixture_min= 1.060
V_fixture_max= 1.170
|time   V(typ)   V(min)   V(max)
0s        1.1V       1.06V      1.17V
158ps     1.1V       1.06V      1.168V
226ps     1.096V     1.06V      1.044V
271ps     1.025V     1.06V      1.005V
319ps     968.8mV    1.054V     1.031V
360ps     946.1mV    1.007V     1.041V
415ps     962.5mV    951.5mV    1.046V
492ps     975.6mV    921.7mV    1.048V
688ps     978.5mV    947.6mV    1.048V
3ns       978.5mV    948.3mV    1.048V
[Falling Waveform]
R_fixture= 50.000
V_fixture= 0.0
V_fixture_min= 0.0
V_fixture_max= 0.0
|time   V(typ)   V(min)   V(max)
0s        156mV      157.4mV    160.3mV
146ps     155.9mV    157.2mV    161.5mV
200ps     159.2mV    157.5mV    50.14mV
265ps     44.41mV    163.2mV    8.845mV
284ps     27.69mV    143.6mV    4.402mV
306ps     15.85mV    102mV      2.091mV
335ps     7.674mV    53.8mV     1.002mV
373ps     2.49mV     21.91mV    391.1uV
514ps     21.9uV     216.7uV    12.65uV
3ns       5.122uV    9.897uV    403.9nV
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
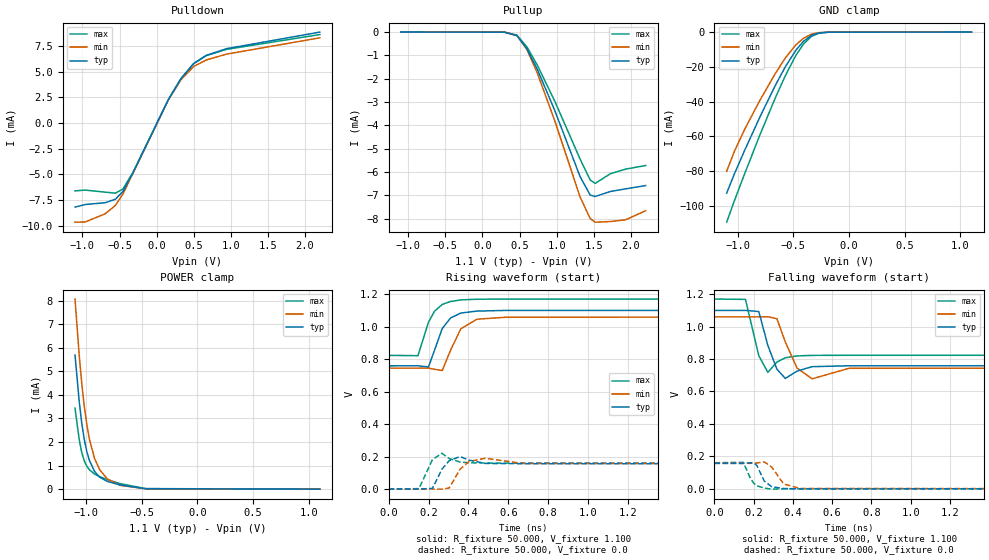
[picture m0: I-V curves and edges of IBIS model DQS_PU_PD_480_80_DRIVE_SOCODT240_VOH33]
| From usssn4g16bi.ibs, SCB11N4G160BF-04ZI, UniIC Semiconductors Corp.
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|   Model DQS_PU_PD_480_80_DRIVE_SOCODT240_VOH33
[Model] DQS_PU_PD_480_80_DRIVE_SOCODT240_VOH33
Model_type I/O
Polarity   Inverting
Vinl =  98.000mV
Vinh =  0.268V
Vmeas =  0.183V
Rref =  50.000
Vref =  0.183V
C_comp   1.020pF   1.010pF   1.030pF
[Model Spec]
Vinh   0.268V   0.262V   0.280V
Vinl   98.000mV   92.000mV   0.110V
Vmeas   0.183V   0.177V   0.195V
Vref   0.183V   0.177V   0.195V
Rref   50.000   NA   NA
[Temperature Range]   25.000   85.000   -40.000
[Voltage Range]   1.100V   1.060V   1.170V
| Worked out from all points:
|   slope of the pulldown table from 0 to 0.165 V, typ, clamps not added: 70.2 ohm
|   GND clamp passes 1 mA (typ) near -0.30 V on its own axis
|   POWER clamp passes 1 mA (typ) near -0.95 V on its own axis
|   rising waveform, R_fixture 50.000, V_fixture 1.100: 20-80 % time 68.2ps typ, 70.6ps min, 65.9ps max; typ from 0.759 V to 1.1 V
|   rising waveform, R_fixture 50.000, V_fixture 0.0: 20-80 % time 34.8ps typ, 42.7ps min, 28.2ps max; typ from 0 V to 0.156 V
|   falling waveform, R_fixture 50.000, V_fixture 1.100: 20-80 % time 43.1ps typ, 53.8ps min, 34.3ps max; typ from 1.1 V to 0.759 V
|   falling waveform, R_fixture 50.000, V_fixture 0.0: 20-80 % time 41.7ps typ, 53.9ps min, 38.4ps max; typ from 0.156 V to 0 V
[Pulldown]
|Voltage   I(typ)   I(min)   I(max)
-1.1V     -8.193mA   -9.666mA   -6.618mA
-964mV    -7.945mA   -9.646mA   -6.54mA
-692mV    -7.769mA   -8.844mA   -6.742mA
-556mV    -7.432mA   -8.032mA   -6.841mA
-454mV    -6.673mA   -6.916mA   -6.44mA
-318mV    -4.841mA   -4.906mA   -4.804mA
158mV     2.257mA    2.237mA    2.267mA
328mV     4.302mA    4.2mA      4.305mA
498mV     5.77mA     5.483mA    5.759mA
668mV     6.567mA    6.118mA    6.54mA
940mV     7.217mA    6.688mA    7.152mA
2.2V      8.836mA    8.278mA    8.595mA
[Pullup]
|Voltage   I(typ)   I(min)   I(max)
-1.1V     500pA      2.606nA    0A
296mV     -2.948uA   -3.529uA   -1.641uA
466mV     -154.8uA   -152.1uA   -129.1uA
602mV     -725.8uA   -765uA     -649.5uA
738mV     -1.585mA   -1.746mA   -1.41mA
976mV     -3.374mA   -3.816mA   -2.972mA
1.316V    -6.198mA   -7.072mA   -5.446mA
1.452V    -6.989mA   -7.995mA   -6.341mA
1.52V     -7.049mA   -8.152mA   -6.489mA
1.724V    -6.835mA   -8.124mA   -6.072mA
1.928V    -6.723mA   -8.051mA   -5.878mA
2.2V      -6.582mA   -7.66mA    -5.721mA
[GND_clamp]
|Voltage   I(typ)   I(min)   I(max)
-1.1V     -92.78mA   -80.14mA   -109.5mA
-1.031V   -81.73mA   -68.77mA   -97.17mA
-939mV    -68.18mA   -56.07mA   -81.64mA
-801mV    -48.85mA   -39.25mA   -59.15mA
-663mV    -30.71mA   -23.84mA   -37.89mA
-571mV    -19.76mA   -14.75mA   -24.85mA
-479mV    -10.5mA    -7.415mA   -13.5mA
-410mV    -5.313mA   -3.546mA   -6.916mA
-341mV    -2.007mA   -1.262mA   -2.59mA
-272mV    -506.9uA   -323.5uA   -609.8uA
-180mV    -45.65uA   -36.06uA   -43.55uA
1.1V      0A         0A         0A
[POWER_clamp]
|Voltage   I(typ)   I(min)   I(max)
-1.1V     5.691mA    8.066mA    3.44mA
-1.062V   3.709mA    5.665mA    2.092mA
-1.039V   2.781mA    4.457mA    1.546mA
-1.016V   2.086mA    3.48mA     1.193mA
-993mV    1.578mA    2.707mA    966.5uA
-970mV    1.21mA     2.107mA    818.5uA
-924mV    750.8uA    1.296mA    641.3uA
-878mV    507uA      821.4uA    530.2uA
-809mV    327.4uA    430uA      403.3uA
-694mV    178.4uA    161uA      233uA
-464mV    19.89uA    15.19uA    23.61uA
1.1V      0A         0A         0A
[Ramp]
| variable   typ   min   max
dV/dt_r   93.600m/34.776p   94.432m/42.636p   96.210m/28.346p
dV/dt_f   0.205/43.144p   0.189/53.781p   0.208/34.326p
R_load = 50.000
[Rising Waveform]
R_fixture= 50.000
V_fixture= 1.100
V_fixture_min= 1.060
V_fixture_max= 1.170
|time   V(typ)   V(min)   V(max)
0s        758.6mV    744.6mV    823.3mV
147ps     759.3mV    745mV      821.4mV
200ps     752.3mV    745.2mV    1.028V
230ps     854.5mV    737.5mV    1.095V
269ps     988.9mV    730.2mV    1.137V
310ps     1.053V     853.7mV    1.155V
362ps     1.084V     986.9mV    1.165V
443ps     1.096V     1.046V     1.169V
587ps     1.1V       1.058V     1.17V
3ns       1.1V       1.06V      1.17V
[Rising Waveform]
R_fixture= 50.000
V_fixture= 0.0
V_fixture_min= 0.0
V_fixture_max= 0.0
|time   V(typ)   V(min)   V(max)
0s        3.731uV    7.145uV    881.9nV
152ps     104.4uV    10.48uV    2.634mV
220ps     4.697mV    274.7uV    182.1mV
267ps     121.9mV    -493.6uV   220.4mV
304ps     175.3mV    7.338mV    187.9mV
358ps     200.2mV    121.8mV    166.4mV
403ps     178.2mV    170.1mV    162mV
484ps     158mV      189.8mV    160.5mV
675ps     156mV      157.6mV    160.3mV
3ns       156mV      157.4mV    160.3mV
[Falling Waveform]
R_fixture= 50.000
V_fixture= 1.100
V_fixture_min= 1.060
V_fixture_max= 1.170
|time   V(typ)   V(min)   V(max)
0s        1.1V       1.06V      1.17V
158ps     1.1V       1.06V      1.168V
226ps     1.093V     1.06V      820.7mV
272ps     884.1mV    1.061V     717.9mV
318ps     737.8mV    1.049V     781.2mV
361ps     680.4mV    905.4mV    807.8mV
421ps     725.8mV    743.9mV    819.3mV
498ps     753mV      678.1mV    822.6mV
686ps     758.5mV    743mV      823.3mV
3ns       758.6mV    744.6mV    823.3mV
[Falling Waveform]
R_fixture= 50.000
V_fixture= 0.0
V_fixture_min= 0.0
V_fixture_max= 0.0
|time   V(typ)   V(min)   V(max)
0s        156mV      157.4mV    160.3mV
147ps     155.8mV    157.2mV    162.8mV
182ps     160.6mV    157mV      67.5mV
200ps     161.2mV    157.3mV    34.08mV
217ps     141.6mV    158.9mV    17.51mV
254ps     47.04mV    165.4mV    4.199mV
292ps     12.06mV    133.5mV    -2.611mV
353ps     1.362mV    28.5mV     -406.4uV
439ps     -878.6uV   1.708mV    -14.81uV
3ns       3.018uV    7.093uV    523nV
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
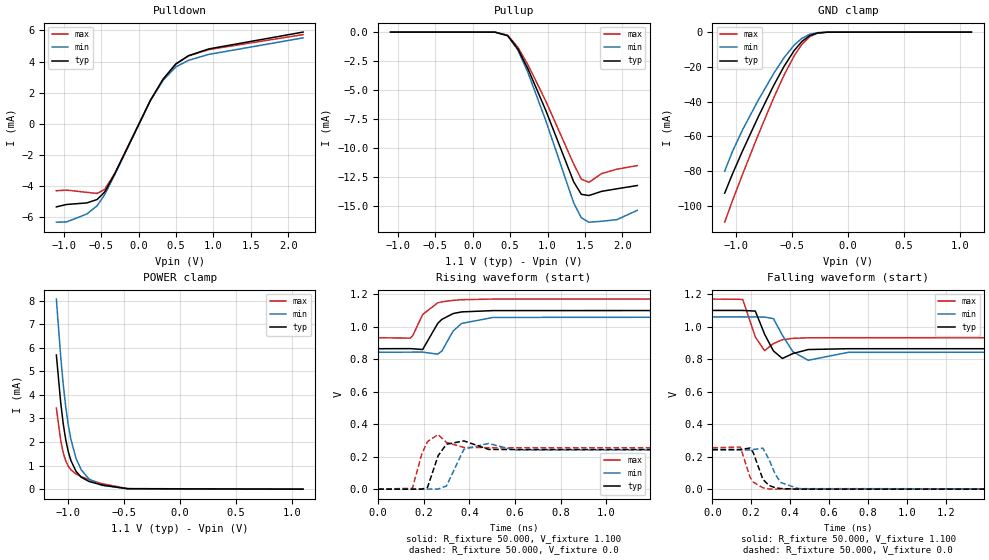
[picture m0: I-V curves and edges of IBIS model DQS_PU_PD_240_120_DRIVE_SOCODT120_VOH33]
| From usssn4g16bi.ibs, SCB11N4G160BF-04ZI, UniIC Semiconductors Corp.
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|   Model DQS_PU_PD_240_120_DRIVE_SOCODT120_VOH33
[Model] DQS_PU_PD_240_120_DRIVE_SOCODT120_VOH33
Model_type I/O
Polarity   Inverting
Vinl =  98.000mV
Vinh =  0.268V
Vmeas =  0.183V
Rref =  50.000
Vref =  0.183V
C_comp   1.020pF   1.010pF   1.030pF
[Model Spec]
Vinh   0.268V   0.262V   0.280V
Vinl   98.000mV   92.000mV   0.110V
Vmeas   0.183V   0.177V   0.195V
Vref   0.183V   0.177V   0.195V
Rref   50.000   NA   NA
[Temperature Range]   25.000   85.000   -40.000
[Voltage Range]   1.100V   1.060V   1.170V
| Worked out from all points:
|   slope of the pulldown table from 0 to 0.165 V, typ, clamps not added: 105 ohm
|   GND clamp passes 1 mA (typ) near -0.30 V on its own axis
|   POWER clamp passes 1 mA (typ) near -0.95 V on its own axis
|   rising waveform, R_fixture 50.000, V_fixture 1.100: 20-80 % time 66.6ps typ, 68.2ps min, 65ps max; typ from 0.864 V to 1.1 V
|   rising waveform, R_fixture 50.000, V_fixture 0.0: 20-80 % time 31.5ps typ, 39ps min, 25.6ps max; typ from 0 V to 0.244 V
|   falling waveform, R_fixture 50.000, V_fixture 1.100: 20-80 % time 43.8ps typ, 54.6ps min, 34.4ps max; typ from 1.1 V to 0.864 V
|   falling waveform, R_fixture 50.000, V_fixture 0.0: 20-80 % time 47.6ps typ, 58.2ps min, 44ps max; typ from 0.244 V to 0 V
[Pulldown]
|Voltage   I(typ)   I(min)   I(max)
-1.1V     -5.34mA    -6.324mA   -4.302mA
-964mV    -5.187mA   -6.308mA   -4.26mA
-692mV    -5.084mA   -5.795mA   -4.408mA
-556mV    -4.87mA    -5.274mA   -4.475mA
-454mV    -4.386mA   -4.558mA   -4.222mA
-318mV    -3.209mA   -3.256mA   -3.18mA
158mV     1.503mA    1.489mA    1.509mA
328mV     2.865mA    2.797mA    2.867mA
498mV     3.844mA    3.653mA    3.837mA
668mV     4.377mA    4.078mA    4.359mA
940mV     4.811mA    4.458mA    4.768mA
2.2V      5.891mA    5.519mA    5.73mA
[Pullup]
|Voltage   I(typ)   I(min)   I(max)
-1.1V     1nA        5.218nA    0A
296mV     -5.896uA   -7.058uA   -3.281uA
466mV     -309.5uA   -304uA     -258.1uA
602mV     -1.45mA    -1.529mA   -1.298mA
738mV     -3.167mA   -3.489mA   -2.817mA
976mV     -6.74mA    -7.622mA   -5.938mA
1.35V     -12.91mA   -14.73mA   -11.38mA
1.452V    -13.99mA   -16.01mA   -12.68mA
1.554V    -14.09mA   -16.39mA   -12.95mA
1.724V    -13.73mA   -16.31mA   -12.2mA
1.928V    -13.51mA   -16.17mA   -11.82mA
2.2V      -13.23mA   -15.37mA   -11.51mA
[GND_clamp]
|Voltage   I(typ)   I(min)   I(max)
-1.1V     -92.78mA   -80.14mA   -109.5mA
-1.031V   -81.73mA   -68.77mA   -97.17mA
-939mV    -68.18mA   -56.07mA   -81.64mA
-801mV    -48.85mA   -39.25mA   -59.15mA
-663mV    -30.71mA   -23.84mA   -37.89mA
-571mV    -19.76mA   -14.75mA   -24.85mA
-479mV    -10.5mA    -7.415mA   -13.5mA
-410mV    -5.313mA   -3.546mA   -6.916mA
-341mV    -2.007mA   -1.262mA   -2.59mA
-272mV    -506.9uA   -323.5uA   -609.8uA
-180mV    -45.65uA   -36.06uA   -43.55uA
1.1V      0A         0A         0A
[POWER_clamp]
|Voltage   I(typ)   I(min)   I(max)
-1.1V     5.691mA    8.066mA    3.44mA
-1.062V   3.709mA    5.665mA    2.092mA
-1.039V   2.781mA    4.457mA    1.546mA
-1.016V   2.086mA    3.48mA     1.193mA
-993mV    1.578mA    2.707mA    966.5uA
-970mV    1.21mA     2.107mA    818.5uA
-924mV    750.8uA    1.296mA    641.3uA
-878mV    507uA      821.4uA    530.2uA
-809mV    327.4uA    430uA      403.3uA
-694mV    178.4uA    161uA      233uA
-464mV    19.89uA    15.19uA    23.61uA
1.1V      0A         0A         0A
[Ramp]
| variable   typ   min   max
dV/dt_r   0.146/31.634p   0.145/39.097p   0.153/25.685p
dV/dt_f   0.141/43.825p   0.130/54.690p   0.143/34.473p
R_load = 50.000
[Rising Waveform]
R_fixture= 50.000
V_fixture= 1.100
V_fixture_min= 1.060
V_fixture_max= 1.170
|time   V(typ)   V(min)   V(max)
0s        864.4mV    842.9mV    932.1mV
140ps     865mV      843.2mV    929.4mV
152ps     864.1mV    843.4mV    946.7mV
195ps     859.3mV    843.4mV    1.075V
261ps     1.02V      830.9mV    1.147V
279ps     1.045V     850mV      1.153V
329ps     1.081V     974mV      1.162V
366ps     1.091V     1.02V      1.166V
504ps     1.099V     1.057V     1.17V
3ns       1.1V       1.06V      1.17V
[Rising Waveform]
R_fixture= 50.000
V_fixture= 0.0
V_fixture_min= 0.0
V_fixture_max= 0.0
|time   V(typ)   V(min)   V(max)
0s        4.355uV    8.339uV    1.03uV
150ps     -33.07uV   35.22uV    5.325mV
191ps     432.3uV    11.25uV    215.1mV
216ps     9.935mV    4.459uV    293mV
263ps     206.2mV    546.7uV    336.3mV
299ps     276.5mV    19.02mV    287.7mV
376ps     296.9mV    246.1mV    256.9mV
484ps     244.6mV    281.6mV    255.1mV
595ps     243.9mV    241.5mV    255mV
3ns       243.9mV    241.2mV    255mV
[Falling Waveform]
R_fixture= 50.000
V_fixture= 1.100
V_fixture_min= 1.060
V_fixture_max= 1.170
|time   V(typ)   V(min)   V(max)
0s        1.1V       1.06V      1.17V
156ps     1.1V       1.06V      1.168V
221ps     1.096V     1.06V      936.8mV
269ps     952.8mV    1.059V     852.1mV
314ps     850.9mV    1.05V      896.3mV
360ps     804.3mV    947.8mV    919.4mV
414ps     834.4mV    846.3mV    928.2mV
493ps     859.2mV    793.1mV    931.4mV
698ps     864.3mV    842mV      932.1mV
3ns       864.4mV    842.9mV    932.1mV
[Falling Waveform]
R_fixture= 50.000
V_fixture= 0.0
V_fixture_min= 0.0
V_fixture_max= 0.0
|time   V(typ)   V(min)   V(max)
0s        243.9mV    241.2mV    255mV
144ps     243.7mV    240.8mV    258.6mV
194ps     252.7mV    241.1mV    72.86mV
210ps     225.6mV    243.5mV    43.25mV
260ps     59.77mV    252.3mV    8.123mV
292ps     22.1mV     181.4mV    451.5uV
324ps     8.17mV     89.87mV    -66.63uV
353ps     3.32mV     39.84mV    -22.28uV
443ps     -463.4uV   2.922mV    617.9nV
3ns       3.161uV    8.189uV    -795.7nV
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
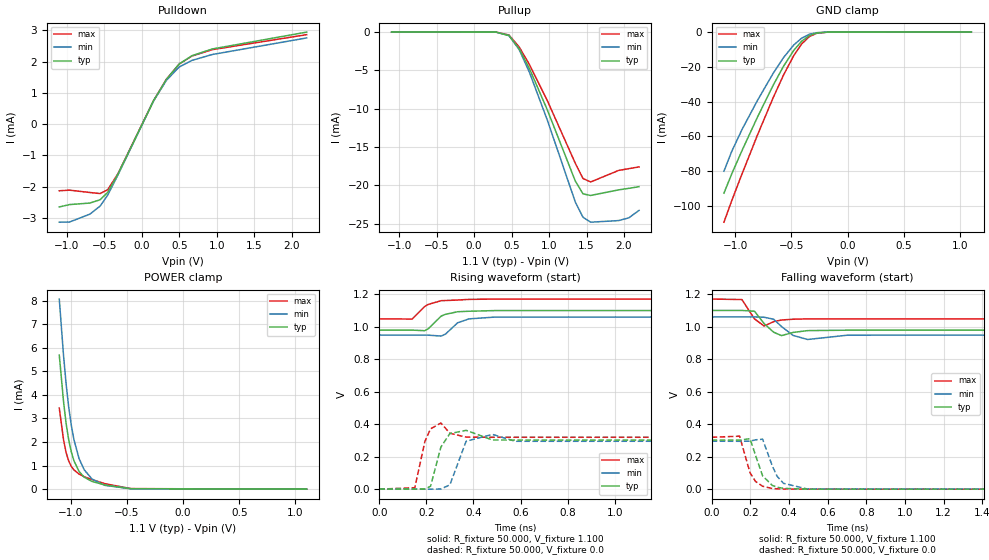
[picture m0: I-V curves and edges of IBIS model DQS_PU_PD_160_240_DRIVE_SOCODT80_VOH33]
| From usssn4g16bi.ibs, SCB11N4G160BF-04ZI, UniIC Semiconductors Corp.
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|   Model DQS_PU_PD_160_240_DRIVE_SOCODT80_VOH33
[Model] DQS_PU_PD_160_240_DRIVE_SOCODT80_VOH33
Model_type I/O
Polarity   Inverting
Vinl =  98.000mV
Vinh =  0.268V
Vmeas =  0.183V
Rref =  50.000
Vref =  0.183V
C_comp   1.020pF   1.010pF   1.030pF
[Model Spec]
Vinh   0.268V   0.262V   0.280V
Vinl   98.000mV   92.000mV   0.110V
Vmeas   0.183V   0.177V   0.195V
Vref   0.183V   0.177V   0.195V
Rref   50.000   NA   NA
[Temperature Range]   25.000   85.000   -40.000
[Voltage Range]   1.100V   1.060V   1.170V
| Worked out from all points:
|   slope of the pulldown table from 0 to 0.165 V, typ, clamps not added: 211 ohm
|   GND clamp passes 1 mA (typ) near -0.30 V on its own axis
|   POWER clamp passes 1 mA (typ) near -0.95 V on its own axis
|   rising waveform, R_fixture 50.000, V_fixture 1.100: 20-80 % time 61.8ps typ, 60.4ps min, 61.8ps max; typ from 0.978 V to 1.1 V
|   rising waveform, R_fixture 50.000, V_fixture 0.0: 20-80 % time 29.7ps typ, 36.7ps min, 23.9ps max; typ from 0 V to 0.302 V
|   falling waveform, R_fixture 50.000, V_fixture 1.100: 20-80 % time 45.5ps typ, 58.8ps min, 35ps max; typ from 1.1 V to 0.978 V
|   falling waveform, R_fixture 50.000, V_fixture 0.0: 20-80 % time 55.5ps typ, 62.4ps min, 52.6ps max; typ from 0.302 V to 0 V
[Pulldown]
|Voltage   I(typ)   I(min)   I(max)
-1.1V     -2.652mA   -3.14mA    -2.134mA
-964mV    -2.576mA   -3.135mA   -2.114mA
-692mV    -2.527mA   -2.882mA   -2.189mA
-556mV    -2.422mA   -2.626mA   -2.223mA
-454mV    -2.185mA   -2.274mA   -2.101mA
-318mV    -1.604mA   -1.629mA   -1.589mA
158mV     752.2uA    745.4uA    755.4uA
328mV     1.434mA    1.4mA      1.435mA
498mV     1.924mA    1.828mA    1.92mA
668mV     2.19mA     2.04mA     2.18mA
940mV     2.407mA    2.23mA     2.385mA
2.2V      2.948mA    2.761mA    2.866mA
[Pullup]
|Voltage   I(typ)   I(min)   I(max)
-1.1V     1.606nA    7.718nA    0A
296mV     -8.845uA   -10.59uA   -4.922uA
466mV     -464.7uA   -456.5uA   -387.5uA
602mV     -2.18mA    -2.299mA   -1.951mA
738mV     -4.764mA   -5.249mA   -4.236mA
976mV     -10.14mA   -11.47mA   -8.932mA
1.35V     -19.45mA   -22.19mA   -17.13mA
1.452V    -21.12mA   -24.17mA   -19.11mA
1.554V    -21.33mA   -24.82mA   -19.57mA
1.928V    -20.6mA    -24.61mA   -18.06mA
2.064V    -20.4mA    -24.25mA   -17.83mA
2.2V      -20.18mA   -23.28mA   -17.6mA
[GND_clamp]
|Voltage   I(typ)   I(min)   I(max)
-1.1V     -92.78mA   -80.14mA   -109.5mA
-1.031V   -81.73mA   -68.77mA   -97.17mA
-939mV    -68.18mA   -56.07mA   -81.64mA
-801mV    -48.85mA   -39.25mA   -59.15mA
-663mV    -30.71mA   -23.84mA   -37.89mA
-571mV    -19.76mA   -14.75mA   -24.85mA
-479mV    -10.5mA    -7.415mA   -13.5mA
-410mV    -5.313mA   -3.546mA   -6.916mA
-341mV    -2.007mA   -1.262mA   -2.59mA
-272mV    -506.9uA   -323.5uA   -609.8uA
-180mV    -45.65uA   -36.06uA   -43.55uA
1.1V      0A         0A         0A
[POWER_clamp]
|Voltage   I(typ)   I(min)   I(max)
-1.1V     5.691mA    8.066mA    3.44mA
-1.062V   3.709mA    5.665mA    2.092mA
-1.039V   2.781mA    4.457mA    1.546mA
-1.016V   2.086mA    3.48mA     1.193mA
-993mV    1.578mA    2.707mA    966.5uA
-970mV    1.21mA     2.107mA    818.5uA
-924mV    750.8uA    1.296mA    641.3uA
-878mV    507uA      821.4uA    530.2uA
-809mV    327.4uA    430uA      403.3uA
-694mV    178.4uA    161uA      233uA
-464mV    19.89uA    15.19uA    23.61uA
1.1V      0A         0A         0A
[Ramp]
| variable   typ   min   max
dV/dt_r   0.181/29.827p   0.177/36.786p   0.192/24.123p
dV/dt_f   72.904m/45.570p   67.052m/58.753p   73.268m/35.048p
R_load = 50.000
[Rising Waveform]
R_fixture= 50.000
V_fixture= 1.100
V_fixture_min= 1.060
V_fixture_max= 1.170
|time   V(typ)   V(min)   V(max)
0s        978.5mV    948.3mV    1.048V
140ps     978.8mV    948.4mV    1.047V
193ps     975.3mV    948.6mV    1.124V
208ps     986.8mV    947.7mV    1.137V
263ps     1.065V     942.4mV    1.16V
281ps     1.076V     953.8mV    1.161V
333ps     1.092V     1.024V     1.164V
381ps     1.095V     1.048V     1.168V
490ps     1.099V     1.059V     1.17V
3ns       1.1V       1.06V      1.17V
[Rising Waveform]
R_fixture= 50.000
V_fixture= 0.0
V_fixture_min= 0.0
V_fixture_max= 0.0
|time   V(typ)   V(min)   V(max)
0s        5.234uV    10.02uV    1.239uV
151ps     -194.2uV   55.16uV    8.497mV
194ps     1.149mV    -86.39uV   293.7mV
218ps     17.47mV    -287.5uV   371.2mV
262ps     259.3mV    877.5uV    406.8mV
300ps     342mV      26.18mV    344.1mV
369ps     362.1mV    294.8mV    320.1mV
481ps     302.1mV    336.9mV    319.2mV
578ps     302.1mV    294.4mV    319.2mV
3ns       302.1mV    295.1mV    319.2mV
[Falling Waveform]
R_fixture= 50.000
V_fixture= 1.100
V_fixture_min= 1.060
V_fixture_max= 1.170
|time   V(typ)   V(min)   V(max)
0s        1.1V       1.06V      1.17V
157ps     1.1V       1.06V      1.167V
222ps     1.095V     1.06V      1.048V
272ps     1.019V     1.058V     1.004V
321ps     966.1mV    1.046V     1.031V
362ps     945mV      1.001V     1.041V
422ps     964.7mV    946mV      1.046V
497ps     975.8mV    921.2mV    1.048V
704ps     978.5mV    947.8mV    1.048V
3ns       978.5mV    948.3mV    1.048V
[Falling Waveform]
R_fixture= 50.000
V_fixture= 0.0
V_fixture_min= 0.0
V_fixture_max= 0.0
|time   V(typ)   V(min)   V(max)
0s        302.1mV    295.1mV    319.2mV
145ps     301.6mV    294.7mV    326.1mV
199ps     311mV      295.4mV    100.6mV
227ps     210.1mV    303.7mV    48.04mV
264ps     81.91mV    307.6mV    17.91mV
314ps     23.08mV    143.4mV    4.163mV
339ps     12.3mV     79.53mV    2.233mV
372ps     4.912mV    35.89mV    981.9uV
493ps     151.3uV    1.75mV     47.71uV
3ns       5.238uV    9.908uV    497.2nV
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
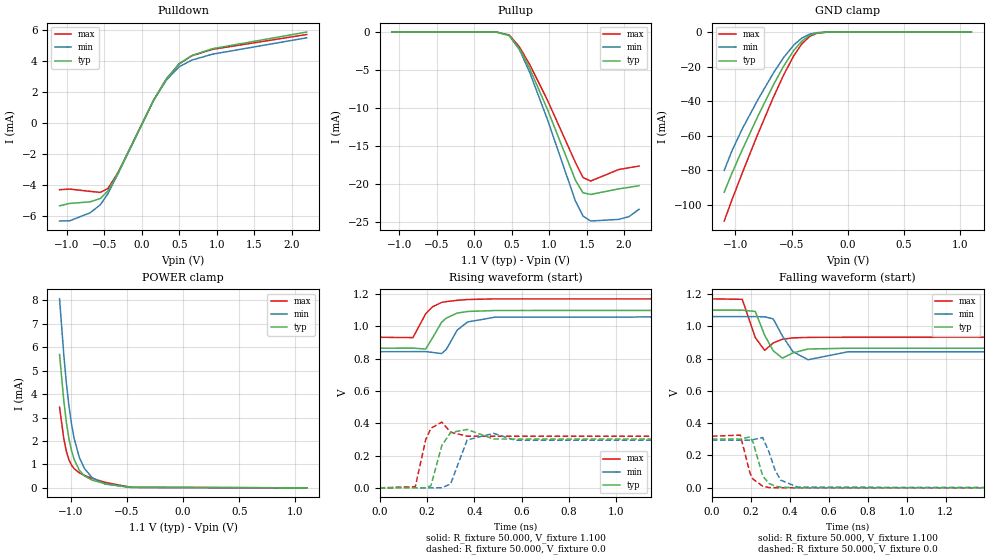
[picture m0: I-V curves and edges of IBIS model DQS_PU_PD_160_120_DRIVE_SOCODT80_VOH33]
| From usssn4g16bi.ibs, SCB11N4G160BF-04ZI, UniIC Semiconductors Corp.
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|   Model DQS_PU_PD_160_120_DRIVE_SOCODT80_VOH33
[Model] DQS_PU_PD_160_120_DRIVE_SOCODT80_VOH33
Model_type I/O
Polarity   Inverting
Vinl =  98.000mV
Vinh =  0.268V
Vmeas =  0.183V
Rref =  50.000
Vref =  0.183V
C_comp   1.020pF   1.010pF   1.030pF
[Model Spec]
Vinh   0.268V   0.262V   0.280V
Vinl   98.000mV   92.000mV   0.110V
Vmeas   0.183V   0.177V   0.195V
Vref   0.183V   0.177V   0.195V
Rref   50.000   NA   NA
[Temperature Range]   25.000   85.000   -40.000
[Voltage Range]   1.100V   1.060V   1.170V
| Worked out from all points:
|   slope of the pulldown table from 0 to 0.165 V, typ, clamps not added: 105 ohm
|   GND clamp passes 1 mA (typ) near -0.30 V on its own axis
|   POWER clamp passes 1 mA (typ) near -0.95 V on its own axis
|   rising waveform, R_fixture 50.000, V_fixture 1.100: 20-80 % time 65ps typ, 65.7ps min, 64.1ps max; typ from 0.864 V to 1.1 V
|   rising waveform, R_fixture 50.000, V_fixture 0.0: 20-80 % time 29.5ps typ, 36.3ps min, 23.8ps max; typ from 0 V to 0.302 V
|   falling waveform, R_fixture 50.000, V_fixture 1.100: 20-80 % time 44ps typ, 55.5ps min, 34.4ps max; typ from 1.1 V to 0.864 V
|   falling waveform, R_fixture 50.000, V_fixture 0.0: 20-80 % time 46.6ps typ, 56.7ps min, 43.2ps max; typ from 0.302 V to 0 V
[Pulldown]
|Voltage   I(typ)   I(min)   I(max)
-1.1V     -5.34mA    -6.324mA   -4.302mA
-964mV    -5.187mA   -6.308mA   -4.26mA
-692mV    -5.084mA   -5.795mA   -4.408mA
-556mV    -4.87mA    -5.274mA   -4.475mA
-454mV    -4.386mA   -4.558mA   -4.222mA
-318mV    -3.209mA   -3.256mA   -3.18mA
158mV     1.503mA    1.489mA    1.509mA
328mV     2.865mA    2.797mA    2.867mA
498mV     3.844mA    3.653mA    3.837mA
668mV     4.377mA    4.078mA    4.359mA
940mV     4.811mA    4.458mA    4.768mA
2.2V      5.891mA    5.519mA    5.73mA
[Pullup]
|Voltage   I(typ)   I(min)   I(max)
-1.1V     1.606nA    7.718nA    0A
296mV     -8.845uA   -10.59uA   -4.922uA
466mV     -464.7uA   -456.5uA   -387.5uA
602mV     -2.18mA    -2.299mA   -1.951mA
738mV     -4.764mA   -5.249mA   -4.236mA
976mV     -10.14mA   -11.47mA   -8.932mA
1.35V     -19.45mA   -22.19mA   -17.13mA
1.452V    -21.12mA   -24.17mA   -19.11mA
1.554V    -21.33mA   -24.82mA   -19.57mA
1.928V    -20.6mA    -24.61mA   -18.06mA
2.064V    -20.4mA    -24.25mA   -17.83mA
2.2V      -20.18mA   -23.28mA   -17.6mA
[GND_clamp]
|Voltage   I(typ)   I(min)   I(max)
-1.1V     -92.78mA   -80.14mA   -109.5mA
-1.031V   -81.73mA   -68.77mA   -97.17mA
-939mV    -68.18mA   -56.07mA   -81.64mA
-801mV    -48.85mA   -39.25mA   -59.15mA
-663mV    -30.71mA   -23.84mA   -37.89mA
-571mV    -19.76mA   -14.75mA   -24.85mA
-479mV    -10.5mA    -7.415mA   -13.5mA
-410mV    -5.313mA   -3.546mA   -6.916mA
-341mV    -2.007mA   -1.262mA   -2.59mA
-272mV    -506.9uA   -323.5uA   -609.8uA
-180mV    -45.65uA   -36.06uA   -43.55uA
1.1V      0A         0A         0A
[POWER_clamp]
|Voltage   I(typ)   I(min)   I(max)
-1.1V     5.691mA    8.066mA    3.44mA
-1.062V   3.709mA    5.665mA    2.092mA
-1.039V   2.781mA    4.457mA    1.546mA
-1.016V   2.086mA    3.48mA     1.193mA
-993mV    1.578mA    2.707mA    966.5uA
-970mV    1.21mA     2.107mA    818.5uA
-924mV    750.8uA    1.296mA    641.3uA
-878mV    507uA      821.4uA    530.2uA
-809mV    327.4uA    430uA      403.3uA
-694mV    178.4uA    161uA      233uA
-464mV    19.89uA    15.19uA    23.61uA
1.1V      0A         0A         0A
[Ramp]
| variable   typ   min   max
dV/dt_r   0.181/29.597p   0.177/36.386p   0.192/23.991p
dV/dt_f   0.141/44.087p   0.130/55.501p   0.143/34.475p
R_load = 50.000
[Rising Waveform]
R_fixture= 50.000
V_fixture= 1.100
V_fixture_min= 1.060
V_fixture_max= 1.170
|time   V(typ)   V(min)   V(max)
0s        864.4mV    842.9mV    932.1mV
141ps     865mV      843.2mV    930.1mV
195ps     859.4mV    843.4mV    1.078V
223ps     926.9mV    838.6mV    1.12V
262ps     1.025V     831.2mV    1.148V
282ps     1.051V     857.3mV    1.153V
328ps     1.082V     976.8mV    1.161V
372ps     1.092V     1.027V     1.166V
489ps     1.098V     1.057V     1.17V
3ns       1.1V       1.06V      1.17V
[Rising Waveform]
R_fixture= 50.000
V_fixture= 0.0
V_fixture_min= 0.0
V_fixture_max= 0.0
|time   V(typ)   V(min)   V(max)
0s        4.355uV    8.339uV    1.03uV
151ps     -98.45uV   44.18uV    7.252mV
195ps     798.1uV    -27.71uV   298.1mV
217ps     12.99mV    -105.5uV   369mV
263ps     262mV      537.2uV    406.8mV
300ps     342.1mV    23.38mV    344.3mV
370ps     361.4mV    296.4mV    320mV
482ps     302.1mV    337mV      319.2mV
574ps     302.1mV    294.5mV    319.2mV
3ns       302.1mV    295.1mV    319.2mV
[Falling Waveform]
R_fixture= 50.000
V_fixture= 1.100
V_fixture_min= 1.060
V_fixture_max= 1.170
|time   V(typ)   V(min)   V(max)
0s        1.1V       1.06V      1.17V
156ps     1.1V       1.06V      1.167V
223ps     1.092V     1.06V      930mV
271ps     944.6mV    1.059V     851.5mV
315ps     848.7mV    1.046V     897mV
362ps     803mV      940.8mV    919.9mV
416ps     835.5mV    843.3mV    928.4mV
494ps     859.3mV    792.8mV    931.4mV
698ps     864.3mV    842mV      932.1mV
3ns       864.4mV    842.9mV    932.1mV
[Falling Waveform]
R_fixture= 50.000
V_fixture= 0.0
V_fixture_min= 0.0
V_fixture_max= 0.0
|time   V(typ)   V(min)   V(max)
0s        302.1mV    295.1mV    319.2mV
146ps     301.7mV    294.7mV    326.1mV
196ps     315mV      294.9mV    89.52mV
212ps     280.2mV    298.3mV    52.96mV
261ps     73.59mV    311.1mV    10.22mV
293ps     27.08mV    222.8mV    1.247mV
325ps     10mV       108mV      266.6uV
354ps     4.027mV    47.03mV    115.2uV
442ps     -421.2uV   3.581mV    9.786uV
3ns       4.2uV      8.12uV     989.4nV
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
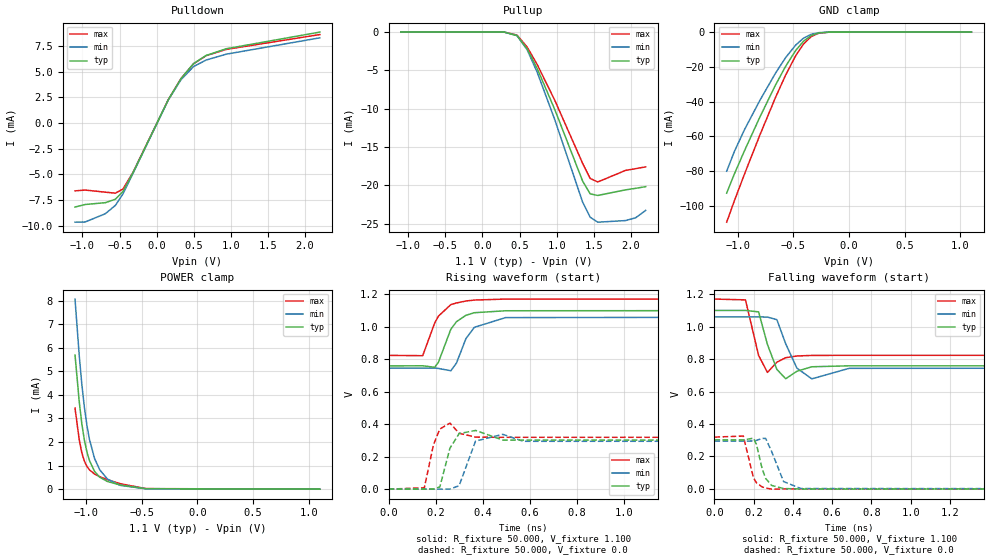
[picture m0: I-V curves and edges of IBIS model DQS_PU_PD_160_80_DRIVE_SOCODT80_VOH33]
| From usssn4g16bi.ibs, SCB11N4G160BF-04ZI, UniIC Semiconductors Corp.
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|   Model DQS_PU_PD_160_80_DRIVE_SOCODT80_VOH33
[Model] DQS_PU_PD_160_80_DRIVE_SOCODT80_VOH33
Model_type I/O
Polarity   Inverting
Vinl =  98.000mV
Vinh =  0.268V
Vmeas =  0.183V
Rref =  50.000
Vref =  0.183V
C_comp   1.020pF   1.010pF   1.030pF
[Model Spec]
Vinh   0.268V   0.262V   0.280V
Vinl   98.000mV   92.000mV   0.110V
Vmeas   0.183V   0.177V   0.195V
Vref   0.183V   0.177V   0.195V
Rref   50.000   NA   NA
[Temperature Range]   25.000   85.000   -40.000
[Voltage Range]   1.100V   1.060V   1.170V
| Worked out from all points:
|   slope of the pulldown table from 0 to 0.165 V, typ, clamps not added: 70.2 ohm
|   GND clamp passes 1 mA (typ) near -0.30 V on its own axis
|   POWER clamp passes 1 mA (typ) near -0.95 V on its own axis
|   rising waveform, R_fixture 50.000, V_fixture 1.100: 20-80 % time 67ps typ, 68.6ps min, 65.4ps max; typ from 0.759 V to 1.1 V
|   rising waveform, R_fixture 50.000, V_fixture 0.0: 20-80 % time 29.4ps typ, 36.2ps min, 23.9ps max; typ from 0 V to 0.302 V
|   falling waveform, R_fixture 50.000, V_fixture 1.100: 20-80 % time 43.6ps typ, 54.7ps min, 34.5ps max; typ from 1.1 V to 0.759 V
|   falling waveform, R_fixture 50.000, V_fixture 0.0: 20-80 % time 41.6ps typ, 54.5ps min, 37.5ps max; typ from 0.302 V to 0 V
[Pulldown]
|Voltage   I(typ)   I(min)   I(max)
-1.1V     -8.193mA   -9.666mA   -6.618mA
-964mV    -7.945mA   -9.646mA   -6.54mA
-692mV    -7.769mA   -8.844mA   -6.742mA
-556mV    -7.432mA   -8.032mA   -6.841mA
-454mV    -6.673mA   -6.916mA   -6.44mA
-318mV    -4.841mA   -4.906mA   -4.804mA
158mV     2.257mA    2.237mA    2.267mA
328mV     4.302mA    4.2mA      4.305mA
498mV     5.77mA     5.483mA    5.759mA
668mV     6.567mA    6.118mA    6.54mA
940mV     7.217mA    6.688mA    7.152mA
2.2V      8.836mA    8.278mA    8.595mA
[Pullup]
|Voltage   I(typ)   I(min)   I(max)
-1.1V     1.606nA    7.718nA    0A
296mV     -8.845uA   -10.59uA   -4.922uA
466mV     -464.7uA   -456.5uA   -387.5uA
602mV     -2.18mA    -2.299mA   -1.951mA
738mV     -4.764mA   -5.249mA   -4.236mA
976mV     -10.14mA   -11.47mA   -8.932mA
1.35V     -19.45mA   -22.19mA   -17.13mA
1.452V    -21.12mA   -24.17mA   -19.11mA
1.554V    -21.33mA   -24.82mA   -19.57mA
1.928V    -20.6mA    -24.61mA   -18.06mA
2.064V    -20.4mA    -24.25mA   -17.83mA
2.2V      -20.18mA   -23.28mA   -17.6mA
[GND_clamp]
|Voltage   I(typ)   I(min)   I(max)
-1.1V     -92.78mA   -80.14mA   -109.5mA
-1.031V   -81.73mA   -68.77mA   -97.17mA
-939mV    -68.18mA   -56.07mA   -81.64mA
-801mV    -48.85mA   -39.25mA   -59.15mA
-663mV    -30.71mA   -23.84mA   -37.89mA
-571mV    -19.76mA   -14.75mA   -24.85mA
-479mV    -10.5mA    -7.415mA   -13.5mA
-410mV    -5.313mA   -3.546mA   -6.916mA
-341mV    -2.007mA   -1.262mA   -2.59mA
-272mV    -506.9uA   -323.5uA   -609.8uA
-180mV    -45.65uA   -36.06uA   -43.55uA
1.1V      0A         0A         0A
[POWER_clamp]
|Voltage   I(typ)   I(min)   I(max)
-1.1V     5.691mA    8.066mA    3.44mA
-1.062V   3.709mA    5.665mA    2.092mA
-1.039V   2.781mA    4.457mA    1.546mA
-1.016V   2.086mA    3.48mA     1.193mA
-993mV    1.578mA    2.707mA    966.5uA
-970mV    1.21mA     2.107mA    818.5uA
-924mV    750.8uA    1.296mA    641.3uA
-878mV    507uA      821.4uA    530.2uA
-809mV    327.4uA    430uA      403.3uA
-694mV    178.4uA    161uA      233uA
-464mV    19.89uA    15.19uA    23.61uA
1.1V      0A         0A         0A
[Ramp]
| variable   typ   min   max
dV/dt_r   0.181/29.506p   0.177/36.237p   0.192/23.990p
dV/dt_f   0.205/43.637p   0.189/54.581p   0.208/34.598p
R_load = 50.000
[Rising Waveform]
R_fixture= 50.000
V_fixture= 1.100
V_fixture_min= 1.060
V_fixture_max= 1.170
|time   V(typ)   V(min)   V(max)
0s        758.6mV    744.6mV    823.3mV
145ps     759.4mV    745mV      821.6mV
196ps     750.2mV    745.4mV    1.022V
212ps     781.5mV    742.9mV    1.065V
265ps     984.9mV    728.8mV    1.136V
289ps     1.031V     777mV      1.146V
329ps     1.07V      926.4mV    1.158V
365ps     1.086V     996.2mV    1.164V
498ps     1.098V     1.056V     1.17V
3ns       1.1V       1.06V      1.17V
[Rising Waveform]
R_fixture= 50.000
V_fixture= 0.0
V_fixture_min= 0.0
V_fixture_max= 0.0
|time   V(typ)   V(min)   V(max)
0s        3.731uV    7.145uV    881.9nV
152ps     -68.26uV   29.21uV    8.595mV
191ps     585.6uV    -126nV     274.2mV
218ps     13.72mV    16.89uV    370.3mV
261ps     252.4mV    460.9uV    406.5mV
300ps     341.7mV    21.11mV    344.3mV
370ps     361.5mV    296mV      320mV
486ps     302.1mV    337.4mV    319.2mV
573ps     302.1mV    294.5mV    319.2mV
3ns       302.1mV    295.1mV    319.2mV
[Falling Waveform]
R_fixture= 50.000
V_fixture= 1.100
V_fixture_min= 1.060
V_fixture_max= 1.170
|time   V(typ)   V(min)   V(max)
0s        1.1V       1.06V      1.17V
158ps     1.1V       1.06V      1.165V
225ps     1.091V     1.06V      822.4mV
270ps     890.2mV    1.059V     717.6mV
318ps     736.7mV    1.043V     781mV
363ps     678.9mV    894.3mV    808.4mV
420ps     725mV      744.4mV    819.2mV
496ps     752.7mV    678.1mV    822.6mV
686ps     758.5mV    743mV      823.3mV
3ns       758.6mV    744.6mV    823.3mV
[Falling Waveform]
R_fixture= 50.000
V_fixture= 0.0
V_fixture_min= 0.0
V_fixture_max= 0.0
|time   V(typ)   V(min)   V(max)
0s        302.1mV    295.1mV    319.2mV
147ps     301.7mV    294.7mV    325.5mV
199ps     312.6mV    295.3mV    67.85mV
214ps     274.2mV    298.8mV    37.41mV
243ps     124.1mV    311.1mV    11.96mV
261ps     64.3mV     310.8mV    5.517mV
291ps     21.34mV    231.7mV    -1.729mV
352ps     2.299mV    45.43mV    -326.7uV
439ps     -836.7uV   2.422mV    -11.04uV
3ns       843.1nV    7.035uV    509.2nV
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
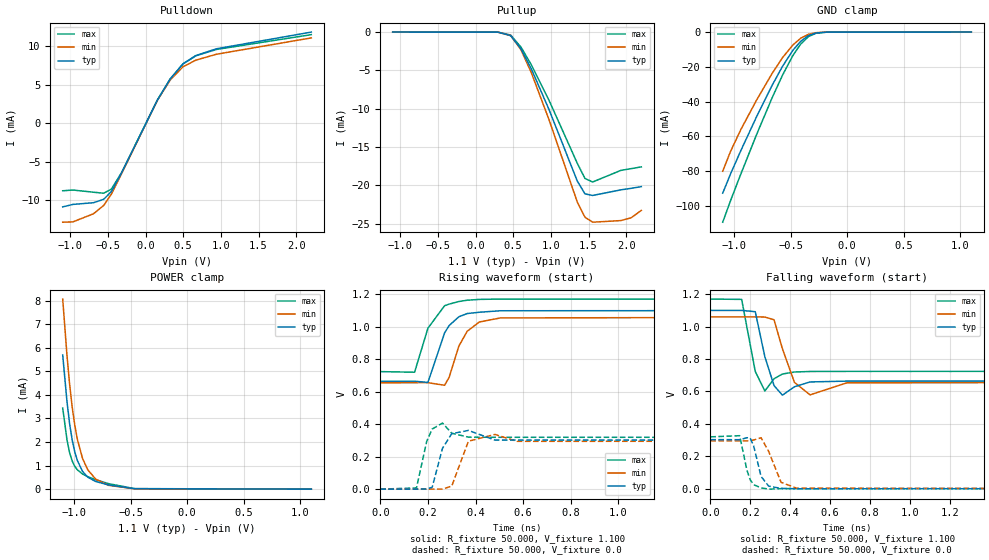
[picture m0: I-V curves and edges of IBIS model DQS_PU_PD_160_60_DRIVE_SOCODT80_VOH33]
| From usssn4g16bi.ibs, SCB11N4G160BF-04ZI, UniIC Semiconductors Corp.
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|   Model DQS_PU_PD_160_60_DRIVE_SOCODT80_VOH33
[Model] DQS_PU_PD_160_60_DRIVE_SOCODT80_VOH33
Model_type I/O
Polarity   Inverting
Vinl =  98.000mV
Vinh =  0.268V
Vmeas =  0.183V
Rref =  50.000
Vref =  0.183V
C_comp   1.020pF   1.010pF   1.030pF
[Model Spec]
Vinh   0.268V   0.262V   0.280V
Vinl   98.000mV   92.000mV   0.110V
Vmeas   0.183V   0.177V   0.195V
Vref   0.183V   0.177V   0.195V
Rref   50.000   NA   NA
[Temperature Range]   25.000   85.000   -40.000
[Voltage Range]   1.100V   1.060V   1.170V
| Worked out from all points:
|   slope of the pulldown table from 0 to 0.165 V, typ, clamps not added: 52.7 ohm
|   GND clamp passes 1 mA (typ) near -0.30 V on its own axis
|   POWER clamp passes 1 mA (typ) near -0.95 V on its own axis
|   rising waveform, R_fixture 50.000, V_fixture 1.100: 20-80 % time 68ps typ, 70.1ps min, 65.9ps max; typ from 0.663 V to 1.1 V
|   rising waveform, R_fixture 50.000, V_fixture 0.0: 20-80 % time 29.3ps typ, 36ps min, 23.8ps max; typ from 0 V to 0.302 V
|   falling waveform, R_fixture 50.000, V_fixture 1.100: 20-80 % time 42.7ps typ, 53.7ps min, 33.9ps max; typ from 1.1 V to 0.663 V
|   falling waveform, R_fixture 50.000, V_fixture 0.0: 20-80 % time 37.6ps typ, 52.7ps min, 33ps max; typ from 0.302 V to 0 V
[Pulldown]
|Voltage   I(typ)   I(min)   I(max)
-1.1V     -10.83mA   -12.81mA   -8.746mA
-964mV    -10.51mA   -12.77mA   -8.65mA
-692mV    -10.29mA   -11.72mA   -8.932mA
-556mV    -9.849mA   -10.65mA   -9.063mA
-454mV    -8.849mA   -9.178mA   -8.534mA
-318mV    -6.436mA   -6.525mA   -6.383mA
158mV     3.005mA    2.979mA    3.019mA
328mV     5.729mA    5.594mA    5.734mA
498mV     7.686mA    7.305mA    7.672mA
668mV     8.751mA    8.153mA    8.715mA
940mV     9.618mA    8.913mA    9.532mA
2.2V      11.78mA    11.03mA    11.45mA
[Pullup]
|Voltage   I(typ)   I(min)   I(max)
-1.1V     1.606nA    7.718nA    0A
296mV     -8.845uA   -10.59uA   -4.922uA
466mV     -464.7uA   -456.5uA   -387.5uA
602mV     -2.18mA    -2.299mA   -1.951mA
738mV     -4.764mA   -5.249mA   -4.236mA
976mV     -10.14mA   -11.47mA   -8.932mA
1.35V     -19.45mA   -22.19mA   -17.13mA
1.452V    -21.12mA   -24.17mA   -19.11mA
1.554V    -21.33mA   -24.82mA   -19.57mA
1.928V    -20.6mA    -24.61mA   -18.06mA
2.064V    -20.4mA    -24.25mA   -17.83mA
2.2V      -20.18mA   -23.28mA   -17.6mA
[GND_clamp]
|Voltage   I(typ)   I(min)   I(max)
-1.1V     -92.78mA   -80.14mA   -109.5mA
-1.031V   -81.73mA   -68.77mA   -97.17mA
-939mV    -68.18mA   -56.07mA   -81.64mA
-801mV    -48.85mA   -39.25mA   -59.15mA
-663mV    -30.71mA   -23.84mA   -37.89mA
-571mV    -19.76mA   -14.75mA   -24.85mA
-479mV    -10.5mA    -7.415mA   -13.5mA
-410mV    -5.313mA   -3.546mA   -6.916mA
-341mV    -2.007mA   -1.262mA   -2.59mA
-272mV    -506.9uA   -323.5uA   -609.8uA
-180mV    -45.65uA   -36.06uA   -43.55uA
1.1V      0A         0A         0A
[POWER_clamp]
|Voltage   I(typ)   I(min)   I(max)
-1.1V     5.691mA    8.066mA    3.44mA
-1.062V   3.709mA    5.665mA    2.092mA
-1.039V   2.781mA    4.457mA    1.546mA
-1.016V   2.086mA    3.48mA     1.193mA
-993mV    1.578mA    2.707mA    966.5uA
-970mV    1.21mA     2.107mA    818.5uA
-924mV    750.8uA    1.296mA    641.3uA
-878mV    507uA      821.4uA    530.2uA
-809mV    327.4uA    430uA      403.3uA
-694mV    178.4uA    161uA      233uA
-464mV    19.89uA    15.19uA    23.61uA
1.1V      0A         0A         0A
[Ramp]
| variable   typ   min   max
dV/dt_r   0.181/29.310p   0.177/36.122p   0.192/23.883p
dV/dt_f   0.262/42.697p   0.243/53.687p   0.268/33.991p
R_load = 50.000
[Rising Waveform]
R_fixture= 50.000
V_fixture= 1.100
V_fixture_min= 1.060
V_fixture_max= 1.170
|time   V(typ)   V(min)   V(max)
0s        663.5mV    654.8mV    723.5mV
144ps     664.5mV    655.2mV    719.7mV
200ps     657mV      655.5mV    990.7mV
270ps     961.8mV    639.3mV    1.129V
289ps     1.007V     688.3mV    1.139V
330ps     1.061V     881.1mV    1.155V
365ps     1.081V     972mV      1.163V
416ps     1.089V     1.029V     1.168V
505ps     1.098V     1.054V     1.17V
3ns       1.1V       1.06V      1.17V
[Rising Waveform]
R_fixture= 50.000
V_fixture= 0.0
V_fixture_min= 0.0
V_fixture_max= 0.0
|time   V(typ)   V(min)   V(max)
0s        3.261uV    6.245uV    770.5nV
152ps     2.993uV    26.06uV    7.731mV
195ps     777.5uV    22.26uV    295.1mV
218ps     12.05mV    135.3uV    370.2mV
261ps     251mV      513.9uV    406.7mV
300ps     341.5mV    18.94mV    344.4mV
370ps     361.5mV    294.9mV    320.1mV
481ps     302.1mV    336.9mV    319.2mV
574ps     302.1mV    294.5mV    319.2mV
3ns       302.1mV    295.1mV    319.2mV
[Falling Waveform]
R_fixture= 50.000
V_fixture= 1.100
V_fixture_min= 1.060
V_fixture_max= 1.170
|time   V(typ)   V(min)   V(max)
0s        1.1V       1.06V      1.17V
157ps     1.1V       1.06V      1.168V
225ps     1.092V     1.06V      723.2mV
273ps     814mV      1.059V     602.5mV
319ps     635.7mV    1.042V     678.1mV
361ps     576.7mV    862.6mV    707.4mV
421ps     628.6mV    655.5mV    719.7mV
499ps     658.3mV    578.5mV    722.9mV
684ps     663.4mV    653.2mV    723.5mV
3ns       663.5mV    654.8mV    723.5mV
[Falling Waveform]
R_fixture= 50.000
V_fixture= 0.0
V_fixture_min= 0.0
V_fixture_max= 0.0
|time   V(typ)   V(min)   V(max)
0s        302.1mV    295.1mV    319.2mV
147ps     301.7mV    294.7mV    326.5mV
183ps     313.9mV    294.1mV    115.5mV
199ps     313.3mV    295.3mV    55.56mV
217ps     263.6mV    299.7mV    24.08mV
254ps     75.1mV     314mV      4.474mV
292ps     14.98mV    229.6mV    -3.68mV
354ps     1.161mV    38.74mV    -400.5uV
433ps     -1.295mV   1.953mV    -11.55uV
3ns       -322.9nV   1.912uV    372.1nV
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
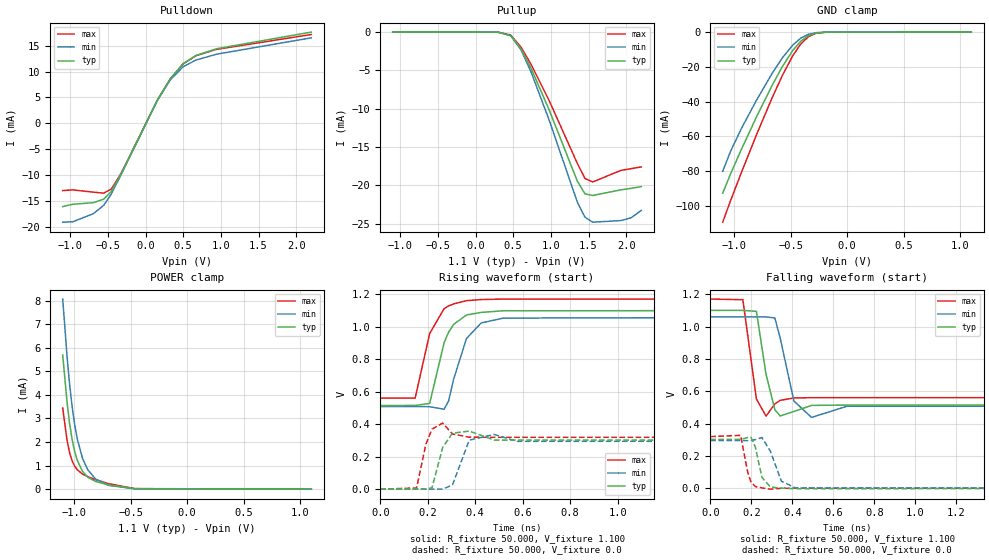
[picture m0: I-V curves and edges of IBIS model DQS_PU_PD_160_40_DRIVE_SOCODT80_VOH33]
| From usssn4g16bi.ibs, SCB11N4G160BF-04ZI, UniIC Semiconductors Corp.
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|   Model DQS_PU_PD_160_40_DRIVE_SOCODT80_VOH33
[Model] DQS_PU_PD_160_40_DRIVE_SOCODT80_VOH33
Model_type I/O
Polarity   Inverting
Vinl =  98.000mV
Vinh =  0.268V
Vmeas =  0.183V
Rref =  50.000
Vref =  0.183V
C_comp   1.020pF   1.010pF   1.030pF
[Model Spec]
Vinh   0.268V   0.262V   0.280V
Vinl   98.000mV   92.000mV   0.110V
Vmeas   0.183V   0.177V   0.195V
Vref   0.183V   0.177V   0.195V
Rref   50.000   NA   NA
[Temperature Range]   25.000   85.000   -40.000
[Voltage Range]   1.100V   1.060V   1.170V
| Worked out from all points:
|   slope of the pulldown table from 0 to 0.165 V, typ, clamps not added: 35.3 ohm
|   GND clamp passes 1 mA (typ) near -0.30 V on its own axis
|   POWER clamp passes 1 mA (typ) near -0.95 V on its own axis
|   rising waveform, R_fixture 50.000, V_fixture 1.100: 20-80 % time 69ps typ, 71.7ps min, 66.6ps max; typ from 0.514 V to 1.1 V
|   rising waveform, R_fixture 50.000, V_fixture 0.0: 20-80 % time 29.1ps typ, 35.7ps min, 23.7ps max; typ from 0 V to 0.302 V
|   falling waveform, R_fixture 50.000, V_fixture 1.100: 20-80 % time 39.3ps typ, 50.3ps min, 32.1ps max; typ from 1.1 V to 0.514 V
|   falling waveform, R_fixture 50.000, V_fixture 0.0: 20-80 % time 31.6ps typ, 49.4ps min, 26.8ps max; typ from 0.302 V to 0 V
[Pulldown]
|Voltage   I(typ)   I(min)   I(max)
-1.1V     -16.13mA   -19.15mA   -13.03mA
-964mV    -15.68mA   -19.06mA   -12.9mA
-692mV    -15.37mA   -17.49mA   -13.34mA
-556mV    -14.7mA    -15.89mA   -13.53mA
-454mV    -13.2mA    -13.69mA   -12.73mA
-318mV    -9.609mA   -9.745mA   -9.529mA
158mV     4.492mA    4.453mA    4.512mA
328mV     8.568mA    8.368mA    8.576mA
498mV     11.5mA     10.93mA    11.48mA
668mV     13.1mA     12.21mA    13.05mA
940mV     14.4mA     13.35mA    14.28mA
2.2V      17.63mA    16.52mA    17.16mA
[Pullup]
|Voltage   I(typ)   I(min)   I(max)
-1.1V     1.606nA    7.718nA    0A
296mV     -8.845uA   -10.59uA   -4.922uA
466mV     -464.7uA   -456.5uA   -387.5uA
602mV     -2.18mA    -2.299mA   -1.951mA
738mV     -4.764mA   -5.249mA   -4.236mA
976mV     -10.14mA   -11.47mA   -8.932mA
1.35V     -19.45mA   -22.19mA   -17.13mA
1.452V    -21.12mA   -24.17mA   -19.11mA
1.554V    -21.33mA   -24.82mA   -19.57mA
1.928V    -20.6mA    -24.61mA   -18.06mA
2.064V    -20.4mA    -24.25mA   -17.83mA
2.2V      -20.18mA   -23.28mA   -17.6mA
[GND_clamp]
|Voltage   I(typ)   I(min)   I(max)
-1.1V     -92.78mA   -80.14mA   -109.5mA
-1.031V   -81.73mA   -68.77mA   -97.17mA
-939mV    -68.18mA   -56.07mA   -81.64mA
-801mV    -48.85mA   -39.25mA   -59.15mA
-663mV    -30.71mA   -23.84mA   -37.89mA
-571mV    -19.76mA   -14.75mA   -24.85mA
-479mV    -10.5mA    -7.415mA   -13.5mA
-410mV    -5.313mA   -3.546mA   -6.916mA
-341mV    -2.007mA   -1.262mA   -2.59mA
-272mV    -506.9uA   -323.5uA   -609.8uA
-180mV    -45.65uA   -36.06uA   -43.55uA
1.1V      0A         0A         0A
[POWER_clamp]
|Voltage   I(typ)   I(min)   I(max)
-1.1V     5.691mA    8.066mA    3.44mA
-1.062V   3.709mA    5.665mA    2.092mA
-1.039V   2.781mA    4.457mA    1.546mA
-1.016V   2.086mA    3.48mA     1.193mA
-993mV    1.578mA    2.707mA    966.5uA
-970mV    1.21mA     2.107mA    818.5uA
-924mV    750.8uA    1.296mA    641.3uA
-878mV    507uA      821.4uA    530.2uA
-809mV    327.4uA    430uA      403.3uA
-694mV    178.4uA    161uA      233uA
-464mV    19.89uA    15.19uA    23.61uA
1.1V      0A         0A         0A
[Ramp]
| variable   typ   min   max
dV/dt_r   0.181/29.054p   0.177/35.876p   0.192/23.693p
dV/dt_f   0.351/39.489p   0.331/50.479p   0.366/32.143p
R_load = 50.000
[Rising Waveform]
R_fixture= 50.000
V_fixture= 1.100
V_fixture_min= 1.060
V_fixture_max= 1.170
|time   V(typ)   V(min)   V(max)
0s        514.4mV    508.1mV    560.3mV
147ps     515.3mV    508.7mV    560.8mV
208ps     527.8mV    507.5mV    957.7mV
269ps     902mV      491.9mV    1.111V
288ps     966.5mV    543.6mV    1.128V
309ps     1.014V     676.9mV    1.14V
363ps     1.072V     926.7mV    1.16V
425ps     1.088V     1.023V     1.167V
519ps     1.098V     1.053V     1.17V
3ns       1.1V       1.06V      1.17V
[Rising Waveform]
R_fixture= 50.000
V_fixture= 0.0
V_fixture_min= 0.0
V_fixture_max= 0.0
|time   V(typ)   V(min)   V(max)
0s        2.608uV    4.994uV    615.8nV
153ps     169.3uV    21.38uV    7.456mV
192ps     420.2uV    83.12uV    276.2mV
218ps     9.014mV    369.2uV    369.4mV
263ps     257.2mV    307.9uV    406.7mV
304ps     344.3mV    25.71mV    339.6mV
375ps     357.5mV    301.9mV    319.9mV
480ps     302.1mV    336.7mV    319.2mV
576ps     302.1mV    294.4mV    319.2mV
3ns       302.1mV    295.1mV    319.2mV
[Falling Waveform]
R_fixture= 50.000
V_fixture= 1.100
V_fixture_min= 1.060
V_fixture_max= 1.170
|time   V(typ)   V(min)   V(max)
0s        1.1V       1.06V      1.17V
159ps     1.1V       1.06V      1.166V
225ps     1.094V     1.06V      552.2mV
272ps     704.5mV    1.06V      446mV
315ps     485.5mV    1.053V     521.3mV
341ps     447mV      928.8mV    543.7mV
408ps     474.8mV    539.2mV    558.2mV
494ps     512.2mV    437.9mV    560.1mV
667ps     514.4mV    507.1mV    560.3mV
3ns       514.4mV    508.1mV    560.3mV
[Falling Waveform]
R_fixture= 50.000
V_fixture= 0.0
V_fixture_min= 0.0
V_fixture_max= 0.0
|time   V(typ)   V(min)   V(max)
0s        302.1mV    295.1mV    319.2mV
148ps     301.7mV    294.7mV    327mV
183ps     313.8mV    294.1mV    95.48mV
199ps     314.5mV    295.2mV    37.21mV
220ps     254.1mV    300.6mV    10.61mV
252ps     66.8mV     313.6mV    1.92mV
293ps     7.698mV    229.1mV    -5.828mV
347ps     749.6uV    43.58mV    -519.2uV
415ps     -3.322mV   2.066mV    -8.821uV
3ns       2.509uV    4.775uV    140.6nV
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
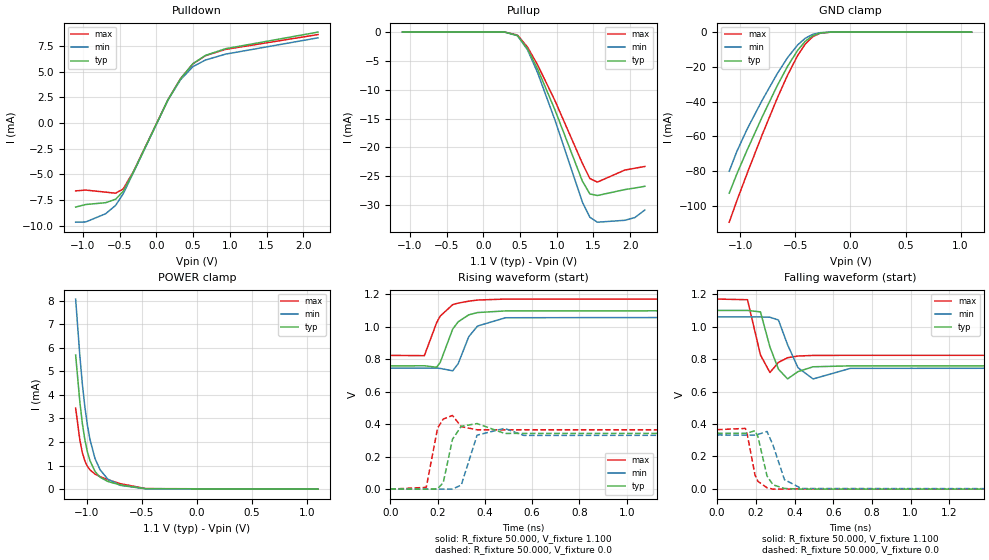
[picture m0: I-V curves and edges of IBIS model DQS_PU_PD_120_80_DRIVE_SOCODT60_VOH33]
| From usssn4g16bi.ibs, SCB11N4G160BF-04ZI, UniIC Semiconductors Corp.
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|   Model DQS_PU_PD_120_80_DRIVE_SOCODT60_VOH33
[Model] DQS_PU_PD_120_80_DRIVE_SOCODT60_VOH33
Model_type I/O
Polarity   Inverting
Vinl =  98.000mV
Vinh =  0.268V
Vmeas =  0.183V
Rref =  50.000
Vref =  0.183V
C_comp   1.020pF   1.010pF   1.030pF
[Model Spec]
Vinh   0.268V   0.262V   0.280V
Vinl   98.000mV   92.000mV   0.110V
Vmeas   0.183V   0.177V   0.195V
Vref   0.183V   0.177V   0.195V
Rref   50.000   NA   NA
[Temperature Range]   25.000   85.000   -40.000
[Voltage Range]   1.100V   1.060V   1.170V
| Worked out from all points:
|   slope of the pulldown table from 0 to 0.165 V, typ, clamps not added: 70.2 ohm
|   GND clamp passes 1 mA (typ) near -0.30 V on its own axis
|   POWER clamp passes 1 mA (typ) near -0.95 V on its own axis
|   rising waveform, R_fixture 50.000, V_fixture 1.100: 20-80 % time 66.3ps typ, 67ps min, 65ps max; typ from 0.759 V to 1.1 V
|   rising waveform, R_fixture 50.000, V_fixture 0.0: 20-80 % time 27.9ps typ, 34.6ps min, 22.6ps max; typ from 0 V to 0.343 V
|   falling waveform, R_fixture 50.000, V_fixture 1.100: 20-80 % time 43.8ps typ, 55.2ps min, 34.7ps max; typ from 1.1 V to 0.759 V
|   falling waveform, R_fixture 50.000, V_fixture 0.0: 20-80 % time 41.6ps typ, 53.9ps min, 37.6ps max; typ from 0.343 V to 0 V
[Pulldown]
|Voltage   I(typ)   I(min)   I(max)
-1.1V     -8.193mA   -9.666mA   -6.618mA
-964mV    -7.945mA   -9.646mA   -6.54mA
-692mV    -7.769mA   -8.844mA   -6.742mA
-556mV    -7.432mA   -8.032mA   -6.841mA
-454mV    -6.673mA   -6.916mA   -6.44mA
-318mV    -4.841mA   -4.906mA   -4.804mA
158mV     2.257mA    2.237mA    2.267mA
328mV     4.302mA    4.2mA      4.305mA
498mV     5.77mA     5.483mA    5.759mA
668mV     6.567mA    6.118mA    6.54mA
940mV     7.217mA    6.688mA    7.152mA
2.2V      8.836mA    8.278mA    8.595mA
[Pullup]
|Voltage   I(typ)   I(min)   I(max)
-1.1V     2.106nA    10.33nA    0A
296mV     -11.79uA   -14.12uA   -6.562uA
466mV     -619.2uA   -608.2uA   -516.4uA
602mV     -2.903mA   -3.06mA    -2.598mA
738mV     -6.341mA   -6.984mA   -5.639mA
976mV     -13.49mA   -15.26mA   -11.89mA
1.35V     -25.87mA   -29.51mA   -22.79mA
1.452V    -28.09mA   -32.14mA   -25.42mA
1.554V    -28.36mA   -32.99mA   -26.03mA
1.928V    -27.33mA   -32.66mA   -23.94mA
2.064V    -27.06mA   -32.19mA   -23.63mA
2.2V      -26.76mA   -30.87mA   -23.32mA
[GND_clamp]
|Voltage   I(typ)   I(min)   I(max)
-1.1V     -92.78mA   -80.14mA   -109.5mA
-1.031V   -81.73mA   -68.77mA   -97.17mA
-939mV    -68.18mA   -56.07mA   -81.64mA
-801mV    -48.85mA   -39.25mA   -59.15mA
-663mV    -30.71mA   -23.84mA   -37.89mA
-571mV    -19.76mA   -14.75mA   -24.85mA
-479mV    -10.5mA    -7.415mA   -13.5mA
-410mV    -5.313mA   -3.546mA   -6.916mA
-341mV    -2.007mA   -1.262mA   -2.59mA
-272mV    -506.9uA   -323.5uA   -609.8uA
-180mV    -45.65uA   -36.06uA   -43.55uA
1.1V      0A         0A         0A
[POWER_clamp]
|Voltage   I(typ)   I(min)   I(max)
-1.1V     5.691mA    8.066mA    3.44mA
-1.062V   3.709mA    5.665mA    2.092mA
-1.039V   2.781mA    4.457mA    1.546mA
-1.016V   2.086mA    3.48mA     1.193mA
-993mV    1.578mA    2.707mA    966.5uA
-970mV    1.21mA     2.107mA    818.5uA
-924mV    750.8uA    1.296mA    641.3uA
-878mV    507uA      821.4uA    530.2uA
-809mV    327.4uA    430uA      403.3uA
-694mV    178.4uA    161uA      233uA
-464mV    19.89uA    15.19uA    23.61uA
1.1V      0A         0A         0A
[Ramp]
| variable   typ   min   max
dV/dt_r   0.206/28.053p   0.200/34.482p   0.219/22.743p
dV/dt_f   0.205/43.873p   0.189/55.147p   0.208/34.722p
R_load = 50.000
[Rising Waveform]
R_fixture= 50.000
V_fixture= 1.100
V_fixture_min= 1.060
V_fixture_max= 1.170
|time   V(typ)   V(min)   V(max)
0s        758.6mV    744.6mV    823.3mV
144ps     759.4mV    744.9mV    821.6mV
196ps     750.4mV    745.4mV    1.025V
211ps     779.9mV    743.1mV    1.065V
264ps     985.6mV    728.4mV    1.136V
287ps     1.03V      772.4mV    1.145V
332ps     1.073V     938.8mV    1.157V
369ps     1.087V     1.004V     1.164V
487ps     1.097V     1.055V     1.17V
3ns       1.1V       1.06V      1.17V
[Rising Waveform]
R_fixture= 50.000
V_fixture= 0.0
V_fixture_min= 0.0
V_fixture_max= 0.0
|time   V(typ)   V(min)   V(max)
0s        3.731uV    7.145uV    881.9nV
152ps     -139.8uV   37.57uV    11.08mV
200ps     2.143mV    -69.35uV   376.1mV
224ps     40.14mV    -94.48uV   431.5mV
263ps     307.3mV    664uV      453.6mV
300ps     386.7mV    24.95mV    384.6mV
367ps     403.8mV    332.2mV    365.4mV
483ps     343mV      374.2mV    365.2mV
564ps     343.2mV    330.9mV    365.2mV
3ns       343.2mV    332.5mV    365.2mV
[Falling Waveform]
R_fixture= 50.000
V_fixture= 1.100
V_fixture_min= 1.060
V_fixture_max= 1.170
|time   V(typ)   V(min)   V(max)
0s        1.1V       1.06V      1.17V
157ps     1.1V       1.06V      1.166V
224ps     1.091V     1.06V      825.5mV
273ps     874.7mV    1.058V     717.3mV
317ps     738.1mV    1.041V     779.9mV
364ps     678.2mV    889mV      808.6mV
418ps     723.1mV    747.1mV    819mV
496ps     752.7mV    677.8mV    822.6mV
689ps     758.5mV    743.1mV    823.3mV
3ns       758.6mV    744.6mV    823.3mV
[Falling Waveform]
R_fixture= 50.000
V_fixture= 0.0
V_fixture_min= 0.0
V_fixture_max= 0.0
|time   V(typ)   V(min)   V(max)
0s        343.2mV    332.5mV    365.2mV
146ps     342.7mV    332mV      372.9mV
156ps     344.8mV    331.7mV    335.7mV
196ps     358.7mV    332.3mV    85.2mV
211ps     321.7mV    335.8mV    46.96mV
258ps     79.78mV    354.2mV    7.168mV
289ps     25.41mV    269.3mV    -1.349mV
348ps     2.953mV    57.12mV    -353.9uV
436ps     -924.6uV   2.884mV    -11.48uV
3ns       3.511uV    7.032uV    607nV
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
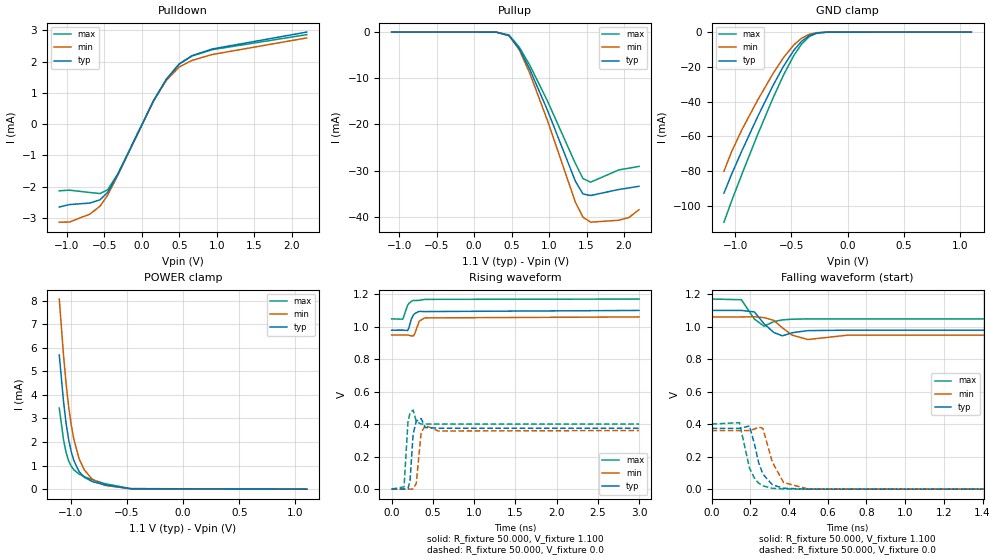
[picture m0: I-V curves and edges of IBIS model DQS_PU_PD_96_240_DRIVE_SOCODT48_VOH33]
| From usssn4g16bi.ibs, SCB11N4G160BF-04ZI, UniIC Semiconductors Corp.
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|   Model DQS_PU_PD_96_240_DRIVE_SOCODT48_VOH33
[Model] DQS_PU_PD_96_240_DRIVE_SOCODT48_VOH33
Model_type I/O
Polarity   Inverting
Vinl =  98.000mV
Vinh =  0.268V
Vmeas =  0.183V
Rref =  50.000
Vref =  0.183V
C_comp   1.020pF   1.010pF   1.030pF
[Model Spec]
Vinh   0.268V   0.262V   0.280V
Vinl   98.000mV   92.000mV   0.110V
Vmeas   0.183V   0.177V   0.195V
Vref   0.183V   0.177V   0.195V
Rref   50.000   NA   NA
[Temperature Range]   25.000   85.000   -40.000
[Voltage Range]   1.100V   1.060V   1.170V
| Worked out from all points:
|   slope of the pulldown table from 0 to 0.165 V, typ, clamps not added: 211 ohm
|   GND clamp passes 1 mA (typ) near -0.30 V on its own axis
|   POWER clamp passes 1 mA (typ) near -0.95 V on its own axis
|   rising waveform, R_fixture 50.000, V_fixture 1.100: 20-80 % time 55ps typ, 50.1ps min, 57.4ps max; typ from 0.978 V to 1.1 V
|   rising waveform, R_fixture 50.000, V_fixture 0.0: 20-80 % time 27.2ps typ, 34.2ps min, 21.7ps max; typ from 0 V to 0.374 V
|   falling waveform, R_fixture 50.000, V_fixture 1.100: 20-80 % time 46.8ps typ, 64.4ps min, 35.5ps max; typ from 1.1 V to 0.978 V
|   falling waveform, R_fixture 50.000, V_fixture 0.0: 20-80 % time 55ps typ, 61ps min, 52.4ps max; typ from 0.374 V to 0 V
[Pulldown]
|Voltage   I(typ)   I(min)   I(max)
-1.1V     -2.652mA   -3.14mA    -2.134mA
-964mV    -2.576mA   -3.135mA   -2.114mA
-692mV    -2.527mA   -2.882mA   -2.189mA
-556mV    -2.422mA   -2.626mA   -2.223mA
-454mV    -2.185mA   -2.274mA   -2.101mA
-318mV    -1.604mA   -1.629mA   -1.589mA
158mV     752.2uA    745.4uA    755.4uA
328mV     1.434mA    1.4mA      1.435mA
498mV     1.924mA    1.828mA    1.92mA
668mV     2.19mA     2.04mA     2.18mA
940mV     2.407mA    2.23mA     2.385mA
2.2V      2.948mA    2.761mA    2.866mA
[Pullup]
|Voltage   I(typ)   I(min)   I(max)
-1.1V     2.6nA      12.94nA    0A
296mV     -14.74uA   -17.65uA   -8.203uA
466mV     -773.5uA   -759.8uA   -645.2uA
602mV     -3.625mA   -3.82mA    -3.244mA
738mV     -7.914mA   -8.716mA   -7.039mA
976mV     -16.84mA   -19.04mA   -14.84mA
1.35V     -32.28mA   -36.82mA   -28.44mA
1.452V    -35.08mA   -40.12mA   -31.74mA
1.554V    -35.42mA   -41.2mA    -32.53mA
1.928V    -34.12mA   -40.78mA   -29.88mA
2.064V    -33.78mA   -40.2mA    -29.49mA
2.2V      -33.41mA   -38.49mA   -29.11mA
[GND_clamp]
|Voltage   I(typ)   I(min)   I(max)
-1.1V     -92.78mA   -80.14mA   -109.5mA
-1.031V   -81.73mA   -68.77mA   -97.17mA
-939mV    -68.18mA   -56.07mA   -81.64mA
-801mV    -48.85mA   -39.25mA   -59.15mA
-663mV    -30.71mA   -23.84mA   -37.89mA
-571mV    -19.76mA   -14.75mA   -24.85mA
-479mV    -10.5mA    -7.415mA   -13.5mA
-410mV    -5.313mA   -3.546mA   -6.916mA
-341mV    -2.007mA   -1.262mA   -2.59mA
-272mV    -506.9uA   -323.5uA   -609.8uA
-180mV    -45.65uA   -36.06uA   -43.55uA
1.1V      0A         0A         0A
[POWER_clamp]
|Voltage   I(typ)   I(min)   I(max)
-1.1V     5.691mA    8.066mA    3.44mA
-1.062V   3.709mA    5.665mA    2.092mA
-1.039V   2.781mA    4.457mA    1.546mA
-1.016V   2.086mA    3.48mA     1.193mA
-993mV    1.578mA    2.707mA    966.5uA
-970mV    1.21mA     2.107mA    818.5uA
-924mV    750.8uA    1.296mA    641.3uA
-878mV    507uA      821.4uA    530.2uA
-809mV    327.4uA    430uA      403.3uA
-694mV    178.4uA    161uA      233uA
-464mV    19.89uA    15.19uA    23.61uA
1.1V      0A         0A         0A
[Ramp]
| variable   typ   min   max
dV/dt_r   0.225/27.191p   0.216/34.324p   0.240/21.935p
dV/dt_f   72.904m/46.897p   67.052m/64.435p   73.268m/35.527p
R_load = 50.000
[Rising Waveform]
R_fixture= 50.000
V_fixture= 1.100
V_fixture_min= 1.060
V_fixture_max= 1.170
|time   V(typ)   V(min)   V(max)
0s        978.5mV    948.3mV    1.048V
136ps     978.9mV    948.4mV    1.046V
194ps     976.3mV    948.5mV    1.132V
210ps     993mV      947.4mV    1.143V
239ps     1.047V     943.2mV    1.156V
263ps     1.071V     942.8mV    1.162V
281ps     1.081V     957mV      1.161V
334ps     1.094V     1.033V     1.162V
399ps     1.093V     1.054V     1.168V
3ns       1.1V       1.06V      1.17V
[Rising Waveform]
R_fixture= 50.000
V_fixture= 0.0
V_fixture_min= 0.0
V_fixture_max= 0.0
|time   V(typ)   V(min)   V(max)
0s        5.234uV    10.02uV    1.239uV
151ps     -348.8uV   75.42uV    13.53mV
198ps     3.248mV    -238.4uV   412.4mV
223ps     49.15mV    -604.4uV   468.1mV
261ps     338.4mV    968.1uV    487.1mV
299ps     418.5mV    35.29mV    415.9mV
358ps     434.4mV    347.3mV    400.2mV
408ps     379.3mV    391.6mV    400.4mV
566ps     374.4mV    357.6mV    400.4mV
3ns       374.4mV    360.6mV    400.4mV
[Falling Waveform]
R_fixture= 50.000
V_fixture= 1.100
V_fixture_min= 1.060
V_fixture_max= 1.170
|time   V(typ)   V(min)   V(max)
0s        1.1V       1.06V      1.17V
154ps     1.1V       1.06V      1.166V
221ps     1.091V     1.061V     1.047V
271ps     1.018V     1.056V     1.003V
321ps     964.8mV    1.039V     1.031V
366ps     943.9mV    992.6mV    1.042V
418ps     963.2mV    947.2mV    1.046V
498ps     975.8mV    921mV      1.048V
703ps     978.5mV    947.8mV    1.048V
3ns       978.5mV    948.3mV    1.048V
[Falling Waveform]
R_fixture= 50.000
V_fixture= 0.0
V_fixture_min= 0.0
V_fixture_max= 0.0
|time   V(typ)   V(min)   V(max)
0s        374.4mV    360.6mV    400.4mV
144ps     373.8mV    360mV      409.5mV
196ps     389.2mV    360.6mV    129.3mV
224ps     266.2mV    370.9mV    61.71mV
243ps     163.9mV    382.5mV    37.43mV
265ps     92.98mV    374.3mV    20.67mV
314ps     26.78mV    166.2mV    5.107mV
372ps     5.759mV    40.99mV    1.204mV
496ps     181.7uV    1.795mV    53.84uV
3ns       5.242uV    9.99uV     1.235uV
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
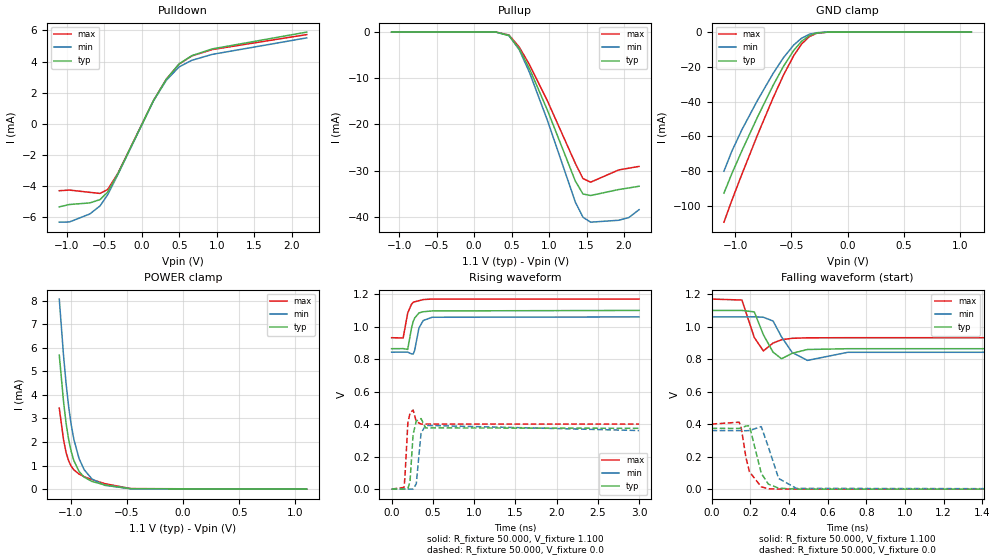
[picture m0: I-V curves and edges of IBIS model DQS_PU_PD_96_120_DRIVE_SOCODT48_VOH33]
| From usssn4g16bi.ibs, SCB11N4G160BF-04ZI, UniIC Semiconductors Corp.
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|   Model DQS_PU_PD_96_120_DRIVE_SOCODT48_VOH33
[Model] DQS_PU_PD_96_120_DRIVE_SOCODT48_VOH33
Model_type I/O
Polarity   Inverting
Vinl =  98.000mV
Vinh =  0.268V
Vmeas =  0.183V
Rref =  50.000
Vref =  0.183V
C_comp   1.020pF   1.010pF   1.030pF
[Model Spec]
Vinh   0.268V   0.262V   0.280V
Vinl   98.000mV   92.000mV   0.110V
Vmeas   0.183V   0.177V   0.195V
Vref   0.183V   0.177V   0.195V
Rref   50.000   NA   NA
[Temperature Range]   25.000   85.000   -40.000
[Voltage Range]   1.100V   1.060V   1.170V
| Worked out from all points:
|   slope of the pulldown table from 0 to 0.165 V, typ, clamps not added: 105 ohm
|   GND clamp passes 1 mA (typ) near -0.30 V on its own axis
|   POWER clamp passes 1 mA (typ) near -0.95 V on its own axis
|   rising waveform, R_fixture 50.000, V_fixture 1.100: 20-80 % time 62.1ps typ, 60.4ps min, 62.4ps max; typ from 0.864 V to 1.1 V
|   rising waveform, R_fixture 50.000, V_fixture 0.0: 20-80 % time 26.9ps typ, 33.9ps min, 21.7ps max; typ from 0 V to 0.374 V
|   falling waveform, R_fixture 50.000, V_fixture 1.100: 20-80 % time 44.6ps typ, 57.3ps min, 34.7ps max; typ from 1.1 V to 0.864 V
|   falling waveform, R_fixture 50.000, V_fixture 0.0: 20-80 % time 46.6ps typ, 56ps min, 43.2ps max; typ from 0.374 V to 0 V
[Pulldown]
|Voltage   I(typ)   I(min)   I(max)
-1.1V     -5.34mA    -6.324mA   -4.302mA
-964mV    -5.187mA   -6.308mA   -4.26mA
-692mV    -5.084mA   -5.795mA   -4.408mA
-556mV    -4.87mA    -5.274mA   -4.475mA
-454mV    -4.386mA   -4.558mA   -4.222mA
-318mV    -3.209mA   -3.256mA   -3.18mA
158mV     1.503mA    1.489mA    1.509mA
328mV     2.865mA    2.797mA    2.867mA
498mV     3.844mA    3.653mA    3.837mA
668mV     4.377mA    4.078mA    4.359mA
940mV     4.811mA    4.458mA    4.768mA
2.2V      5.891mA    5.519mA    5.73mA
[Pullup]
|Voltage   I(typ)   I(min)   I(max)
-1.1V     2.6nA      12.94nA    0A
296mV     -14.74uA   -17.65uA   -8.203uA
466mV     -773.5uA   -759.8uA   -645.2uA
602mV     -3.625mA   -3.82mA    -3.244mA
738mV     -7.914mA   -8.716mA   -7.039mA
976mV     -16.84mA   -19.04mA   -14.84mA
1.35V     -32.28mA   -36.82mA   -28.44mA
1.452V    -35.08mA   -40.12mA   -31.74mA
1.554V    -35.42mA   -41.2mA    -32.53mA
1.928V    -34.12mA   -40.78mA   -29.88mA
2.064V    -33.78mA   -40.2mA    -29.49mA
2.2V      -33.41mA   -38.49mA   -29.11mA
[GND_clamp]
|Voltage   I(typ)   I(min)   I(max)
-1.1V     -92.78mA   -80.14mA   -109.5mA
-1.031V   -81.73mA   -68.77mA   -97.17mA
-939mV    -68.18mA   -56.07mA   -81.64mA
-801mV    -48.85mA   -39.25mA   -59.15mA
-663mV    -30.71mA   -23.84mA   -37.89mA
-571mV    -19.76mA   -14.75mA   -24.85mA
-479mV    -10.5mA    -7.415mA   -13.5mA
-410mV    -5.313mA   -3.546mA   -6.916mA
-341mV    -2.007mA   -1.262mA   -2.59mA
-272mV    -506.9uA   -323.5uA   -609.8uA
-180mV    -45.65uA   -36.06uA   -43.55uA
1.1V      0A         0A         0A
[POWER_clamp]
|Voltage   I(typ)   I(min)   I(max)
-1.1V     5.691mA    8.066mA    3.44mA
-1.062V   3.709mA    5.665mA    2.092mA
-1.039V   2.781mA    4.457mA    1.546mA
-1.016V   2.086mA    3.48mA     1.193mA
-993mV    1.578mA    2.707mA    966.5uA
-970mV    1.21mA     2.107mA    818.5uA
-924mV    750.8uA    1.296mA    641.3uA
-878mV    507uA      821.4uA    530.2uA
-809mV    327.4uA    430uA      403.3uA
-694mV    178.4uA    161uA      233uA
-464mV    19.89uA    15.19uA    23.61uA
1.1V      0A         0A         0A
[Ramp]
| variable   typ   min   max
dV/dt_r   0.225/27.123p   0.216/34.038p   0.240/21.872p
dV/dt_f   0.141/44.756p   0.130/57.288p   0.143/34.768p
R_load = 50.000
[Rising Waveform]
R_fixture= 50.000
V_fixture= 1.100
V_fixture_min= 1.060
V_fixture_max= 1.170
|time   V(typ)   V(min)   V(max)
0s        864.4mV    842.9mV    932.1mV
140ps     865mV      843.2mV    930.5mV
195ps     860.1mV    843.3mV    1.084V
241ps     990.7mV    832.6mV    1.138V
262ps     1.032V     831.7mV    1.15V
279ps     1.053V     853.8mV    1.153V
332ps     1.085V     992.3mV    1.16V
384ps     1.092V     1.038V     1.167V
491ps     1.097V     1.058V     1.17V
3ns       1.1V       1.06V      1.17V
[Rising Waveform]
R_fixture= 50.000
V_fixture= 0.0
V_fixture_min= 0.0
V_fixture_max= 0.0
|time   V(typ)   V(min)   V(max)
0s        4.355uV    8.339uV    1.03uV
150ps     -233.4uV   62.84uV    10.42mV
161ps     -367.7uV   62.21uV    67.46mV
197ps     2.232mV    -136.7uV   407.4mV
223ps     46.54mV    -385.1uV   468.1mV
261ps     338.6mV    602.5uV    487.1mV
299ps     418.4mV    32.53mV    416mV
357ps     434.3mV    344.4mV    400.2mV
412ps     376.8mV    392.2mV    400.4mV
3ns       374.4mV    360.6mV    400.4mV
[Falling Waveform]
R_fixture= 50.000
V_fixture= 1.100
V_fixture_min= 1.060
V_fixture_max= 1.170
|time   V(typ)   V(min)   V(max)
0s        1.1V       1.06V      1.17V
157ps     1.1V       1.06V      1.164V
221ps     1.091V     1.061V     933.4mV
268ps     950.5mV    1.058V     850.9mV
318ps     843.4mV    1.035V     899mV
362ps     802.6mV    937.1mV    919.7mV
417ps     836mV      841mV      928.4mV
496ps     859.5mV    792.4mV    931.4mV
704ps     864.3mV    842.1mV    932.1mV
3ns       864.4mV    842.9mV    932.1mV
[Falling Waveform]
R_fixture= 50.000
V_fixture= 0.0
V_fixture_min= 0.0
V_fixture_max= 0.0
|time   V(typ)   V(min)   V(max)
0s        374.4mV    360.6mV    400.4mV
143ps     373.6mV    360mV      411.8mV
154ps     376mV      359.7mV    373.2mV
178ps     388.4mV    359.3mV    193.1mV
196ps     390.1mV    360.6mV    106.4mV
257ps     97.38mV    384.9mV    14.11mV
294ps     30.48mV    258.3mV    1.834mV
347ps     5.862mV    65.44mV    276.5uV
439ps     -415.4uV   4.379mV    18.53uV
3ns       4.151uV    8.17uV     903.7nV
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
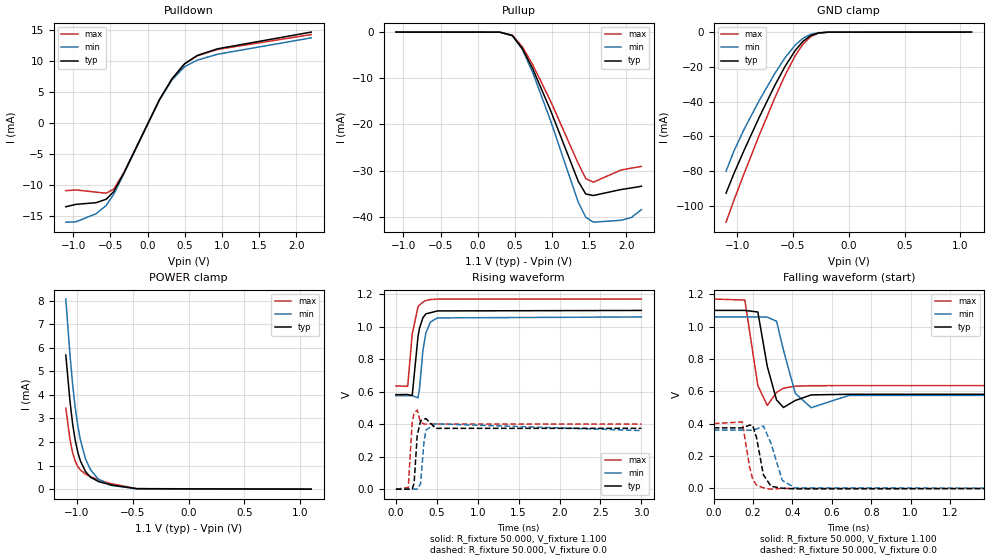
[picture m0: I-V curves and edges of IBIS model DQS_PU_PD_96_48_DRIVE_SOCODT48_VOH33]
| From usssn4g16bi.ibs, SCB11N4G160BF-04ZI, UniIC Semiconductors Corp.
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|   Model DQS_PU_PD_96_48_DRIVE_SOCODT48_VOH33
[Model] DQS_PU_PD_96_48_DRIVE_SOCODT48_VOH33
Model_type I/O
Polarity   Inverting
Vinl =  98.000mV
Vinh =  0.268V
Vmeas =  0.183V
Rref =  50.000
Vref =  0.183V
C_comp   1.020pF   1.010pF   1.030pF
[Model Spec]
Vinh   0.268V   0.262V   0.280V
Vinl   98.000mV   92.000mV   0.110V
Vmeas   0.183V   0.177V   0.195V
Vref   0.183V   0.177V   0.195V
Rref   50.000   NA   NA
[Temperature Range]   25.000   85.000   -40.000
[Voltage Range]   1.100V   1.060V   1.170V
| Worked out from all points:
|   slope of the pulldown table from 0 to 0.165 V, typ, clamps not added: 42.3 ohm
|   GND clamp passes 1 mA (typ) near -0.30 V on its own axis
|   POWER clamp passes 1 mA (typ) near -0.95 V on its own axis
|   rising waveform, R_fixture 50.000, V_fixture 1.100: 20-80 % time 67.8ps typ, 69.3ps min, 66ps max; typ from 0.582 V to 1.1 V
|   rising waveform, R_fixture 50.000, V_fixture 0.0: 20-80 % time 26.6ps typ, 33.1ps min, 21.6ps max; typ from 0 V to 0.374 V
|   falling waveform, R_fixture 50.000, V_fixture 1.100: 20-80 % time 41.5ps typ, 52.8ps min, 33.4ps max; typ from 1.1 V to 0.582 V
|   falling waveform, R_fixture 50.000, V_fixture 0.0: 20-80 % time 34.9ps typ, 50.5ps min, 30ps max; typ from 0.374 V to 0 V
[Pulldown]
|Voltage   I(typ)   I(min)   I(max)
-1.1V     -13.51mA   -16mA      -10.91mA
-964mV    -13.12mA   -15.94mA   -10.79mA
-692mV    -12.85mA   -14.63mA   -11.15mA
-556mV    -12.29mA   -13.29mA   -11.31mA
-454mV    -11.04mA   -11.45mA   -10.65mA
-318mV    -8.03mA    -8.142mA   -7.964mA
158mV     3.751mA    3.718mA    3.768mA
328mV     7.153mA    6.985mA    7.158mA
498mV     9.598mA    9.123mA    9.581mA
668mV     10.93mA    10.18mA    10.89mA
940mV     12.01mA    11.13mA    11.91mA
2.2V      14.71mA    13.78mA    14.31mA
[Pullup]
|Voltage   I(typ)   I(min)   I(max)
-1.1V     2.6nA      12.94nA    0A
296mV     -14.74uA   -17.65uA   -8.203uA
466mV     -773.5uA   -759.8uA   -645.2uA
602mV     -3.625mA   -3.82mA    -3.244mA
738mV     -7.914mA   -8.716mA   -7.039mA
976mV     -16.84mA   -19.04mA   -14.84mA
1.35V     -32.28mA   -36.82mA   -28.44mA
1.452V    -35.08mA   -40.12mA   -31.74mA
1.554V    -35.42mA   -41.2mA    -32.53mA
1.928V    -34.12mA   -40.78mA   -29.88mA
2.064V    -33.78mA   -40.2mA    -29.49mA
2.2V      -33.41mA   -38.49mA   -29.11mA
[GND_clamp]
|Voltage   I(typ)   I(min)   I(max)
-1.1V     -92.78mA   -80.14mA   -109.5mA
-1.031V   -81.73mA   -68.77mA   -97.17mA
-939mV    -68.18mA   -56.07mA   -81.64mA
-801mV    -48.85mA   -39.25mA   -59.15mA
-663mV    -30.71mA   -23.84mA   -37.89mA
-571mV    -19.76mA   -14.75mA   -24.85mA
-479mV    -10.5mA    -7.415mA   -13.5mA
-410mV    -5.313mA   -3.546mA   -6.916mA
-341mV    -2.007mA   -1.262mA   -2.59mA
-272mV    -506.9uA   -323.5uA   -609.8uA
-180mV    -45.65uA   -36.06uA   -43.55uA
1.1V      0A         0A         0A
[POWER_clamp]
|Voltage   I(typ)   I(min)   I(max)
-1.1V     5.691mA    8.066mA    3.44mA
-1.062V   3.709mA    5.665mA    2.092mA
-1.039V   2.781mA    4.457mA    1.546mA
-1.016V   2.086mA    3.48mA     1.193mA
-993mV    1.578mA    2.707mA    966.5uA
-970mV    1.21mA     2.107mA    818.5uA
-924mV    750.8uA    1.296mA    641.3uA
-878mV    507uA      821.4uA    530.2uA
-809mV    327.4uA    430uA      403.3uA
-694mV    178.4uA    161uA      233uA
-464mV    19.89uA    15.19uA    23.61uA
1.1V      0A         0A         0A
[Ramp]
| variable   typ   min   max
dV/dt_r   0.225/26.721p   0.216/33.272p   0.240/21.724p
dV/dt_f   0.311/41.532p   0.291/52.919p   0.321/33.429p
R_load = 50.000
[Rising Waveform]
R_fixture= 50.000
V_fixture= 1.100
V_fixture_min= 1.060
V_fixture_max= 1.170
|time   V(typ)   V(min)   V(max)
0s        581.6mV    575.3mV    635mV
144ps     582.6mV    575.8mV    633.1mV
199ps     576.2mV    576.1mV    955.2mV
270ps     939.9mV    561.4mV    1.122V
289ps     992.4mV    622.3mV    1.133V
330ps     1.055V     853.6mV    1.151V
366ps     1.079V     961mV      1.161V
422ps     1.086V     1.029V     1.167V
508ps     1.097V     1.054V     1.17V
3ns       1.1V       1.06V      1.17V
[Rising Waveform]
R_fixture= 50.000
V_fixture= 0.0
V_fixture_min= 0.0
V_fixture_max= 0.0
|time   V(typ)   V(min)   V(max)
0s        2.898uV    5.55uV     684.5nV
151ps     -62.81uV   37.18uV    9.854mV
199ps     1.837mV    -6.647uV   414.4mV
222ps     34.83mV    78.46uV    467.1mV
260ps     329.8mV    559.8uV    486.8mV
301ps     419.6mV    32.55mV    413.3mV
343ps     430.6mV    291.7mV    400.3mV
367ps     434.4mV    364.2mV    400.2mV
486ps     374.2mV    402mV      400.4mV
3ns       374.4mV    360.6mV    400.4mV
[Falling Waveform]
R_fixture= 50.000
V_fixture= 1.100
V_fixture_min= 1.060
V_fixture_max= 1.170
|time   V(typ)   V(min)   V(max)
0s        1.1V       1.06V      1.17V
158ps     1.1V       1.06V      1.164V
224ps     1.09V      1.06V      634.4mV
272ps     753.2mV    1.058V     512.7mV
319ps     546.6mV    1.033V     593.4mV
354ps     499.9mV    854.8mV    619.2mV
414ps     543.2mV    587.8mV    631.7mV
495ps     577.7mV    498.7mV    634.6mV
686ps     581.5mV    574.2mV    635mV
3ns       581.6mV    575.3mV    635mV
[Falling Waveform]
R_fixture= 50.000
V_fixture= 0.0
V_fixture_min= 0.0
V_fixture_max= 0.0
|time   V(typ)   V(min)   V(max)
0s        374.4mV    360.6mV    400.4mV
145ps     373.7mV    360mV      410.6mV
182ps     390.8mV    359.3mV    131.1mV
197ps     390.5mV    360.7mV    59.76mV
217ps     315.7mV    367.2mV    20.37mV
252ps     84.54mV    386mV      3.401mV
291ps     12.88mV    277.6mV    -4.823mV
348ps     1.07mV     49.28mV    -520.4uV
413ps     -3.055mV   3.165mV    -18.48uV
3ns       947.6nV    5.343uV    352.7nV
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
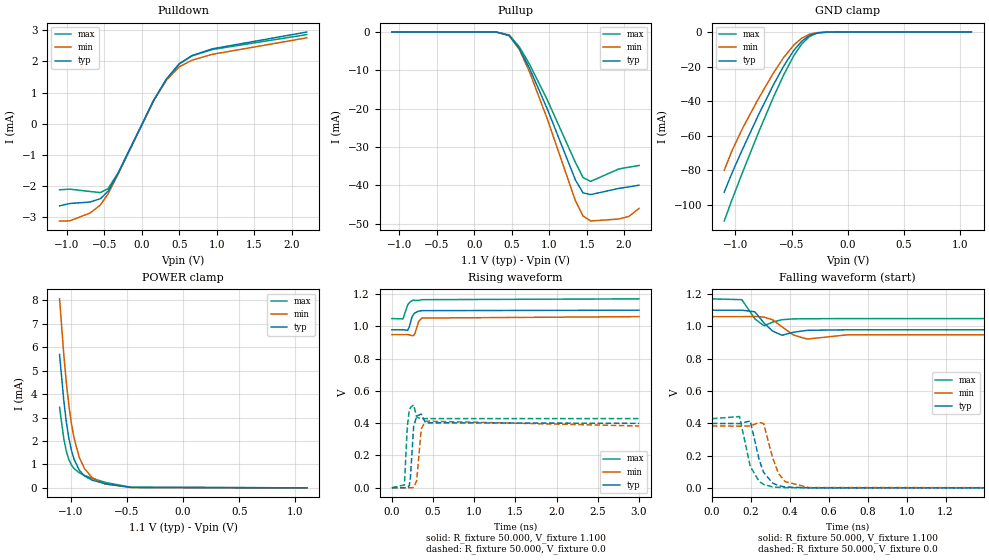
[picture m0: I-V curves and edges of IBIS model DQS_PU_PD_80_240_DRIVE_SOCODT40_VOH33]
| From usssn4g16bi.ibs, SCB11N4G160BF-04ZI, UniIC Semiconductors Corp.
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|   Model DQS_PU_PD_80_240_DRIVE_SOCODT40_VOH33
[Model] DQS_PU_PD_80_240_DRIVE_SOCODT40_VOH33
Model_type I/O
Polarity   Inverting
Vinl =  98.000mV
Vinh =  0.268V
Vmeas =  0.183V
Rref =  50.000
Vref =  0.183V
C_comp   1.020pF   1.010pF   1.030pF
[Model Spec]
Vinh   0.268V   0.262V   0.280V
Vinl   98.000mV   92.000mV   0.110V
Vmeas   0.183V   0.177V   0.195V
Vref   0.183V   0.177V   0.195V
Rref   50.000   NA   NA
[Temperature Range]   25.000   85.000   -40.000
[Voltage Range]   1.100V   1.060V   1.170V
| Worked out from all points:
|   slope of the pulldown table from 0 to 0.165 V, typ, clamps not added: 211 ohm
|   GND clamp passes 1 mA (typ) near -0.30 V on its own axis
|   POWER clamp passes 1 mA (typ) near -0.95 V on its own axis
|   rising waveform, R_fixture 50.000, V_fixture 1.100: 20-80 % time 50.6ps typ, 44.4ps min, 54.1ps max; typ from 0.978 V to 1.1 V
|   rising waveform, R_fixture 50.000, V_fixture 0.0: 20-80 % time 26.2ps typ, 33.5ps min, 21ps max; typ from 0 V to 0.399 V
|   falling waveform, R_fixture 50.000, V_fixture 1.100: 20-80 % time 47.3ps typ, 68.3ps min, 35.6ps max; typ from 1.1 V to 0.978 V
|   falling waveform, R_fixture 50.000, V_fixture 0.0: 20-80 % time 54.6ps typ, 60.1ps min, 52.2ps max; typ from 0.399 V to 0 V
[Pulldown]
|Voltage   I(typ)   I(min)   I(max)
-1.1V     -2.652mA   -3.14mA    -2.134mA
-964mV    -2.576mA   -3.135mA   -2.114mA
-692mV    -2.527mA   -2.882mA   -2.189mA
-556mV    -2.422mA   -2.626mA   -2.223mA
-454mV    -2.185mA   -2.274mA   -2.101mA
-318mV    -1.604mA   -1.629mA   -1.589mA
158mV     752.2uA    745.4uA    755.4uA
328mV     1.434mA    1.4mA      1.435mA
498mV     1.924mA    1.828mA    1.92mA
668mV     2.19mA     2.04mA     2.18mA
940mV     2.407mA    2.23mA     2.385mA
2.2V      2.948mA    2.761mA    2.866mA
[Pullup]
|Voltage   I(typ)   I(min)   I(max)
-1.1V     3.1nA      15.54nA    0A
296mV     -17.69uA   -21.17uA   -9.843uA
466mV     -927.4uA   -911uA     -773.6uA
602mV     -4.341mA   -4.574mA   -3.886mA
738mV     -9.474mA   -10.43mA   -8.429mA
976mV     -20.15mA   -22.77mA   -17.76mA
1.35V     -38.63mA   -44.04mA   -34.05mA
1.452V    -42.01mA   -48.04mA   -38mA
1.554V    -42.45mA   -49.35mA   -39mA
1.928V    -40.84mA   -48.83mA   -35.77mA
2.064V    -40.44mA   -48.15mA   -35.29mA
2.2V      -40mA      -46.05mA   -34.84mA
[GND_clamp]
|Voltage   I(typ)   I(min)   I(max)
-1.1V     -92.78mA   -80.14mA   -109.5mA
-1.031V   -81.73mA   -68.77mA   -97.17mA
-939mV    -68.18mA   -56.07mA   -81.64mA
-801mV    -48.85mA   -39.25mA   -59.15mA
-663mV    -30.71mA   -23.84mA   -37.89mA
-571mV    -19.76mA   -14.75mA   -24.85mA
-479mV    -10.5mA    -7.415mA   -13.5mA
-410mV    -5.313mA   -3.546mA   -6.916mA
-341mV    -2.007mA   -1.262mA   -2.59mA
-272mV    -506.9uA   -323.5uA   -609.8uA
-180mV    -45.65uA   -36.06uA   -43.55uA
1.1V      0A         0A         0A
[POWER_clamp]
|Voltage   I(typ)   I(min)   I(max)
-1.1V     5.691mA    8.066mA    3.44mA
-1.062V   3.709mA    5.665mA    2.092mA
-1.039V   2.781mA    4.457mA    1.546mA
-1.016V   2.086mA    3.48mA     1.193mA
-993mV    1.578mA    2.707mA    966.5uA
-970mV    1.21mA     2.107mA    818.5uA
-924mV    750.8uA    1.296mA    641.3uA
-878mV    507uA      821.4uA    530.2uA
-809mV    327.4uA    430uA      403.3uA
-694mV    178.4uA    161uA      233uA
-464mV    19.89uA    15.19uA    23.61uA
1.1V      0A         0A         0A
[Ramp]
| variable   typ   min   max
dV/dt_r   0.239/26.483p   0.230/33.650p   0.257/21.218p
dV/dt_f   72.904m/47.403p   67.052m/68.382p   73.268m/35.722p
R_load = 50.000
[Rising Waveform]
R_fixture= 50.000
V_fixture= 1.100
V_fixture_min= 1.060
V_fixture_max= 1.170
|time   V(typ)   V(min)   V(max)
0s        978.5mV    948.3mV    1.048V
135ps     978.9mV    948.4mV    1.046V
190ps     974.7mV    948.6mV    1.131V
210ps     994.2mV    947.3mV    1.146V
242ps     1.055V     942.5mV    1.158V
262ps     1.074V     942.2mV    1.163V
280ps     1.083V     956.4mV    1.161V
325ps     1.094V     1.03V      1.16V
363ps     1.097V     1.051V     1.165V
3ns       1.1V       1.06V      1.17V
[Rising Waveform]
R_fixture= 50.000
V_fixture= 0.0
V_fixture_min= 0.0
V_fixture_max= 0.0
|time   V(typ)   V(min)   V(max)
0s        5.234uV    10.02uV    1.239uV
152ps     -431.2uV   85.07uV    17.23mV
187ps     -74.5uV    -13.46uV   378.7mV
212ps     13.5mV     -554.8uV   483.8mV
226ps     71.86mV    -770.8uV   497.6mV
264ps     378.9mV    1.593mV    513mV
301ps     443.6mV    43.98mV    437.5mV
356ps     456.8mV    364mV      427.7mV
407ps     402.2mV    412.5mV    428.2mV
3ns       398.9mV    382.6mV    428.3mV
[Falling Waveform]
R_fixture= 50.000
V_fixture= 1.100
V_fixture_min= 1.060
V_fixture_max= 1.170
|time   V(typ)   V(min)   V(max)
0s        1.1V       1.06V      1.17V
154ps     1.1V       1.06V      1.165V
221ps     1.09V      1.061V     1.046V
268ps     1.02V      1.057V     1.003V
311ps     971.4mV    1.041V     1.026V
360ps     944.7mV    997.3mV    1.041V
419ps     963.5mV    946mV      1.046V
490ps     975.3mV    921.2mV    1.047V
698ps     978.5mV    947.7mV    1.048V
3ns       978.5mV    948.3mV    1.048V
[Falling Waveform]
R_fixture= 50.000
V_fixture= 0.0
V_fixture_min= 0.0
V_fixture_max= 0.0
|time   V(typ)   V(min)   V(max)
0s        398.9mV    382.6mV    428.3mV
142ps     398mV      382mV      441.4mV
197ps     414.5mV    382.6mV    133mV
243ps     173.2mV    405.9mV    39.5mV
266ps     95.44mV    397.1mV    21.2mV
311ps     30.48mV    190.1mV    5.866mV
342ps     13.89mV    88.83mV    2.719mV
376ps     5.347mV    38.84mV    1.154mV
497ps     191.9uV    1.822mV    55.68uV
3ns       5.23uV     9.896uV    875.8nV
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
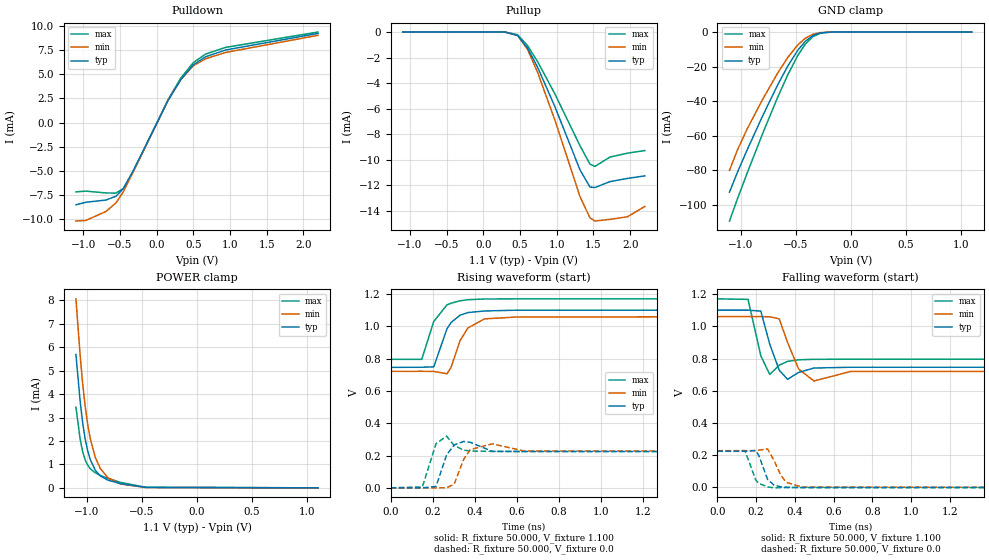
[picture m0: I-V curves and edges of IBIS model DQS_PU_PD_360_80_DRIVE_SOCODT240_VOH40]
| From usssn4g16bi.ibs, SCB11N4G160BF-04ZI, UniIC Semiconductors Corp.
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|   Model DQS_PU_PD_360_80_DRIVE_SOCODT240_VOH40
[Model] DQS_PU_PD_360_80_DRIVE_SOCODT240_VOH40
Model_type I/O
Polarity   Inverting
Vinl =  0.135V
Vinh =  0.305V
Vmeas =  0.220V
Rref =  50.000
Vref =  0.220V
C_comp   1.020pF   1.010pF   1.030pF
[Model Spec]
Vinh   0.305V   0.297V   0.319V
Vinl   0.135V   0.127V   0.149V
Vmeas   0.220V   0.212V   0.234V
Vref   0.220V   0.212V   0.234V
Rref   50.000   NA   NA
[Temperature Range]   25.000   85.000   -40.000
[Voltage Range]   1.100V   1.060V   1.170V
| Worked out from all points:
|   slope of the pulldown table from 0 to 0.165 V, typ, clamps not added: 68.2 ohm
|   GND clamp passes 1 mA (typ) near -0.30 V on its own axis
|   POWER clamp passes 1 mA (typ) near -0.95 V on its own axis
|   rising waveform, R_fixture 50.000, V_fixture 1.100: 20-80 % time 67.7ps typ, 70.7ps min, 66.1ps max; typ from 0.746 V to 1.1 V
|   rising waveform, R_fixture 50.000, V_fixture 0.0: 20-80 % time 30.7ps typ, 39.3ps min, 24.4ps max; typ from 0 V to 0.225 V
|   falling waveform, R_fixture 50.000, V_fixture 1.100: 20-80 % time 44.3ps typ, 56.4ps min, 36ps max; typ from 1.1 V to 0.746 V
|   falling waveform, R_fixture 50.000, V_fixture 0.0: 20-80 % time 42.5ps typ, 57.2ps min, 39.3ps max; typ from 0.225 V to 0 V
[Pulldown]
|Voltage   I(typ)   I(min)   I(max)
-1.1V     -8.531mA   -10.21mA   -7.187mA
-964mV    -8.264mA   -10.15mA   -7.109mA
-692mV    -8.033mA   -9.227mA   -7.298mA
-556mV    -7.649mA   -8.349mA   -7.316mA
-454mV    -6.852mA   -7.181mA   -6.833mA
-318mV    -4.969mA   -5.097mA   -5.081mA
158mV     2.325mA    2.347mA    2.407mA
328mV     4.444mA    4.448mA    4.602mA
498mV     5.984mA    5.884mA    6.211mA
668mV     6.835mA    6.624mA    7.108mA
940mV     7.53mA     7.275mA    7.801mA
2.2V      9.253mA    9.055mA    9.394mA
[Pullup]
|Voltage   I(typ)   I(min)   I(max)
-1.1V     900pA      4.512nA    0A
296mV     -5.16uA    -6.193uA   -2.645uA
466mV     -269.4uA   -269uA     -210.8uA
602mV     -1.26mA    -1.371mA   -1.066mA
738mV     -2.752mA   -3.15mA    -2.312mA
976mV     -5.863mA   -6.919mA   -4.864mA
1.316V    -10.78mA   -12.87mA   -8.894mA
1.452V    -12.12mA   -14.53mA   -10.33mA
1.52V     -12.16mA   -14.78mA   -10.51mA
1.724V    -11.7mA    -14.65mA   -9.778mA
1.962V    -11.45mA   -14.45mA   -9.476mA
2.2V      -11.25mA   -13.64mA   -9.27mA
[GND_clamp]
|Voltage   I(typ)   I(min)   I(max)
-1.1V     -92.78mA   -80.14mA   -109.5mA
-1.031V   -81.73mA   -68.77mA   -97.17mA
-939mV    -68.18mA   -56.07mA   -81.64mA
-801mV    -48.85mA   -39.25mA   -59.15mA
-663mV    -30.71mA   -23.84mA   -37.89mA
-571mV    -19.76mA   -14.75mA   -24.85mA
-479mV    -10.5mA    -7.415mA   -13.5mA
-410mV    -5.313mA   -3.546mA   -6.916mA
-341mV    -2.007mA   -1.262mA   -2.59mA
-272mV    -506.9uA   -323.5uA   -609.8uA
-180mV    -45.65uA   -36.06uA   -43.55uA
1.1V      0A         0A         0A
[POWER_clamp]
|Voltage   I(typ)   I(min)   I(max)
-1.1V     5.691mA    8.066mA    3.44mA
-1.062V   3.709mA    5.665mA    2.092mA
-1.039V   2.781mA    4.457mA    1.546mA
-1.016V   2.086mA    3.48mA     1.193mA
-993mV    1.578mA    2.707mA    966.5uA
-970mV    1.21mA     2.107mA    818.5uA
-924mV    750.8uA    1.296mA    641.3uA
-878mV    507uA      821.4uA    530.2uA
-809mV    327.4uA    430uA      403.3uA
-694mV    178.4uA    161uA      233uA
-464mV    19.89uA    15.19uA    23.61uA
1.1V      0A         0A         0A
[Ramp]
| variable   typ   min   max
dV/dt_r   0.135/30.829p   0.137/39.404p   0.135/24.625p
dV/dt_f   0.212/44.377p   0.203/56.468p   0.225/36.122p
R_load = 50.000
[Rising Waveform]
R_fixture= 50.000
V_fixture= 1.100
V_fixture_min= 1.060
V_fixture_max= 1.170
|time   V(typ)   V(min)   V(max)
0s        746mV      721mV      795.6mV
148ps     746.6mV    721.5mV    795.6mV
205ps     749.1mV    720.8mV    1.03V
268ps     985.1mV    706.3mV    1.133V
287ps     1.023V     745mV      1.143V
330ps     1.069V     911.1mV    1.158V
367ps     1.085V     989.4mV    1.165V
446ps     1.095V     1.046V     1.169V
601ps     1.1V       1.058V     1.17V
3ns       1.1V       1.06V      1.17V
[Rising Waveform]
R_fixture= 50.000
V_fixture= 0.0
V_fixture_min= 0.0
V_fixture_max= 0.0
|time   V(typ)   V(min)   V(max)
0s        3.687uV    7.015uV    860.8nV
151ps     -6.345uV   22.94uV    5.974mV
216ps     8.884mV    118.6uV    274mV
266ps     202.9mV    631.8uV    320mV
302ps     265.8mV    22.47mV    262.8mV
347ps     287.1mV    175.8mV    233.4mV
379ps     281.9mV    237.2mV    228.2mV
483ps     225.9mV    272.5mV    225.5mV
633ps     224.7mV    228.4mV    225.5mV
3ns       224.7mV    228.3mV    225.5mV
[Falling Waveform]
R_fixture= 50.000
V_fixture= 1.100
V_fixture_min= 1.060
V_fixture_max= 1.170
|time   V(typ)   V(min)   V(max)
0s        1.1V       1.06V      1.17V
158ps     1.1V       1.06V      1.167V
224ps     1.094V     1.06V      816.6mV
270ps     888.7mV    1.059V     701mV
319ps     727.5mV    1.046V     758.9mV
362ps     670.9mV    899.1mV    782.2mV
419ps     713.7mV    734.6mV    792mV
498ps     740.9mV    660.5mV    795mV
687ps     745.9mV    719.7mV    795.6mV
3ns       746mV      721mV      795.6mV
[Falling Waveform]
R_fixture= 50.000
V_fixture= 0.0
V_fixture_min= 0.0
V_fixture_max= 0.0
|time   V(typ)   V(min)   V(max)
0s        224.7mV    228.3mV    225.5mV
142ps     224.3mV    228mV      228.9mV
198ps     229.6mV    228.6mV    46.17mV
214ps     197.5mV    231.4mV    24.64mV
259ps     49.69mV    238.9mV    3.984mV
291ps     15.35mV    170.1mV    -2.236mV
327ps     4.049mV    76.65mV    -917.3uV
354ps     1.499mV    32.74mV    -328.2uV
438ps     -857.1uV   2.009mV    -12.01uV
3ns       992.1nV    6.982uV    746.8nV
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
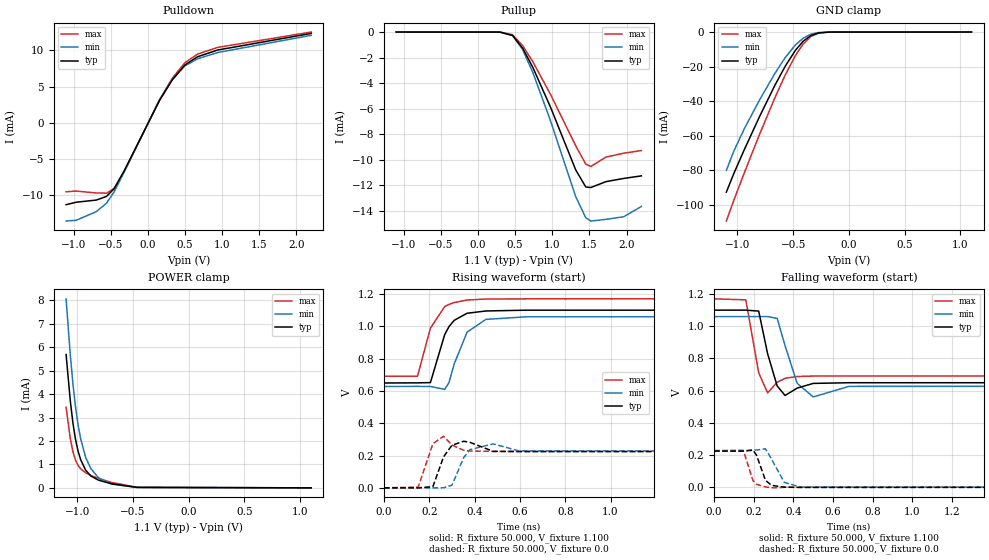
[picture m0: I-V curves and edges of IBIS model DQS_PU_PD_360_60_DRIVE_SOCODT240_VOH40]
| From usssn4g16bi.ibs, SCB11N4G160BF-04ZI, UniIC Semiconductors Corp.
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|   Model DQS_PU_PD_360_60_DRIVE_SOCODT240_VOH40
[Model] DQS_PU_PD_360_60_DRIVE_SOCODT240_VOH40
Model_type I/O
Polarity   Inverting
Vinl =  0.135V
Vinh =  0.305V
Vmeas =  0.220V
Rref =  50.000
Vref =  0.220V
C_comp   1.020pF   1.010pF   1.030pF
[Model Spec]
Vinh   0.305V   0.297V   0.319V
Vinl   0.135V   0.127V   0.149V
Vmeas   0.220V   0.212V   0.234V
Vref   0.220V   0.212V   0.234V
Rref   50.000   NA   NA
[Temperature Range]   25.000   85.000   -40.000
[Voltage Range]   1.100V   1.060V   1.170V
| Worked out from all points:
|   slope of the pulldown table from 0 to 0.165 V, typ, clamps not added: 51.2 ohm
|   GND clamp passes 1 mA (typ) near -0.30 V on its own axis
|   POWER clamp passes 1 mA (typ) near -0.95 V on its own axis
|   rising waveform, R_fixture 50.000, V_fixture 1.100: 20-80 % time 68.3ps typ, 71.7ps min, 66.6ps max; typ from 0.649 V to 1.1 V
|   rising waveform, R_fixture 50.000, V_fixture 0.0: 20-80 % time 30.6ps typ, 39.3ps min, 24.5ps max; typ from 0 V to 0.225 V
|   falling waveform, R_fixture 50.000, V_fixture 1.100: 20-80 % time 43.1ps typ, 55.2ps min, 35.2ps max; typ from 1.1 V to 0.649 V
|   falling waveform, R_fixture 50.000, V_fixture 0.0: 20-80 % time 38.4ps typ, 55.8ps min, 34.8ps max; typ from 0.225 V to 0 V
[Pulldown]
|Voltage   I(typ)   I(min)   I(max)
-1.1V     -11.28mA   -13.53mA   -9.498mA
-964mV    -10.94mA   -13.43mA   -9.404mA
-692mV    -10.64mA   -12.23mA   -9.666mA
-556mV    -10.14mA   -11.07mA   -9.692mA
-454mV    -9.086mA   -9.529mA   -9.054mA
-318mV    -6.606mA   -6.779mA   -6.751mA
158mV     3.095mA    3.124mA    3.205mA
328mV     5.919mA    5.923mA    6.128mA
498mV     7.971mA    7.839mA    8.274mA
668mV     9.107mA    8.827mA    9.472mA
940mV     10.04mA    9.694mA    10.4mA
2.2V      12.33mA    12.07mA    12.52mA
[Pullup]
|Voltage   I(typ)   I(min)   I(max)
-1.1V     900pA      4.512nA    0A
296mV     -5.16uA    -6.193uA   -2.645uA
466mV     -269.4uA   -269uA     -210.8uA
602mV     -1.26mA    -1.371mA   -1.066mA
738mV     -2.752mA   -3.15mA    -2.312mA
976mV     -5.863mA   -6.919mA   -4.864mA
1.316V    -10.78mA   -12.87mA   -8.894mA
1.452V    -12.12mA   -14.53mA   -10.33mA
1.52V     -12.16mA   -14.78mA   -10.51mA
1.724V    -11.7mA    -14.65mA   -9.778mA
1.962V    -11.45mA   -14.45mA   -9.476mA
2.2V      -11.25mA   -13.64mA   -9.27mA
[GND_clamp]
|Voltage   I(typ)   I(min)   I(max)
-1.1V     -92.78mA   -80.14mA   -109.5mA
-1.031V   -81.73mA   -68.77mA   -97.17mA
-939mV    -68.18mA   -56.07mA   -81.64mA
-801mV    -48.85mA   -39.25mA   -59.15mA
-663mV    -30.71mA   -23.84mA   -37.89mA
-571mV    -19.76mA   -14.75mA   -24.85mA
-479mV    -10.5mA    -7.415mA   -13.5mA
-410mV    -5.313mA   -3.546mA   -6.916mA
-341mV    -2.007mA   -1.262mA   -2.59mA
-272mV    -506.9uA   -323.5uA   -609.8uA
-180mV    -45.65uA   -36.06uA   -43.55uA
1.1V      0A         0A         0A
[POWER_clamp]
|Voltage   I(typ)   I(min)   I(max)
-1.1V     5.691mA    8.066mA    3.44mA
-1.062V   3.709mA    5.665mA    2.092mA
-1.039V   2.781mA    4.457mA    1.546mA
-1.016V   2.086mA    3.48mA     1.193mA
-993mV    1.578mA    2.707mA    966.5uA
-970mV    1.21mA     2.107mA    818.5uA
-924mV    750.8uA    1.296mA    641.3uA
-878mV    507uA      821.4uA    530.2uA
-809mV    327.4uA    430uA      403.3uA
-694mV    178.4uA    161uA      233uA
-464mV    19.89uA    15.19uA    23.61uA
1.1V      0A         0A         0A
[Ramp]
| variable   typ   min   max
dV/dt_r   0.135/30.703p   0.137/39.276p   0.135/24.622p
dV/dt_f   0.270/43.287p   0.259/55.211p   0.287/35.310p
R_load = 50.000
[Rising Waveform]
R_fixture= 50.000
V_fixture= 1.100
V_fixture_min= 1.060
V_fixture_max= 1.170
|time   V(typ)   V(min)   V(max)
0s        649.2mV    627.7mV    691mV
148ps     650mV      628.2mV    690.9mV
205ps     651.5mV    627.6mV    988.6mV
268ps     948.5mV    609.8mV    1.122V
287ps     998.2mV    651.8mV    1.136V
310ps     1.037V     767.3mV    1.147V
367ps     1.081V     964.5mV    1.163V
450ps     1.095V     1.043V     1.169V
629ps     1.1V       1.059V     1.17V
3ns       1.1V       1.06V      1.17V
[Rising Waveform]
R_fixture= 50.000
V_fixture= 0.0
V_fixture_min= 0.0
V_fixture_max= 0.0
|time   V(typ)   V(min)   V(max)
0s        3.216uV    6.114uV    749.1nV
151ps     57.8uV     21.53uV    4.943mV
216ps     7.513mV    224.6uV    273.1mV
263ps     191.8mV    542.8uV    319.7mV
300ps     263.5mV    16.2mV     265.4mV
352ps     288.5mV    187.2mV    232.2mV
379ps     282mV      236.3mV    228.2mV
482ps     225.9mV    272.3mV    225.5mV
595ps     224.7mV    229mV      225.5mV
3ns       224.7mV    228.3mV    225.5mV
[Falling Waveform]
R_fixture= 50.000
V_fixture= 1.100
V_fixture_min= 1.060
V_fixture_max= 1.170
|time   V(typ)   V(min)   V(max)
0s        1.1V       1.06V      1.17V
160ps     1.1V       1.06V      1.164V
225ps     1.094V     1.06V      710.7mV
270ps     829.5mV    1.06V      586.3mV
318ps     629.5mV    1.049V     651.6mV
358ps     570.1mV    879.5mV    676.9mV
419ps     615.8mV    645.7mV    687.9mV
500ps     645mV      561mV      690.6mV
680ps     649.2mV    626.4mV    691mV
3ns       649.2mV    627.7mV    691.1mV
[Falling Waveform]
R_fixture= 50.000
V_fixture= 0.0
V_fixture_min= 0.0
V_fixture_max= 0.0
|time   V(typ)   V(min)   V(max)
0s        224.7mV    228.3mV    225.5mV
143ps     224.3mV    228mV      228.8mV
153ps     225.3mV    227.9mV    208.3mV
196ps     231.5mV    228.3mV    42.06mV
214ps     199.4mV    231.3mV    18.38mV
259ps     43.54mV    238.8mV    2.253mV
290ps     11.76mV    174.4mV    -3.69mV
354ps     852.4uV    30.25mV    -376.1uV
434ps     -1.203mV   1.565mV    -10.02uV
3ns       -1.517uV   6.074uV    500.9nV
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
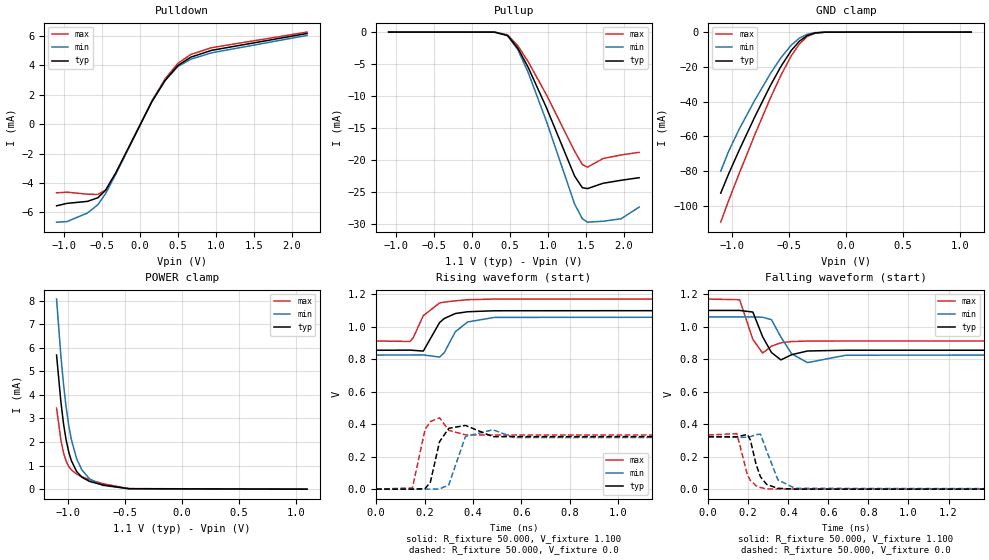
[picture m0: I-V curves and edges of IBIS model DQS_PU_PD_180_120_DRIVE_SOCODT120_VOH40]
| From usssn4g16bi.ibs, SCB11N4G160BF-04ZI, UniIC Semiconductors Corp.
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|   Model DQS_PU_PD_180_120_DRIVE_SOCODT120_VOH40
[Model] DQS_PU_PD_180_120_DRIVE_SOCODT120_VOH40
Model_type I/O
Polarity   Inverting
Vinl =  0.135V
Vinh =  0.305V
Vmeas =  0.220V
Rref =  50.000
Vref =  0.220V
C_comp   1.020pF   1.010pF   1.030pF
[Model Spec]
Vinh   0.305V   0.297V   0.319V
Vinl   0.135V   0.127V   0.149V
Vmeas   0.220V   0.212V   0.234V
Vref   0.220V   0.212V   0.234V
Rref   50.000   NA   NA
[Temperature Range]   25.000   85.000   -40.000
[Voltage Range]   1.100V   1.060V   1.170V
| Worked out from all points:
|   slope of the pulldown table from 0 to 0.165 V, typ, clamps not added: 102 ohm
|   GND clamp passes 1 mA (typ) near -0.30 V on its own axis
|   POWER clamp passes 1 mA (typ) near -0.95 V on its own axis
|   rising waveform, R_fixture 50.000, V_fixture 1.100: 20-80 % time 63.7ps typ, 65.1ps min, 64.7ps max; typ from 0.855 V to 1.1 V
|   rising waveform, R_fixture 50.000, V_fixture 0.0: 20-80 % time 27.6ps typ, 35.2ps min, 21.7ps max; typ from 0 V to 0.323 V
|   falling waveform, R_fixture 50.000, V_fixture 1.100: 20-80 % time 45.2ps typ, 58.4ps min, 36.3ps max; typ from 1.1 V to 0.855 V
|   falling waveform, R_fixture 50.000, V_fixture 0.0: 20-80 % time 46.2ps typ, 56.7ps min, 43.6ps max; typ from 0.323 V to 0 V
[Pulldown]
|Voltage   I(typ)   I(min)   I(max)
-1.1V     -5.559mA   -6.673mA   -4.673mA
-964mV    -5.394mA   -6.634mA   -4.631mA
-692mV    -5.255mA   -6.046mA   -4.769mA
-556mV    -5.011mA   -5.482mA   -4.784mA
-454mV    -4.503mA   -4.733mA   -4.479mA
-318mV    -3.293mA   -3.384mA   -3.363mA
158mV     1.547mA    1.562mA    1.602mA
328mV     2.959mA    2.962mA    3.064mA
498mV     3.986mA    3.92mA     4.137mA
668mV     4.555mA    4.415mA    4.737mA
940mV     5.019mA    4.85mA     5.2mA
2.2V      6.168mA    6.037mA    6.263mA
[Pullup]
|Voltage   I(typ)   I(min)   I(max)
-1.1V     1.8nA      9.024nA    0A
296mV     -10.32uA   -12.39uA   -5.289uA
466mV     -538.9uA   -538.1uA   -421.8uA
602mV     -2.521mA   -2.744mA   -2.134mA
738mV     -5.508mA   -6.307mA   -4.628mA
976mV     -11.74mA   -13.85mA   -9.734mA
1.35V     -22.51mA   -26.87mA   -18.62mA
1.452V    -24.32mA   -29.17mA   -20.7mA
1.52V     -24.46mA   -29.71mA   -21.11mA
1.724V    -23.63mA   -29.56mA   -19.76mA
1.962V    -23.16mA   -29.18mA   -19.2mA
2.2V      -22.76mA   -27.35mA   -18.79mA
[GND_clamp]
|Voltage   I(typ)   I(min)   I(max)
-1.1V     -92.78mA   -80.14mA   -109.5mA
-1.031V   -81.73mA   -68.77mA   -97.17mA
-939mV    -68.18mA   -56.07mA   -81.64mA
-801mV    -48.85mA   -39.25mA   -59.15mA
-663mV    -30.71mA   -23.84mA   -37.89mA
-571mV    -19.76mA   -14.75mA   -24.85mA
-479mV    -10.5mA    -7.415mA   -13.5mA
-410mV    -5.313mA   -3.546mA   -6.916mA
-341mV    -2.007mA   -1.262mA   -2.59mA
-272mV    -506.9uA   -323.5uA   -609.8uA
-180mV    -45.65uA   -36.06uA   -43.55uA
1.1V      0A         0A         0A
[POWER_clamp]
|Voltage   I(typ)   I(min)   I(max)
-1.1V     5.691mA    8.066mA    3.44mA
-1.062V   3.709mA    5.665mA    2.092mA
-1.039V   2.781mA    4.457mA    1.546mA
-1.016V   2.086mA    3.48mA     1.193mA
-993mV    1.578mA    2.707mA    966.5uA
-970mV    1.21mA     2.107mA    818.5uA
-924mV    750.8uA    1.296mA    641.3uA
-878mV    507uA      821.4uA    530.2uA
-809mV    327.4uA    430uA      403.3uA
-694mV    178.4uA    161uA      233uA
-464mV    19.89uA    15.19uA    23.61uA
1.1V      0A         0A         0A
[Ramp]
| variable   typ   min   max
dV/dt_r   0.194/27.577p   0.192/35.302p   0.200/21.873p
dV/dt_f   0.147/45.337p   0.141/58.520p   0.155/36.321p
R_load = 50.000
[Rising Waveform]
R_fixture= 50.000
V_fixture= 1.100
V_fixture_min= 1.060
V_fixture_max= 1.170
|time   V(typ)   V(min)   V(max)
0s        855mV      825.4mV    911.8mV
140ps     855.6mV    825.7mV    909.1mV
153ps     854.4mV    826mV      931.4mV
195ps     850mV      825.9mV    1.068V
262ps     1.025V     813mV      1.146V
281ps     1.05V      838.8mV    1.151V
327ps     1.081V     968.6mV    1.159V
378ps     1.092V     1.029V     1.166V
488ps     1.098V     1.057V     1.17V
3ns       1.1V       1.06V      1.17V
[Rising Waveform]
R_fixture= 50.000
V_fixture= 0.0
V_fixture_min= 0.0
V_fixture_max= 0.0
|time   V(typ)   V(min)   V(max)
0s        4.315uV    8.22uV     1.011uV
150ps     -150.3uV   54.47uV    7.275mV
202ps     2.946mV    -114uV     367.4mV
224ps     42.51mV    -224.3uV   415.3mV
262ps     292.2mV    532.1uV    439.1mV
300ps     374.1mV    26.68mV    362mV
369ps     392.2mV    323.7mV    334mV
482ps     322.9mV    365.5mV    333.3mV
569ps     323.1mV    317.7mV    333.3mV
3ns       323.1mV    319.3mV    333.3mV
[Falling Waveform]
R_fixture= 50.000
V_fixture= 1.100
V_fixture_min= 1.060
V_fixture_max= 1.170
|time   V(typ)   V(min)   V(max)
0s        1.1V       1.06V      1.17V
157ps     1.1V       1.06V      1.166V
223ps     1.09V      1.06V      921.6mV
272ps     937.5mV    1.058V     837.3mV
316ps     840.9mV    1.043V     880.1mV
363ps     795.4mV    935.8mV    900.9mV
417ps     827.7mV    832.7mV    908.5mV
496ps     850.3mV    778.7mV    911.2mV
688ps     854.9mV    824.4mV    911.8mV
3ns       855mV      825.4mV    911.8mV
[Falling Waveform]
R_fixture= 50.000
V_fixture= 0.0
V_fixture_min= 0.0
V_fixture_max= 0.0
|time   V(typ)   V(min)   V(max)
0s        323.1mV    319.3mV    333.3mV
143ps     322.3mV    318.8mV    341.5mV
196ps     336.3mV    319mV      86.97mV
211ps     300.7mV    322.5mV    52.88mV
239ps     152mV      335.6mV    20.77mV
261ps     75.89mV    337.8mV    9.728mV
292ps     28.48mV    235.5mV    1.219mV
348ps     4.936mV    57.14mV    113uV
434ps     -514.8uV   4.506mV    10.16uV
3ns       4.093uV    8.106uV    963.8nV
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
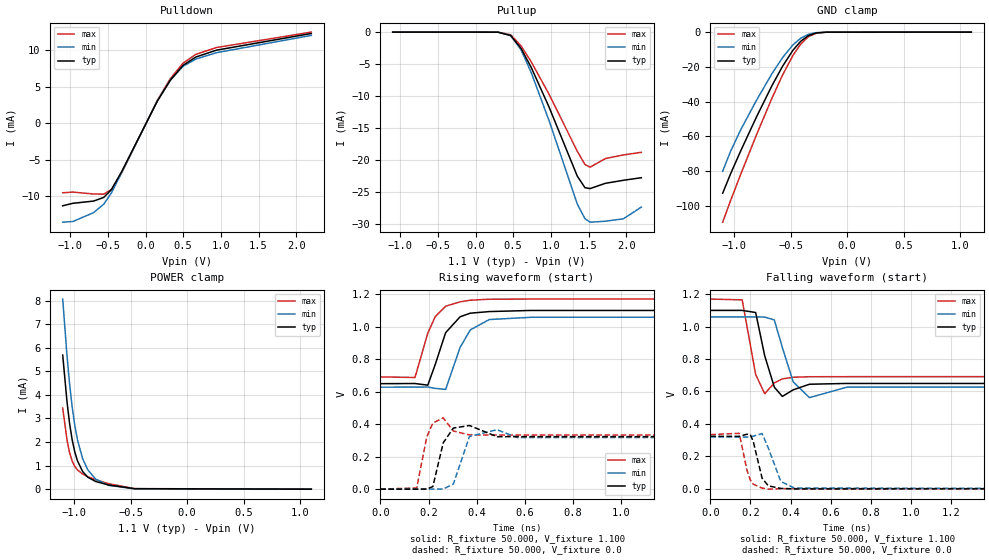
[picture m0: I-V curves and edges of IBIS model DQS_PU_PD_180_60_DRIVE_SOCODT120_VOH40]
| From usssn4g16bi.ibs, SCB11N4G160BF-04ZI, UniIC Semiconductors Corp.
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|   Model DQS_PU_PD_180_60_DRIVE_SOCODT120_VOH40
[Model] DQS_PU_PD_180_60_DRIVE_SOCODT120_VOH40
Model_type I/O
Polarity   Inverting
Vinl =  0.135V
Vinh =  0.305V
Vmeas =  0.220V
Rref =  50.000
Vref =  0.220V
C_comp   1.020pF   1.010pF   1.030pF
[Model Spec]
Vinh   0.305V   0.297V   0.319V
Vinl   0.135V   0.127V   0.149V
Vmeas   0.220V   0.212V   0.234V
Vref   0.220V   0.212V   0.234V
Rref   50.000   NA   NA
[Temperature Range]   25.000   85.000   -40.000
[Voltage Range]   1.100V   1.060V   1.170V
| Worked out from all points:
|   slope of the pulldown table from 0 to 0.165 V, typ, clamps not added: 51.2 ohm
|   GND clamp passes 1 mA (typ) near -0.30 V on its own axis
|   POWER clamp passes 1 mA (typ) near -0.95 V on its own axis
|   rising waveform, R_fixture 50.000, V_fixture 1.100: 20-80 % time 67.4ps typ, 70.2ps min, 66.4ps max; typ from 0.649 V to 1.1 V
|   rising waveform, R_fixture 50.000, V_fixture 0.0: 20-80 % time 27.3ps typ, 35ps min, 21.7ps max; typ from 0 V to 0.323 V
|   falling waveform, R_fixture 50.000, V_fixture 1.100: 20-80 % time 43.5ps typ, 55.9ps min, 35.4ps max; typ from 1.1 V to 0.649 V
|   falling waveform, R_fixture 50.000, V_fixture 0.0: 20-80 % time 37.4ps typ, 53.5ps min, 33.9ps max; typ from 0.323 V to 0 V
[Pulldown]
|Voltage   I(typ)   I(min)   I(max)
-1.1V     -11.28mA   -13.53mA   -9.498mA
-964mV    -10.94mA   -13.43mA   -9.404mA
-692mV    -10.64mA   -12.23mA   -9.666mA
-556mV    -10.14mA   -11.07mA   -9.692mA
-454mV    -9.086mA   -9.529mA   -9.054mA
-318mV    -6.606mA   -6.779mA   -6.751mA
158mV     3.095mA    3.124mA    3.205mA
328mV     5.919mA    5.923mA    6.128mA
498mV     7.971mA    7.839mA    8.274mA
668mV     9.107mA    8.827mA    9.472mA
940mV     10.04mA    9.694mA    10.4mA
2.2V      12.33mA    12.07mA    12.52mA
[Pullup]
|Voltage   I(typ)   I(min)   I(max)
-1.1V     1.8nA      9.024nA    0A
296mV     -10.32uA   -12.39uA   -5.289uA
466mV     -538.9uA   -538.1uA   -421.8uA
602mV     -2.521mA   -2.744mA   -2.134mA
738mV     -5.508mA   -6.307mA   -4.628mA
976mV     -11.74mA   -13.85mA   -9.734mA
1.35V     -22.51mA   -26.87mA   -18.62mA
1.452V    -24.32mA   -29.17mA   -20.7mA
1.52V     -24.46mA   -29.71mA   -21.11mA
1.724V    -23.63mA   -29.56mA   -19.76mA
1.962V    -23.16mA   -29.18mA   -19.2mA
2.2V      -22.76mA   -27.35mA   -18.79mA
[GND_clamp]
|Voltage   I(typ)   I(min)   I(max)
-1.1V     -92.78mA   -80.14mA   -109.5mA
-1.031V   -81.73mA   -68.77mA   -97.17mA
-939mV    -68.18mA   -56.07mA   -81.64mA
-801mV    -48.85mA   -39.25mA   -59.15mA
-663mV    -30.71mA   -23.84mA   -37.89mA
-571mV    -19.76mA   -14.75mA   -24.85mA
-479mV    -10.5mA    -7.415mA   -13.5mA
-410mV    -5.313mA   -3.546mA   -6.916mA
-341mV    -2.007mA   -1.262mA   -2.59mA
-272mV    -506.9uA   -323.5uA   -609.8uA
-180mV    -45.65uA   -36.06uA   -43.55uA
1.1V      0A         0A         0A
[POWER_clamp]
|Voltage   I(typ)   I(min)   I(max)
-1.1V     5.691mA    8.066mA    3.44mA
-1.062V   3.709mA    5.665mA    2.092mA
-1.039V   2.781mA    4.457mA    1.546mA
-1.016V   2.086mA    3.48mA     1.193mA
-993mV    1.578mA    2.707mA    966.5uA
-970mV    1.21mA     2.107mA    818.5uA
-924mV    750.8uA    1.296mA    641.3uA
-878mV    507uA      821.4uA    530.2uA
-809mV    327.4uA    430uA      403.3uA
-694mV    178.4uA    161uA      233uA
-464mV    19.89uA    15.19uA    23.61uA
1.1V      0A         0A         0A
[Ramp]
| variable   typ   min   max
dV/dt_r   0.194/27.375p   0.192/34.955p   0.200/21.900p
dV/dt_f   0.270/43.580p   0.259/55.930p   0.287/35.521p
R_load = 50.000
[Rising Waveform]
R_fixture= 50.000
V_fixture= 1.100
V_fixture_min= 1.060
V_fixture_max= 1.170
|time   V(typ)   V(min)   V(max)
0s        649.2mV    627.7mV    691mV
144ps     650.2mV    628.1mV    687.4mV
197ps     640.1mV    628.7mV    960.2mV
228ps     768mV      620.2mV    1.062V
271ps     963.1mV    613.8mV    1.126V
331ps     1.061V     872.3mV    1.153V
373ps     1.083V     980mV      1.163V
452ps     1.093V     1.044V     1.169V
627ps     1.1V       1.058V     1.17V
3ns       1.1V       1.06V      1.17V
[Rising Waveform]
R_fixture= 50.000
V_fixture= 0.0
V_fixture_min= 0.0
V_fixture_max= 0.0
|time   V(typ)   V(min)   V(max)
0s        3.216uV    6.114uV    749.1nV
151ps     -66.67uV   37.82uV    7.594mV
193ps     947.2uV    6.891uV    322mV
218ps     15.77mV    47.73uV    406.7mV
261ps     285.3mV    608.3uV    438.9mV
303ps     376mV      31.52mV    357.5mV
370ps     391.7mV    324.4mV    333.9mV
484ps     322.9mV    365.8mV    333.3mV
567ps     323.1mV    317.9mV    333.3mV
3ns       323.1mV    319.3mV    333.3mV
[Falling Waveform]
R_fixture= 50.000
V_fixture= 1.100
V_fixture_min= 1.060
V_fixture_max= 1.170
|time   V(typ)   V(min)   V(max)
0s        1.1V       1.06V      1.17V
159ps     1.1V       1.06V      1.165V
226ps     1.087V     1.06V      704.6mV
271ps     820.4mV    1.059V     585.6mV
319ps     626.2mV    1.041V     652.6mV
359ps     569mV      870.7mV    677.2mV
413ps     609.8mV    658.8mV    687.4mV
494ps     644.3mV    561.6mV    690.5mV
681ps     649.2mV    626.4mV    691mV
3ns       649.2mV    627.7mV    691.1mV
[Falling Waveform]
R_fixture= 50.000
V_fixture= 0.0
V_fixture_min= 0.0
V_fixture_max= 0.0
|time   V(typ)   V(min)   V(max)
0s        323.1mV    319.3mV    333.3mV
144ps     322.3mV    318.8mV    341.3mV
183ps     335.8mV    318.1mV    112.6mV
199ps     334mV      319.4mV    54.21mV
214ps     291.1mV    323.4mV    27.05mV
258ps     64.75mV    340.1mV    3.427mV
289ps     17.07mV    251.2mV    -3.37mV
351ps     1.308mV    44.39mV    -419.3uV
419ps     -2.08mV    3.277mV    -18.65uV
3ns       3.115uV    6.053uV    604.1nV
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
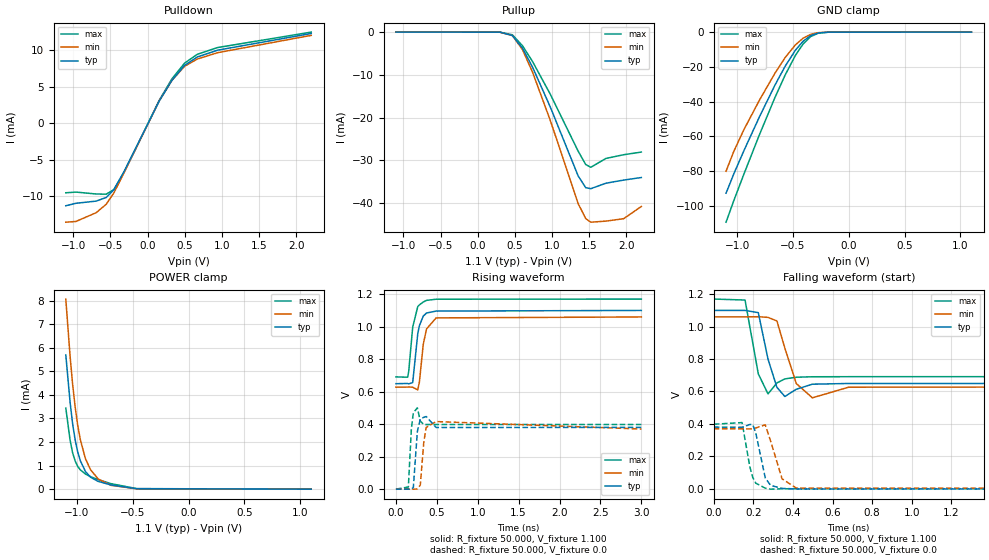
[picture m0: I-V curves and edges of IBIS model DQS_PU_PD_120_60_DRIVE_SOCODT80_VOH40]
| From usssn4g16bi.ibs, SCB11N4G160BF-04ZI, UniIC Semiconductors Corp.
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|   Model DQS_PU_PD_120_60_DRIVE_SOCODT80_VOH40
[Model] DQS_PU_PD_120_60_DRIVE_SOCODT80_VOH40
Model_type I/O
Polarity   Inverting
Vinl =  0.135V
Vinh =  0.305V
Vmeas =  0.220V
Rref =  50.000
Vref =  0.220V
C_comp   1.020pF   1.010pF   1.030pF
[Model Spec]
Vinh   0.305V   0.297V   0.319V
Vinl   0.135V   0.127V   0.149V
Vmeas   0.220V   0.212V   0.234V
Vref   0.220V   0.212V   0.234V
Rref   50.000   NA   NA
[Temperature Range]   25.000   85.000   -40.000
[Voltage Range]   1.100V   1.060V   1.170V
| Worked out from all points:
|   slope of the pulldown table from 0 to 0.165 V, typ, clamps not added: 51.2 ohm
|   GND clamp passes 1 mA (typ) near -0.30 V on its own axis
|   POWER clamp passes 1 mA (typ) near -0.95 V on its own axis
|   rising waveform, R_fixture 50.000, V_fixture 1.100: 20-80 % time 66.3ps typ, 68.5ps min, 66.2ps max; typ from 0.649 V to 1.1 V
|   rising waveform, R_fixture 50.000, V_fixture 0.0: 20-80 % time 25.6ps typ, 33.2ps min, 20.3ps max; typ from 0 V to 0.38 V
|   falling waveform, R_fixture 50.000, V_fixture 1.100: 20-80 % time 43.8ps typ, 56.6ps min, 35.6ps max; typ from 1.1 V to 0.649 V
|   falling waveform, R_fixture 50.000, V_fixture 0.0: 20-80 % time 37.9ps typ, 53.2ps min, 34.4ps max; typ from 0.38 V to 0 V
[Pulldown]
|Voltage   I(typ)   I(min)   I(max)
-1.1V     -11.28mA   -13.53mA   -9.498mA
-964mV    -10.94mA   -13.43mA   -9.404mA
-692mV    -10.64mA   -12.23mA   -9.666mA
-556mV    -10.14mA   -11.07mA   -9.692mA
-454mV    -9.086mA   -9.529mA   -9.054mA
-318mV    -6.606mA   -6.779mA   -6.751mA
158mV     3.095mA    3.124mA    3.205mA
328mV     5.919mA    5.923mA    6.128mA
498mV     7.971mA    7.839mA    8.274mA
668mV     9.107mA    8.827mA    9.472mA
940mV     10.04mA    9.694mA    10.4mA
2.2V      12.33mA    12.07mA    12.52mA
[Pullup]
|Voltage   I(typ)   I(min)   I(max)
-1.1V     2.7nA      13.54nA    0A
296mV     -15.48uA   -18.58uA   -7.934uA
466mV     -807.4uA   -806.2uA   -632uA
602mV     -3.772mA   -4.103mA   -3.194mA
738mV     -8.234mA   -9.422mA   -6.922mA
976mV     -17.54mA   -20.68mA   -14.55mA
1.35V     -33.63mA   -40.11mA   -27.84mA
1.452V    -36.39mA   -43.62mA   -30.97mA
1.52V     -36.62mA   -44.46mA   -31.62mA
1.724V    -35.34mA   -44.21mA   -29.55mA
1.962V    -34.61mA   -43.64mA   -28.68mA
2.2V      -34.01mA   -40.78mA   -28.06mA
[GND_clamp]
|Voltage   I(typ)   I(min)   I(max)
-1.1V     -92.78mA   -80.14mA   -109.5mA
-1.031V   -81.73mA   -68.77mA   -97.17mA
-939mV    -68.18mA   -56.07mA   -81.64mA
-801mV    -48.85mA   -39.25mA   -59.15mA
-663mV    -30.71mA   -23.84mA   -37.89mA
-571mV    -19.76mA   -14.75mA   -24.85mA
-479mV    -10.5mA    -7.415mA   -13.5mA
-410mV    -5.313mA   -3.546mA   -6.916mA
-341mV    -2.007mA   -1.262mA   -2.59mA
-272mV    -506.9uA   -323.5uA   -609.8uA
-180mV    -45.65uA   -36.06uA   -43.55uA
1.1V      0A         0A         0A
[POWER_clamp]
|Voltage   I(typ)   I(min)   I(max)
-1.1V     5.691mA    8.066mA    3.44mA
-1.062V   3.709mA    5.665mA    2.092mA
-1.039V   2.781mA    4.457mA    1.546mA
-1.016V   2.086mA    3.48mA     1.193mA
-993mV    1.578mA    2.707mA    966.5uA
-970mV    1.21mA     2.107mA    818.5uA
-924mV    750.8uA    1.296mA    641.3uA
-878mV    507uA      821.4uA    530.2uA
-809mV    327.4uA    430uA      403.3uA
-694mV    178.4uA    161uA      233uA
-464mV    19.89uA    15.19uA    23.61uA
1.1V      0A         0A         0A
[Ramp]
| variable   typ   min   max
dV/dt_r   0.228/25.818p   0.222/33.400p   0.239/20.550p
dV/dt_f   0.270/43.908p   0.259/56.661p   0.287/35.675p
R_load = 50.000
[Rising Waveform]
R_fixture= 50.000
V_fixture= 1.100
V_fixture_min= 1.060
V_fixture_max= 1.170
|time   V(typ)   V(min)   V(max)
0s        649.2mV    627.7mV    691mV
144ps     650.2mV    628.1mV    689mV
157ps     648.2mV    628.6mV    727.9mV
205ps     655.9mV    627.4mV    997mV
267ps     956.8mV    610.9mV    1.124V
287ps     1.006V     659.2mV    1.134V
334ps     1.065V     890.9mV    1.152V
374ps     1.084V     985.9mV    1.162V
491ps     1.096V     1.054V     1.169V
3ns       1.1V       1.06V      1.17V
[Rising Waveform]
R_fixture= 50.000
V_fixture= 0.0
V_fixture_min= 0.0
V_fixture_max= 0.0
|time   V(typ)   V(min)   V(max)
0s        3.216uV    6.114uV    749.1nV
152ps     -206.7uV   55.04uV    13.3mV
189ps     613.8uV    1.708uV    374mV
213ps     10.63mV    -147.8uV   470mV
262ps     355.1mV    970.5uV    500.3mV
298ps     431.2mV    25.41mV    419.3mV
341ps     442.4mV    291mV      397.5mV
370ps     446.8mV    379.9mV    397.5mV
491ps     379.6mV    415.9mV    397.7mV
3ns       379.9mV    370mV      397.7mV
[Falling Waveform]
R_fixture= 50.000
V_fixture= 1.100
V_fixture_min= 1.060
V_fixture_max= 1.170
|time   V(typ)   V(min)   V(max)
0s        1.1V       1.06V      1.17V
158ps     1.1V       1.06V      1.164V
225ps     1.086V     1.061V     708.4mV
274ps     799.4mV    1.057V     585mV
319ps     625.4mV    1.035V     652.5mV
359ps     568.8mV    867.7mV    677.3mV
417ps     613.5mV    648.6mV    687.8mV
498ps     644.7mV    560.7mV    690.6mV
682ps     649.2mV    626.4mV    691mV
3ns       649.2mV    627.7mV    691.1mV
[Falling Waveform]
R_fixture= 50.000
V_fixture= 0.0
V_fixture_min= 0.0
V_fixture_max= 0.0
|time   V(typ)   V(min)   V(max)
0s        379.9mV    370mV      397.7mV
143ps     379mV      369.4mV    407.9mV
182ps     396mV      368.6mV    136.3mV
197ps     395.2mV    370mV      68.87mV
212ps     345.3mV    374.6mV    34.21mV
260ps     66.93mV    394.1mV    3.417mV
287ps     20.5mV     294.7mV    -2.965mV
345ps     1.838mV    60.66mV    -537.2uV
417ps     -2.216mV   3.762mV    -19.48uV
3ns       1.81uV     5.366uV    439.6nV
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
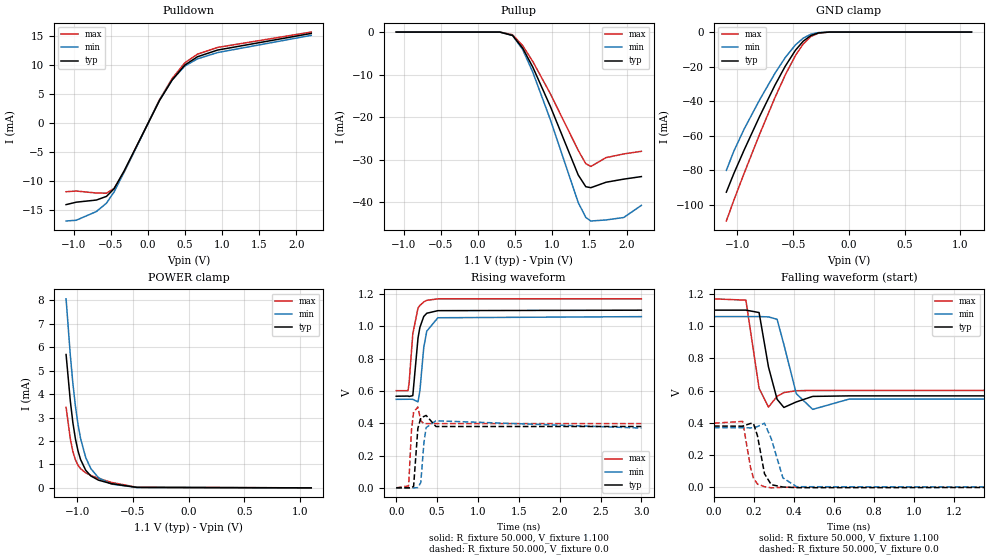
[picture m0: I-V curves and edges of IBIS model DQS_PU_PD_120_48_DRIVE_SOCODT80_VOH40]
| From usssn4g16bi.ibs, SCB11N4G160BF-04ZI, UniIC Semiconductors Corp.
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|   Model DQS_PU_PD_120_48_DRIVE_SOCODT80_VOH40
[Model] DQS_PU_PD_120_48_DRIVE_SOCODT80_VOH40
Model_type I/O
Polarity   Inverting
Vinl =  0.135V
Vinh =  0.305V
Vmeas =  0.220V
Rref =  50.000
Vref =  0.220V
C_comp   1.020pF   1.010pF   1.030pF
[Model Spec]
Vinh   0.305V   0.297V   0.319V
Vinl   0.135V   0.127V   0.149V
Vmeas   0.220V   0.212V   0.234V
Vref   0.220V   0.212V   0.234V
Rref   50.000   NA   NA
[Temperature Range]   25.000   85.000   -40.000
[Voltage Range]   1.100V   1.060V   1.170V
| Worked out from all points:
|   slope of the pulldown table from 0 to 0.165 V, typ, clamps not added: 41 ohm
|   GND clamp passes 1 mA (typ) near -0.30 V on its own axis
|   POWER clamp passes 1 mA (typ) near -0.95 V on its own axis
|   rising waveform, R_fixture 50.000, V_fixture 1.100: 20-80 % time 67.2ps typ, 69.7ps min, 66.6ps max; typ from 0.567 V to 1.1 V
|   rising waveform, R_fixture 50.000, V_fixture 0.0: 20-80 % time 25.4ps typ, 33.1ps min, 20.2ps max; typ from 0 V to 0.38 V
|   falling waveform, R_fixture 50.000, V_fixture 1.100: 20-80 % time 42.1ps typ, 54.4ps min, 34.5ps max; typ from 1.1 V to 0.567 V
|   falling waveform, R_fixture 50.000, V_fixture 0.0: 20-80 % time 34.6ps typ, 51.1ps min, 31ps max; typ from 0.38 V to 0 V
[Pulldown]
|Voltage   I(typ)   I(min)   I(max)
-1.1V     -14.07mA   -16.89mA   -11.85mA
-964mV    -13.65mA   -16.76mA   -11.73mA
-692mV    -13.28mA   -15.26mA   -12.07mA
-556mV    -12.65mA   -13.81mA   -12.1mA
-454mV    -11.34mA   -11.89mA   -11.29mA
-318mV    -8.242mA   -8.458mA   -8.422mA
158mV     3.863mA    3.899mA    4mA
328mV     7.389mA    7.394mA    7.65mA
498mV     9.955mA    9.787mA    10.33mA
668mV     11.38mA    11.02mA    11.83mA
940mV     12.54mA    12.11mA    12.99mA
2.2V      15.4mA     15.07mA    15.64mA
[Pullup]
|Voltage   I(typ)   I(min)   I(max)
-1.1V     2.7nA      13.54nA    0A
296mV     -15.48uA   -18.58uA   -7.934uA
466mV     -807.4uA   -806.2uA   -632uA
602mV     -3.772mA   -4.103mA   -3.194mA
738mV     -8.234mA   -9.422mA   -6.922mA
976mV     -17.54mA   -20.68mA   -14.55mA
1.35V     -33.63mA   -40.11mA   -27.84mA
1.452V    -36.39mA   -43.62mA   -30.97mA
1.52V     -36.62mA   -44.46mA   -31.62mA
1.724V    -35.34mA   -44.21mA   -29.55mA
1.962V    -34.61mA   -43.64mA   -28.68mA
2.2V      -34.01mA   -40.78mA   -28.06mA
[GND_clamp]
|Voltage   I(typ)   I(min)   I(max)
-1.1V     -92.78mA   -80.14mA   -109.5mA
-1.031V   -81.73mA   -68.77mA   -97.17mA
-939mV    -68.18mA   -56.07mA   -81.64mA
-801mV    -48.85mA   -39.25mA   -59.15mA
-663mV    -30.71mA   -23.84mA   -37.89mA
-571mV    -19.76mA   -14.75mA   -24.85mA
-479mV    -10.5mA    -7.415mA   -13.5mA
-410mV    -5.313mA   -3.546mA   -6.916mA
-341mV    -2.007mA   -1.262mA   -2.59mA
-272mV    -506.9uA   -323.5uA   -609.8uA
-180mV    -45.65uA   -36.06uA   -43.55uA
1.1V      0A         0A         0A
[POWER_clamp]
|Voltage   I(typ)   I(min)   I(max)
-1.1V     5.691mA    8.066mA    3.44mA
-1.062V   3.709mA    5.665mA    2.092mA
-1.039V   2.781mA    4.457mA    1.546mA
-1.016V   2.086mA    3.48mA     1.193mA
-993mV    1.578mA    2.707mA    966.5uA
-970mV    1.21mA     2.107mA    818.5uA
-924mV    750.8uA    1.296mA    641.3uA
-878mV    507uA      821.4uA    530.2uA
-809mV    327.4uA    430uA      403.3uA
-694mV    178.4uA    161uA      233uA
-464mV    19.89uA    15.19uA    23.61uA
1.1V      0A         0A         0A
[Ramp]
| variable   typ   min   max
dV/dt_r   0.228/25.616p   0.222/33.179p   0.239/20.510p
dV/dt_f   0.320/42.157p   0.307/54.556p   0.341/34.464p
R_load = 50.000
[Rising Waveform]
R_fixture= 50.000
V_fixture= 1.100
V_fixture_min= 1.060
V_fixture_max= 1.170
|time   V(typ)   V(min)   V(max)
0s        567.3mV    547.9mV    601.6mV
145ps     568.2mV    548.4mV    601.5mV
158ps     565.9mV    548.9mV    650.4mV
203ps     570.7mV    547.9mV    953.4mV
267ps     928.2mV    532.2mV    1.114V
290ps     993.7mV    601.8mV    1.129V
337ps     1.061V     868.4mV    1.151V
374ps     1.081V     970.1mV    1.161V
510ps     1.097V     1.053V     1.17V
3ns       1.1V       1.06V      1.17V
[Rising Waveform]
R_fixture= 50.000
V_fixture= 0.0
V_fixture_min= 0.0
V_fixture_max= 0.0
|time   V(typ)   V(min)   V(max)
0s        2.854uV    5.42uV     663.5nV
152ps     -120.3uV   49.36uV    11.92mV
187ps     285.8uV    41.99uV    357.5mV
213ps     9.402mV    -17.73uV   469.5mV
265ps     368.4mV    1.053mV    500.5mV
301ps     432.5mV    32.77mV    414.3mV
339ps     441.9mV    279.2mV    397.5mV
366ps     448.3mV    372.9mV    397.5mV
486ps     379.6mV    415mV      397.7mV
3ns       379.9mV    370mV      397.7mV
[Falling Waveform]
R_fixture= 50.000
V_fixture= 1.100
V_fixture_min= 1.060
V_fixture_max= 1.170
|time   V(typ)   V(min)   V(max)
0s        1.1V       1.06V      1.17V
159ps     1.1V       1.06V      1.162V
225ps     1.085V     1.06V      614.8mV
272ps     746.7mV    1.058V     497.7mV
315ps     546.2mV    1.043V     564.3mV
349ps     495.4mV    885.9mV    588.1mV
411ps     529.8mV    581mV      599.3mV
493ps     564.1mV    483.5mV    601.4mV
674ps     567.3mV    547mV      601.6mV
3ns       567.3mV    547.9mV    601.6mV
[Falling Waveform]
R_fixture= 50.000
V_fixture= 0.0
V_fixture_min= 0.0
V_fixture_max= 0.0
|time   V(typ)   V(min)   V(max)
0s        379.9mV    370mV      397.7mV
143ps     379mV      369.4mV    408.6mV
182ps     396mV      368.6mV    123.9mV
197ps     395.7mV    369.9mV    56.69mV
217ps     319.1mV    376.8mV    19.27mV
252ps     83.76mV    397.4mV    3.204mV
286ps     15.63mV    301.2mV    -3.986mV
344ps     1.146mV    57.84mV    -575.2uV
413ps     -2.959mV   3.05mV     -14.87uV
3ns       1.265uV    4.649uV    327.3nV
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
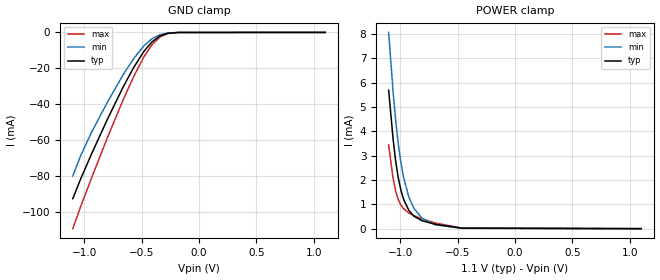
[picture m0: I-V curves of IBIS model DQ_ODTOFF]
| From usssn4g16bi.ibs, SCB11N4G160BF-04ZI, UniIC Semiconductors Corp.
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|   Model DQ_ODTOFF
[Model] DQ_ODTOFF
Model_type Input
Vinl =  98.000mV
Vinh =  0.268V
C_comp   1.020pF   1.010pF   1.030pF
[Model Spec]
Vinh   0.268V   0.262V   0.280V
Vinl   98.000mV   92.000mV   0.110V
[Temperature Range]   25.000   85.000   -40.000
[Voltage Range]   1.100V   1.060V   1.170V
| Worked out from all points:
|   GND clamp passes 1 mA (typ) near -0.30 V on its own axis
|   POWER clamp passes 1 mA (typ) near -0.95 V on its own axis
[GND_clamp]
|Voltage   I(typ)   I(min)   I(max)
-1.1V     -92.78mA   -80.14mA   -109.5mA
-1.031V   -81.73mA   -68.77mA   -97.17mA
-939mV    -68.18mA   -56.07mA   -81.64mA
-801mV    -48.85mA   -39.25mA   -59.15mA
-663mV    -30.71mA   -23.84mA   -37.89mA
-571mV    -19.76mA   -14.75mA   -24.85mA
-479mV    -10.5mA    -7.415mA   -13.5mA
-410mV    -5.313mA   -3.546mA   -6.916mA
-341mV    -2.007mA   -1.262mA   -2.59mA
-272mV    -506.9uA   -323.5uA   -609.8uA
-180mV    -45.65uA   -36.06uA   -43.55uA
1.1V      0A         0A         0A
[POWER_clamp]
|Voltage   I(typ)   I(min)   I(max)
-1.1V     5.691mA    8.066mA    3.44mA
-1.062V   3.709mA    5.665mA    2.092mA
-1.039V   2.781mA    4.457mA    1.546mA
-1.016V   2.086mA    3.48mA     1.193mA
-993mV    1.578mA    2.707mA    966.5uA
-970mV    1.21mA     2.107mA    818.5uA
-924mV    750.8uA    1.296mA    641.3uA
-878mV    507uA      821.4uA    530.2uA
-809mV    327.4uA    430uA      403.3uA
-694mV    178.4uA    161uA      233uA
-464mV    19.89uA    15.19uA    23.61uA
1.1V      0A         0A         0A
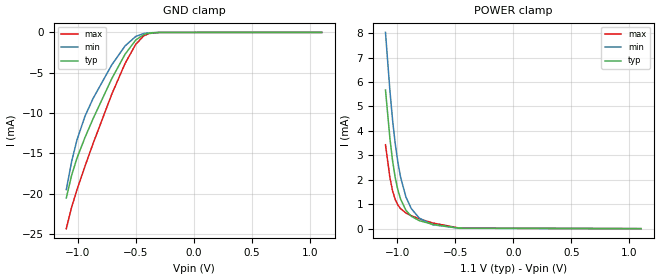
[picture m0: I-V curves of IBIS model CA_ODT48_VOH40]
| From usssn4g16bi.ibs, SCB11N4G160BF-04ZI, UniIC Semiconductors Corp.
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|   Model CA_ODT48_VOH40
[Model] CA_ODT48_VOH40
Model_type Input
Vinl =  0.130V
Vinh =  0.310V
C_comp   0.710pF   0.700pF   0.720pF
[Model Spec]
Vinh   0.310V   0.302V   0.324V
Vinl   0.130V   0.122V   0.144V
[Add Submodel]
|  Submodel_name   Mode
ODT48_VOH40_CACLK   Non-Driving
[Temperature Range]   25.000   85.000   -40.000
[Voltage Range]   1.100V   1.060V   1.170V
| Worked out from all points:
|   GND clamp passes 1 mA (typ) near -0.51 V on its own axis
|   POWER clamp passes 1 mA (typ) near -0.95 V on its own axis
[GND_clamp]
|Voltage   I(typ)   I(min)   I(max)
-1.1V     -20.5mA    -19.47mA   -24.31mA
-1.054V   -17.69mA   -15.99mA   -21.65mA
-1.008V   -15.57mA   -13.31mA   -19.49mA
-939mV    -13.01mA   -10.38mA   -16.57mA
-870mV    -10.71mA   -8.197mA   -13.79mA
-709mV    -5.741mA   -4.034mA   -7.675mA
-594mV    -2.707mA   -1.676mA   -3.85mA
-502mV    -951.2uA   -499.9uA   -1.477mA
-433mV    -266.6uA   -132.5uA   -430.6uA
-387mV    -88.17uA   -46.5uA    -135.3uA
-295mV    -6.313uA   -4.425uA   -6.983uA
1.1V      0A         0A         0A
[POWER_clamp]
|Voltage   I(typ)   I(min)   I(max)
-1.1V     5.671mA    8.029mA    3.433mA
-1.062V   3.7mA      5.646mA    2.09mA
-1.039V   2.777mA    4.446mA    1.545mA
-1.016V   2.084mA    3.473mA    1.192mA
-993mV    1.577mA    2.703mA    966.4uA
-970mV    1.209mA    2.105mA    818.5uA
-924mV    750.7uA    1.296mA    641.3uA
-878mV    507uA      821.3uA    530.2uA
-809mV    327.4uA    430uA      403.3uA
-694mV    178.4uA    161uA      233uA
-464mV    19.89uA    15.19uA    23.61uA
1.1V      0A         0A         0A
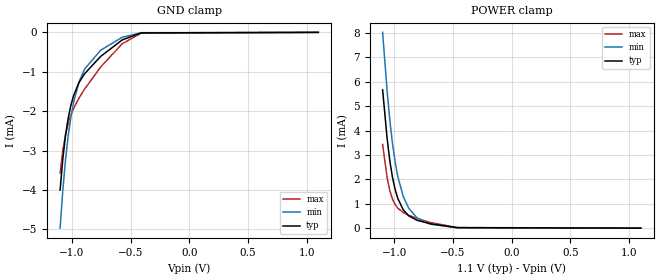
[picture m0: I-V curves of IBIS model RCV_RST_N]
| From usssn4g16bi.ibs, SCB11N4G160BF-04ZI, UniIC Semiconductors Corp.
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|   Model RCV_RST_N
[Model] RCV_RST_N
Model_type Input
Vinl =  0.130V
Vinh =  0.310V
C_comp   0.700pF   0.690pF   0.710pF
[Model Spec]
Vinh   0.880V   0.848V   0.936V
Vinl   0.220V   0.212V   0.234V
[Temperature Range]   25.000   85.000   -40.000
[Voltage Range]   1.100V   1.060V   1.170V
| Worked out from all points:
|   GND clamp passes 1 mA (typ) near -0.88 V on its own axis
|   POWER clamp passes 1 mA (typ) near -0.95 V on its own axis
[GND_clamp]
|Voltage   I(typ)   I(min)   I(max)
-1.1V     -4.004mA   -4.971mA   -3.573mA
-1.077V   -3.213mA   -4.011mA   -2.999mA
-1.054V   -2.617mA   -3.238mA   -2.598mA
-1.031V   -2.175mA   -2.626mA   -2.312mA
-1.008V   -1.849mA   -2.147mA   -2.099mA
-985mV    -1.605mA   -1.775mA   -1.932mA
-939mV    -1.274mA   -1.259mA   -1.668mA
-893mV    -1.055mA   -938.1uA   -1.447mA
-755mV    -611.7uA   -454.8uA   -881.6uA
-571mV    -191.9uA   -125.3uA   -288uA
-410mV    -13.76uA   -8.476uA   -20.37uA
1.1V      1.053pA    0A         -7.963pA
[POWER_clamp]
|Voltage   I(typ)   I(min)   I(max)
-1.1V     5.671mA    8.029mA    3.433mA
-1.062V   3.7mA      5.646mA    2.09mA
-1.039V   2.777mA    4.446mA    1.545mA
-1.016V   2.084mA    3.473mA    1.192mA
-993mV    1.577mA    2.703mA    966.4uA
-970mV    1.209mA    2.105mA    818.5uA
-924mV    750.7uA    1.296mA    641.3uA
-878mV    507uA      821.3uA    530.2uA
-809mV    327.4uA    430uA      403.3uA
-694mV    178.4uA    161uA      233uA
-464mV    19.88uA    15.19uA    23.61uA
1.1V      0A         0A         0A
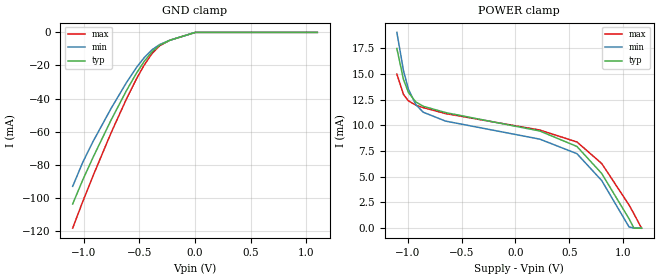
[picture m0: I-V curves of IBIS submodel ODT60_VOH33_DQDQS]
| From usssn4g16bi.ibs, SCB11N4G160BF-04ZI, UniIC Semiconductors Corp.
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|   Submodel ODT60_VOH33_DQDQS
[Submodel] ODT60_VOH33_DQDQS
Submodel_type Dynamic_clamp
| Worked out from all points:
|   GND clamp passes 1 mA (typ) near -0.05 V on its own axis
[GND_clamp]
|Voltage   I(typ)   I(min)   I(max)
-1.1V     -103.6mA   -92.95mA   -118.2mA
-1.008V   -88.86mA   -78.25mA   -101.9mA
-916mV    -75.34mA   -65.78mA   -86.48mA
-755mV    -52.99mA   -45.97mA   -60.71mA
-617mV    -35.21mA   -30.36mA   -40.27mA
-525mV    -24.48mA   -21.08mA   -27.88mA
-456mV    -17.45mA   -15.17mA   -19.64mA
-387mV    -11.75mA   -10.53mA   -12.84mA
-318mV    -7.765mA   -7.354mA   -8.072mA
-226mV    -4.748mA   -4.738mA   -4.752mA
4mV       0A         0A         0A
1.1V      0A         0A         0A
[POWER_clamp]
|Voltage   I(typ)   I(min)   I(max)
-1.1V     17.47mA    19.04mA    14.98mA
-1.039V   14.47mA    15.34mA    13.01mA
-993mV    13.2mA     13.52mA    12.38mA
-924mV    12.27mA    12.01mA    11.96mA
-855mV    11.85mA    11.27mA    11.72mA
-648mV    11.24mA    10.41mA    11.14mA
226mV     9.447mA    8.656mA    9.541mA
571mV     7.941mA    7.24mA     8.38mA
801mV     5.311mA    4.623mA    6.282mA
1.054V    913.3uA    120.3uA    2.256mA
1.1V      0A         0A         1.387mA
1.17V     0A         0A         0A
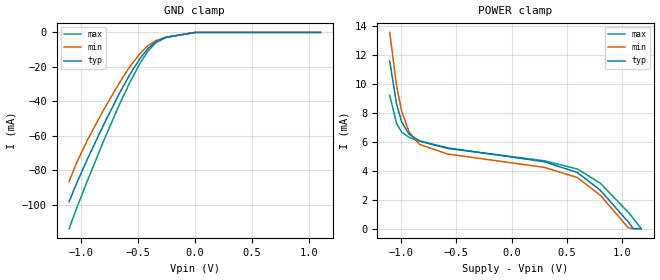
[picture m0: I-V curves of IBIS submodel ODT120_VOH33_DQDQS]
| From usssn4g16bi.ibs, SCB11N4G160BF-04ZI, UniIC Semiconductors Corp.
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|   Submodel ODT120_VOH33_DQDQS
[Submodel] ODT120_VOH33_DQDQS
Submodel_type Dynamic_clamp
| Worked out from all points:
|   GND clamp passes 1 mA (typ) near -0.10 V on its own axis
[GND_clamp]
|Voltage   I(typ)   I(min)   I(max)
-1.1V     -98.12mA   -86.46mA   -113.8mA
-1.031V   -86.98mA   -75.12mA   -101.4mA
-939mV    -73.35mA   -62.35mA   -85.9mA
-801mV    -53.97mA   -45.29mA   -63.46mA
-663mV    -35.78mA   -29.55mA   -42.32mA
-571mV    -24.67mA   -20.1mA    -29.33mA
-479mV    -15.04mA   -12.18mA   -17.83mA
-410mV    -9.366mA   -7.708mA   -10.88mA
-341mV    -5.438mA   -4.751mA   -5.981mA
-249mV    -2.817mA   -2.742mA   -2.853mA
4mV       0A         0A         0A
1.1V      0A         0A         0A
[POWER_clamp]
|Voltage   I(typ)   I(min)   I(max)
-1.1V     11.58mA    13.56mA    9.213mA
-1.039V   8.629mA    9.903mA    7.281mA
-993mV    7.392mA    8.118mA    6.673mA
-924mV    6.515mA    6.657mA    6.305mA
-832mV    6.069mA    5.823mA    6.048mA
-579mV    5.583mA    5.159mA    5.542mA
295mV     4.626mA    4.235mA    4.69mA
594mV     3.878mA    3.532mA    4.123mA
801mV     2.655mA    2.311mA    3.141mA
1.054V    456.6uA    60.05uA    1.128mA
1.1V      0A         0A         693.2uA
1.17V     0A         0A         0A
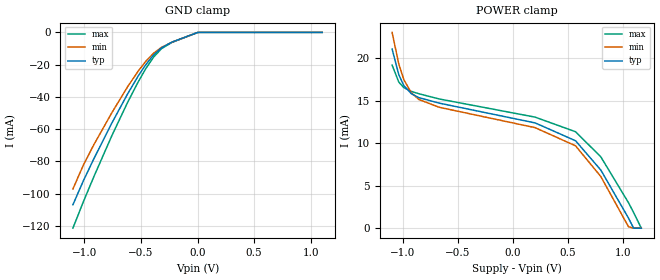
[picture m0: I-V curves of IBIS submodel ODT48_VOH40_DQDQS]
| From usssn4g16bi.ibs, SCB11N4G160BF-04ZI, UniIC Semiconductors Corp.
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|   Submodel ODT48_VOH40_DQDQS
[Submodel] ODT48_VOH40_DQDQS
Submodel_type Dynamic_clamp
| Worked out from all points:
|   GND clamp passes 1 mA (typ) near -0.04 V on its own axis
[GND_clamp]
|Voltage   I(typ)   I(min)   I(max)
-1.1V     -106.8mA   -97.03mA   -121.3mA
-1.008V   -92.02mA   -82.29mA   -105mA
-916mV    -78.45mA   -69.7mA    -89.56mA
-755mV    -56.03mA   -49.63mA   -63.83mA
-617mV    -38.12mA   -33.71mA   -43.38mA
-525mV    -27.21mA   -24.12mA   -30.86mA
-456mV    -19.94mA   -17.89mA   -22.4mA
-387mV    -13.93mA   -12.87mA   -15.28mA
-318mV    -9.572mA   -9.287mA   -10.11mA
-226mV    -6.037mA   -6.114mA   -6.212mA
4mV       0A         0A         0A
1.1V      0A         0A         0A
[POWER_clamp]
|Voltage   I(typ)   I(min)   I(max)
-1.1V     21.09mA    23.05mA    19.2mA
-1.039V   18.07mA    19.32mA    17.2mA
-993mV    16.78mA    17.48mA    16.54mA
-924mV    15.82mA    15.92mA    16.1mA
-855mV    15.36mA    15.14mA    15.82mA
-671mV    14.72mA    14.23mA    15.21mA
203mV     12.39mA    11.83mA    13.07mA
571mV     10.29mA    9.694mA    11.35mA
801mV     6.846mA    6.083mA    8.399mA
1.054V    1.172mA    156.7uA    2.986mA
1.1V      0A         0A         1.832mA
1.17V     0A         0A         0A
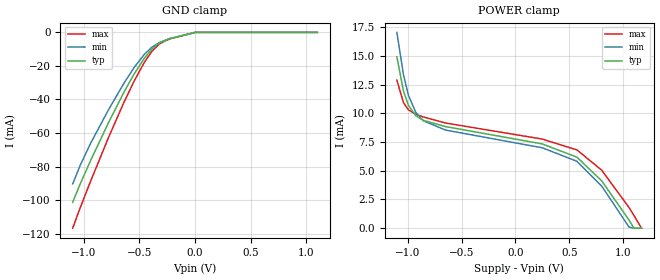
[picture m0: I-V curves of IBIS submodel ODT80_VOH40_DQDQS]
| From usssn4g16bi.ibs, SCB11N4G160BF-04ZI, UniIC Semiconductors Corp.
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|   Submodel ODT80_VOH40_DQDQS
[Submodel] ODT80_VOH40_DQDQS
Submodel_type Dynamic_clamp
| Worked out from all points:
|   GND clamp passes 1 mA (typ) near -0.06 V on its own axis
[GND_clamp]
|Voltage   I(typ)   I(min)   I(max)
-1.1V     -101.3mA   -90.34mA   -116.7mA
-1.031V   -90.11mA   -79.01mA   -104.3mA
-939mV    -76.41mA   -66.16mA   -88.75mA
-778mV    -53.84mA   -46.15mA   -62.7mA
-640mV    -35.81mA   -30.41mA   -41.86mA
-548mV    -24.85mA   -21mA      -29.11mA
-456mV    -15.45mA   -13.16mA   -17.93mA
-387mV    -9.993mA   -8.798mA   -11.29mA
-318mV    -6.298mA   -5.927mA   -6.769mA
-226mV    -3.7mA     -3.726mA   -3.813mA
4mV       0A         0A         0A
1.1V      0A         0A         0A
[POWER_clamp]
|Voltage   I(typ)   I(min)   I(max)
-1.1V     14.94mA    17.07mA    12.91mA
-1.039V   11.96mA    13.39mA    10.95mA
-993mV    10.71mA    11.58mA    10.32mA
-924mV    9.801mA    10.09mA    9.926mA
-855mV    9.4mA      9.363mA    9.697mA
-648mV    8.855mA    8.551mA    9.166mA
249mV     7.343mA    7.005mA    7.764mA
571mV     6.186mA    5.828mA    6.819mA
801mV     4.118mA    3.66mA     5.051mA
1.054V    705.4uA    94.24uA    1.797mA
1.1V      0A         0A         1.103mA
1.17V     0A         0A         0A
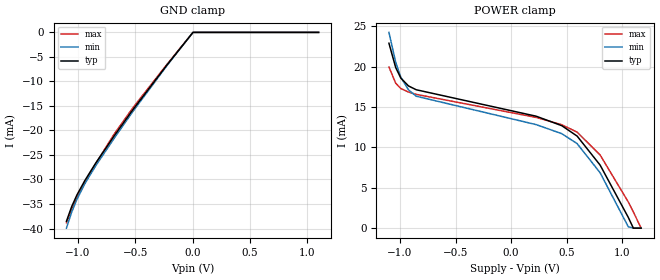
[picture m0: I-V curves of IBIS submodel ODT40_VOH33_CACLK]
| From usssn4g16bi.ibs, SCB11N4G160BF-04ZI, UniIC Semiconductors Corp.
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|   Submodel ODT40_VOH33_CACLK
[Submodel] ODT40_VOH33_CACLK
Submodel_type Dynamic_clamp
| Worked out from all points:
|   GND clamp passes 1 mA (typ) near -0.03 V on its own axis
[GND_clamp]
|Voltage   I(typ)   I(min)   I(max)
-1.1V     -38.52mA   -39.92mA   -38.81mA
-1.054V   -35.51mA   -36.64mA   -36.02mA
-1.008V   -33.14mA   -34.02mA   -33.72mA
-939mV    -30.2mA    -30.85mA   -30.66mA
-847mV    -26.75mA   -27.3mA    -26.86mA
-686mV    -21.19mA   -21.67mA   -20.82mA
-525mV    -15.92mA   -16.29mA   -15.52mA
-226mV    -6.74mA    -6.857mA   -6.605mA
4mV       0A         0A         0A
1.1V      0A         0A         0A
[POWER_clamp]
|Voltage   I(typ)   I(min)   I(max)
-1.1V     22.89mA    24.23mA    19.94mA
-1.039V   19.87mA    20.52mA    17.94mA
-993mV    18.57mA    18.68mA    17.28mA
-924mV    17.6mA     17.12mA    16.84mA
-855mV    17.13mA    16.33mA    16.56mA
226mV     13.85mA    12.81mA    13.7mA
456mV     12.68mA    11.69mA    12.8mA
594mV     11.39mA    10.46mA    11.88mA
801mV     7.798mA    6.847mA    9.054mA
1.054V    1.339mA    178.4uA    3.248mA
1.1V      0A         0A         1.996mA
1.17V     0A         0A         0A
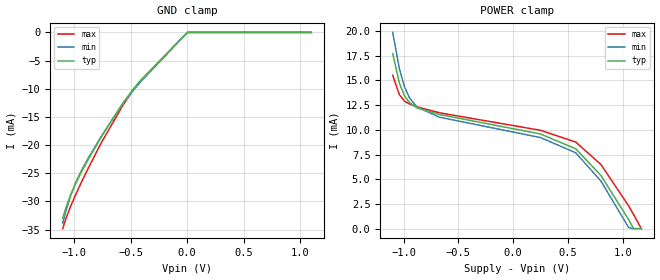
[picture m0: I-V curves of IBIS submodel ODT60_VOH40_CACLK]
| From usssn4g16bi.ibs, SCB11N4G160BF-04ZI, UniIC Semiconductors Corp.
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|   Submodel ODT60_VOH40_CACLK
[Submodel] ODT60_VOH40_CACLK
Submodel_type Dynamic_clamp
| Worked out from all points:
|   GND clamp passes 1 mA (typ) near -0.05 V on its own axis
[GND_clamp]
|Voltage   I(typ)   I(min)   I(max)
-1.1V     -33.02mA   -33.84mA   -34.83mA
-1.077V   -31.44mA   -32.06mA   -33.37mA
-1.031V   -28.86mA   -29.07mA   -30.91mA
-985mV    -26.77mA   -26.68mA   -28.79mA
-939mV    -24.93mA   -24.7mA    -26.8mA
-870mV    -22.4mA    -22.14mA   -23.95mA
-755mV    -18.44mA   -18.31mA   -19.46mA
-571mV    -12.64mA   -12.75mA   -13.06mA
-479mV    -10.13mA   -10.36mA   -10.32mA
-410mV    -8.495mA   -8.758mA   -8.582mA
4mV       0A         0A         0A
1.1V      0A         0A         0A
[POWER_clamp]
|Voltage   I(typ)   I(min)   I(max)
-1.1V     17.71mA    19.86mA    15.52mA
-1.039V   14.73mA    16.18mA    13.55mA
-993mV    13.46mA    14.37mA    12.91mA
-947mV    12.76mA    13.24mA    12.61mA
-878mV    12.22mA    12.3mA     12.33mA
-671mV    11.55mA    11.27mA    11.72mA
249mV     9.581mA    9.221mA    9.954mA
571mV     8.084mA    7.679mA    8.763mA
801mV     5.38mA     4.822mA    6.497mA
1.054V    920.6uA    124.4uA    2.309mA
1.1V      0A         0A         1.417mA
1.17V     0A         0A         0A
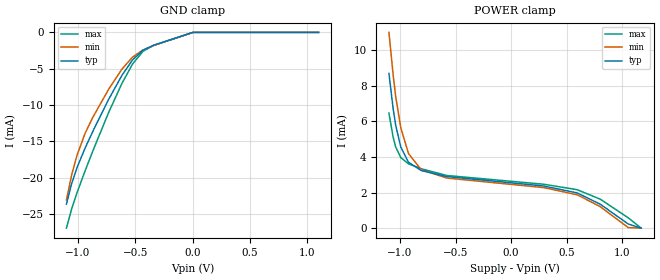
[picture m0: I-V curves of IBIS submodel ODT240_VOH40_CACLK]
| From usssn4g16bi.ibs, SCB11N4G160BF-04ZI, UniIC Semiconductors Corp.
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|   Submodel ODT240_VOH40_CACLK
[Submodel] ODT240_VOH40_CACLK
Submodel_type Dynamic_clamp
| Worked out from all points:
|   GND clamp passes 1 mA (typ) near -0.19 V on its own axis
[GND_clamp]
|Voltage   I(typ)   I(min)   I(max)
-1.1V     -23.63mA   -23.05mA   -26.94mA
-1.054V   -20.79mA   -19.6mA    -24.26mA
-1.008V   -18.62mA   -16.93mA   -22.07mA
-939mV    -15.99mA   -13.96mA   -19.13mA
-870mV    -13.63mA   -11.69mA   -16.33mA
-732mV    -9.23mA    -7.831mA   -11.03mA
-617mV    -5.949mA   -5.084mA   -7.058mA
-525mV    -3.819mA   -3.423mA   -4.398mA
-433mV    -2.46mA    -2.427mA   -2.61mA
-341mV    -1.778mA   -1.828mA   -1.8mA
4mV       0A         0A         0A
1.1V      0A         0A         0A
[POWER_clamp]
|Voltage   I(typ)   I(min)   I(max)
-1.1V     8.685mA    10.99mA    6.458mA
-1.062V   6.701mA    8.595mA    5.103mA
-1.039V   5.769mA    7.386mA    4.551mA
-993mV    4.551mA    5.624mA    3.958mA
-924mV    3.7mA      4.189mA    3.61mA
-809mV    3.233mA    3.276mA    3.334mA
-579mV    2.895mA    2.812mA    2.955mA
295mV     2.364mA    2.274mA    2.463mA
594mV     1.977mA    1.874mA    2.158mA
801mV     1.349mA    1.21mA     1.629mA
1.054V    230.9uA    31.21uA    579.4uA
1.17V     0A         0A         0A
